VERSION 5.8 ;
BUSBITCHARS "[]" ;
DIVIDERCHAR "/" ;
UNITS
    DATABASE MICRONS 1000 ;
END UNITS

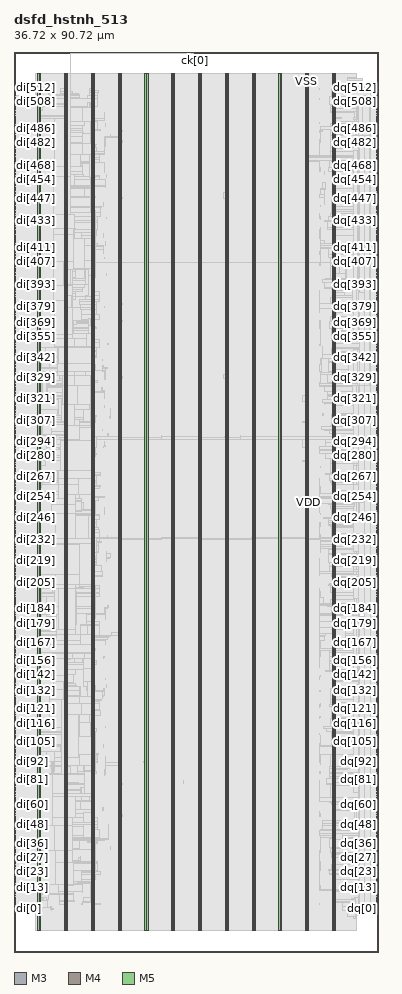
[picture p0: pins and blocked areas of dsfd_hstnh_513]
MACRO dsfd_hstnh_513
  FOREIGN dsfd_hstnh_513 0 0 ;
  CLASS BLOCK ;
  SIZE 36.72 BY 90.72 ;
  PIN ck[0]
    DIRECTION INPUT ;
    USE SIGNAL ;
    PORT
      LAYER M3 ;
        RECT  18.36 90.576 18.378 90.72 ;
    END
    PORT
      LAYER M3 ;
        RECT  18.18 90.553 18.378 90.588 ;
    END
  END ck[0]
  PIN di[0]
    DIRECTION INPUT ;
    USE SIGNAL ;
    PORT
      LAYER M4 ;
        RECT  0 4.416 0.192 4.44 ;
    END
  END di[0]
  PIN di[100]
    DIRECTION INPUT ;
    USE SIGNAL ;
    PORT
      LAYER M4 ;
        RECT  0 20.4 0.192 20.424 ;
    END
  END di[100]
  PIN di[101]
    DIRECTION INPUT ;
    USE SIGNAL ;
    PORT
      LAYER M4 ;
        RECT  0 20.592 0.192 20.616 ;
    END
  END di[101]
  PIN di[102]
    DIRECTION INPUT ;
    USE SIGNAL ;
    PORT
      LAYER M4 ;
        RECT  0 20.736 0.192 20.76 ;
    END
  END di[102]
  PIN di[103]
    DIRECTION INPUT ;
    USE SIGNAL ;
    PORT
      LAYER M4 ;
        RECT  0 20.88 0.192 20.904 ;
    END
  END di[103]
  PIN di[104]
    DIRECTION INPUT ;
    USE SIGNAL ;
    PORT
      LAYER M4 ;
        RECT  0 21.072 0.192 21.096 ;
    END
  END di[104]
  PIN di[105]
    DIRECTION INPUT ;
    USE SIGNAL ;
    PORT
      LAYER M4 ;
        RECT  0 21.216 0.192 21.24 ;
    END
  END di[105]
  PIN di[106]
    DIRECTION INPUT ;
    USE SIGNAL ;
    PORT
      LAYER M4 ;
        RECT  0 21.36 0.192 21.384 ;
    END
  END di[106]
  PIN di[107]
    DIRECTION INPUT ;
    USE SIGNAL ;
    PORT
      LAYER M4 ;
        RECT  0 21.552 0.192 21.576 ;
    END
  END di[107]
  PIN di[108]
    DIRECTION INPUT ;
    USE SIGNAL ;
    PORT
      LAYER M4 ;
        RECT  0 21.696 0.192 21.72 ;
    END
  END di[108]
  PIN di[109]
    DIRECTION INPUT ;
    USE SIGNAL ;
    PORT
      LAYER M4 ;
        RECT  0 21.84 0.192 21.864 ;
    END
  END di[109]
  PIN di[10]
    DIRECTION INPUT ;
    USE SIGNAL ;
    PORT
      LAYER M4 ;
        RECT  0 6 0.192 6.024 ;
    END
  END di[10]
  PIN di[110]
    DIRECTION INPUT ;
    USE SIGNAL ;
    PORT
      LAYER M4 ;
        RECT  0 22.032 0.192 22.056 ;
    END
  END di[110]
  PIN di[111]
    DIRECTION INPUT ;
    USE SIGNAL ;
    PORT
      LAYER M4 ;
        RECT  0 22.176 0.192 22.2 ;
    END
  END di[111]
  PIN di[112]
    DIRECTION INPUT ;
    USE SIGNAL ;
    PORT
      LAYER M4 ;
        RECT  0 22.32 0.192 22.344 ;
    END
  END di[112]
  PIN di[113]
    DIRECTION INPUT ;
    USE SIGNAL ;
    PORT
      LAYER M4 ;
        RECT  0 22.512 0.192 22.536 ;
    END
  END di[113]
  PIN di[114]
    DIRECTION INPUT ;
    USE SIGNAL ;
    PORT
      LAYER M4 ;
        RECT  0 22.656 0.192 22.68 ;
    END
  END di[114]
  PIN di[115]
    DIRECTION INPUT ;
    USE SIGNAL ;
    PORT
      LAYER M4 ;
        RECT  0 22.8 0.192 22.824 ;
    END
  END di[115]
  PIN di[116]
    DIRECTION INPUT ;
    USE SIGNAL ;
    PORT
      LAYER M4 ;
        RECT  0 22.992 0.192 23.016 ;
    END
  END di[116]
  PIN di[117]
    DIRECTION INPUT ;
    USE SIGNAL ;
    PORT
      LAYER M4 ;
        RECT  0 23.136 0.192 23.16 ;
    END
  END di[117]
  PIN di[118]
    DIRECTION INPUT ;
    USE SIGNAL ;
    PORT
      LAYER M4 ;
        RECT  0 23.28 0.192 23.304 ;
    END
  END di[118]
  PIN di[119]
    DIRECTION INPUT ;
    USE SIGNAL ;
    PORT
      LAYER M4 ;
        RECT  0 23.472 0.192 23.496 ;
    END
  END di[119]
  PIN di[11]
    DIRECTION INPUT ;
    USE SIGNAL ;
    PORT
      LAYER M4 ;
        RECT  0 6.192 0.192 6.216 ;
    END
  END di[11]
  PIN di[120]
    DIRECTION INPUT ;
    USE SIGNAL ;
    PORT
      LAYER M4 ;
        RECT  0 23.616 0.192 23.64 ;
    END
  END di[120]
  PIN di[121]
    DIRECTION INPUT ;
    USE SIGNAL ;
    PORT
      LAYER M4 ;
        RECT  0 23.76 0.192 23.784 ;
    END
  END di[121]
  PIN di[122]
    DIRECTION INPUT ;
    USE SIGNAL ;
    PORT
      LAYER M4 ;
        RECT  0 23.952 0.192 23.976 ;
    END
  END di[122]
  PIN di[123]
    DIRECTION INPUT ;
    USE SIGNAL ;
    PORT
      LAYER M4 ;
        RECT  0 24.096 0.192 24.12 ;
    END
  END di[123]
  PIN di[124]
    DIRECTION INPUT ;
    USE SIGNAL ;
    PORT
      LAYER M4 ;
        RECT  0 24.24 0.192 24.264 ;
    END
  END di[124]
  PIN di[125]
    DIRECTION INPUT ;
    USE SIGNAL ;
    PORT
      LAYER M4 ;
        RECT  0 24.432 0.192 24.456 ;
    END
  END di[125]
  PIN di[126]
    DIRECTION INPUT ;
    USE SIGNAL ;
    PORT
      LAYER M4 ;
        RECT  0 24.576 0.192 24.6 ;
    END
  END di[126]
  PIN di[127]
    DIRECTION INPUT ;
    USE SIGNAL ;
    PORT
      LAYER M4 ;
        RECT  0 24.72 0.192 24.744 ;
    END
  END di[127]
  PIN di[128]
    DIRECTION INPUT ;
    USE SIGNAL ;
    PORT
      LAYER M4 ;
        RECT  0 24.912 0.192 24.936 ;
    END
  END di[128]
  PIN di[129]
    DIRECTION INPUT ;
    USE SIGNAL ;
    PORT
      LAYER M4 ;
        RECT  0 25.056 0.192 25.08 ;
    END
  END di[129]
  PIN di[12]
    DIRECTION INPUT ;
    USE SIGNAL ;
    PORT
      LAYER M4 ;
        RECT  0 6.336 0.192 6.36 ;
    END
  END di[12]
  PIN di[130]
    DIRECTION INPUT ;
    USE SIGNAL ;
    PORT
      LAYER M4 ;
        RECT  0 25.2 0.192 25.224 ;
    END
  END di[130]
  PIN di[131]
    DIRECTION INPUT ;
    USE SIGNAL ;
    PORT
      LAYER M4 ;
        RECT  0 25.392 0.192 25.416 ;
    END
  END di[131]
  PIN di[132]
    DIRECTION INPUT ;
    USE SIGNAL ;
    PORT
      LAYER M4 ;
        RECT  0 25.536 0.192 25.56 ;
    END
  END di[132]
  PIN di[133]
    DIRECTION INPUT ;
    USE SIGNAL ;
    PORT
      LAYER M4 ;
        RECT  0 25.68 0.192 25.704 ;
    END
  END di[133]
  PIN di[134]
    DIRECTION INPUT ;
    USE SIGNAL ;
    PORT
      LAYER M4 ;
        RECT  0 25.872 0.192 25.896 ;
    END
  END di[134]
  PIN di[135]
    DIRECTION INPUT ;
    USE SIGNAL ;
    PORT
      LAYER M4 ;
        RECT  0 26.016 0.192 26.04 ;
    END
  END di[135]
  PIN di[136]
    DIRECTION INPUT ;
    USE SIGNAL ;
    PORT
      LAYER M4 ;
        RECT  0 26.16 0.192 26.184 ;
    END
  END di[136]
  PIN di[137]
    DIRECTION INPUT ;
    USE SIGNAL ;
    PORT
      LAYER M4 ;
        RECT  0 26.352 0.192 26.376 ;
    END
  END di[137]
  PIN di[138]
    DIRECTION INPUT ;
    USE SIGNAL ;
    PORT
      LAYER M4 ;
        RECT  0 26.496 0.192 26.52 ;
    END
  END di[138]
  PIN di[139]
    DIRECTION INPUT ;
    USE SIGNAL ;
    PORT
      LAYER M4 ;
        RECT  0 26.64 0.192 26.664 ;
    END
  END di[139]
  PIN di[13]
    DIRECTION INPUT ;
    USE SIGNAL ;
    PORT
      LAYER M4 ;
        RECT  0 6.48 0.192 6.504 ;
    END
  END di[13]
  PIN di[140]
    DIRECTION INPUT ;
    USE SIGNAL ;
    PORT
      LAYER M4 ;
        RECT  0 26.832 0.192 26.856 ;
    END
  END di[140]
  PIN di[141]
    DIRECTION INPUT ;
    USE SIGNAL ;
    PORT
      LAYER M4 ;
        RECT  0 26.976 0.192 27 ;
    END
  END di[141]
  PIN di[142]
    DIRECTION INPUT ;
    USE SIGNAL ;
    PORT
      LAYER M4 ;
        RECT  0 27.12 0.192 27.144 ;
    END
  END di[142]
  PIN di[143]
    DIRECTION INPUT ;
    USE SIGNAL ;
    PORT
      LAYER M4 ;
        RECT  0 27.312 0.192 27.336 ;
    END
  END di[143]
  PIN di[144]
    DIRECTION INPUT ;
    USE SIGNAL ;
    PORT
      LAYER M4 ;
        RECT  0 27.456 0.192 27.48 ;
    END
  END di[144]
  PIN di[145]
    DIRECTION INPUT ;
    USE SIGNAL ;
    PORT
      LAYER M4 ;
        RECT  0 27.6 0.192 27.624 ;
    END
  END di[145]
  PIN di[146]
    DIRECTION INPUT ;
    USE SIGNAL ;
    PORT
      LAYER M4 ;
        RECT  0 27.792 0.192 27.816 ;
    END
  END di[146]
  PIN di[147]
    DIRECTION INPUT ;
    USE SIGNAL ;
    PORT
      LAYER M4 ;
        RECT  0 27.936 0.192 27.96 ;
    END
  END di[147]
  PIN di[148]
    DIRECTION INPUT ;
    USE SIGNAL ;
    PORT
      LAYER M4 ;
        RECT  0 28.08 0.192 28.104 ;
    END
  END di[148]
  PIN di[149]
    DIRECTION INPUT ;
    USE SIGNAL ;
    PORT
      LAYER M4 ;
        RECT  0 28.272 0.192 28.296 ;
    END
  END di[149]
  PIN di[14]
    DIRECTION INPUT ;
    USE SIGNAL ;
    PORT
      LAYER M4 ;
        RECT  0 6.672 0.192 6.696 ;
    END
  END di[14]
  PIN di[150]
    DIRECTION INPUT ;
    USE SIGNAL ;
    PORT
      LAYER M4 ;
        RECT  0 28.416 0.192 28.44 ;
    END
  END di[150]
  PIN di[151]
    DIRECTION INPUT ;
    USE SIGNAL ;
    PORT
      LAYER M4 ;
        RECT  0 28.56 0.192 28.584 ;
    END
  END di[151]
  PIN di[152]
    DIRECTION INPUT ;
    USE SIGNAL ;
    PORT
      LAYER M4 ;
        RECT  0 28.752 0.192 28.776 ;
    END
  END di[152]
  PIN di[153]
    DIRECTION INPUT ;
    USE SIGNAL ;
    PORT
      LAYER M4 ;
        RECT  0 28.896 0.192 28.92 ;
    END
  END di[153]
  PIN di[154]
    DIRECTION INPUT ;
    USE SIGNAL ;
    PORT
      LAYER M4 ;
        RECT  0 29.04 0.192 29.064 ;
    END
  END di[154]
  PIN di[155]
    DIRECTION INPUT ;
    USE SIGNAL ;
    PORT
      LAYER M4 ;
        RECT  0 29.232 0.192 29.256 ;
    END
  END di[155]
  PIN di[156]
    DIRECTION INPUT ;
    USE SIGNAL ;
    PORT
      LAYER M4 ;
        RECT  0 29.376 0.192 29.4 ;
    END
  END di[156]
  PIN di[157]
    DIRECTION INPUT ;
    USE SIGNAL ;
    PORT
      LAYER M4 ;
        RECT  0 29.52 0.192 29.544 ;
    END
  END di[157]
  PIN di[158]
    DIRECTION INPUT ;
    USE SIGNAL ;
    PORT
      LAYER M4 ;
        RECT  0 29.712 0.192 29.736 ;
    END
  END di[158]
  PIN di[159]
    DIRECTION INPUT ;
    USE SIGNAL ;
    PORT
      LAYER M4 ;
        RECT  0 29.856 0.192 29.88 ;
    END
  END di[159]
  PIN di[15]
    DIRECTION INPUT ;
    USE SIGNAL ;
    PORT
      LAYER M4 ;
        RECT  0 6.816 0.192 6.84 ;
    END
  END di[15]
  PIN di[160]
    DIRECTION INPUT ;
    USE SIGNAL ;
    PORT
      LAYER M4 ;
        RECT  0 30 0.192 30.024 ;
    END
  END di[160]
  PIN di[161]
    DIRECTION INPUT ;
    USE SIGNAL ;
    PORT
      LAYER M4 ;
        RECT  0 30.192 0.192 30.216 ;
    END
  END di[161]
  PIN di[162]
    DIRECTION INPUT ;
    USE SIGNAL ;
    PORT
      LAYER M4 ;
        RECT  0 30.336 0.192 30.36 ;
    END
  END di[162]
  PIN di[163]
    DIRECTION INPUT ;
    USE SIGNAL ;
    PORT
      LAYER M4 ;
        RECT  0 30.48 0.192 30.504 ;
    END
  END di[163]
  PIN di[164]
    DIRECTION INPUT ;
    USE SIGNAL ;
    PORT
      LAYER M4 ;
        RECT  0 30.672 0.192 30.696 ;
    END
  END di[164]
  PIN di[165]
    DIRECTION INPUT ;
    USE SIGNAL ;
    PORT
      LAYER M4 ;
        RECT  0 30.816 0.192 30.84 ;
    END
  END di[165]
  PIN di[166]
    DIRECTION INPUT ;
    USE SIGNAL ;
    PORT
      LAYER M4 ;
        RECT  0 30.96 0.192 30.984 ;
    END
  END di[166]
  PIN di[167]
    DIRECTION INPUT ;
    USE SIGNAL ;
    PORT
      LAYER M4 ;
        RECT  0 31.152 0.192 31.176 ;
    END
  END di[167]
  PIN di[168]
    DIRECTION INPUT ;
    USE SIGNAL ;
    PORT
      LAYER M4 ;
        RECT  0 31.296 0.192 31.32 ;
    END
  END di[168]
  PIN di[169]
    DIRECTION INPUT ;
    USE SIGNAL ;
    PORT
      LAYER M4 ;
        RECT  0 31.44 0.192 31.464 ;
    END
  END di[169]
  PIN di[16]
    DIRECTION INPUT ;
    USE SIGNAL ;
    PORT
      LAYER M4 ;
        RECT  0 6.96 0.192 6.984 ;
    END
  END di[16]
  PIN di[170]
    DIRECTION INPUT ;
    USE SIGNAL ;
    PORT
      LAYER M4 ;
        RECT  0 31.632 0.192 31.656 ;
    END
  END di[170]
  PIN di[171]
    DIRECTION INPUT ;
    USE SIGNAL ;
    PORT
      LAYER M4 ;
        RECT  0 31.776 0.192 31.8 ;
    END
  END di[171]
  PIN di[172]
    DIRECTION INPUT ;
    USE SIGNAL ;
    PORT
      LAYER M4 ;
        RECT  0 31.92 0.192 31.944 ;
    END
  END di[172]
  PIN di[173]
    DIRECTION INPUT ;
    USE SIGNAL ;
    PORT
      LAYER M4 ;
        RECT  0 32.112 0.192 32.136 ;
    END
  END di[173]
  PIN di[174]
    DIRECTION INPUT ;
    USE SIGNAL ;
    PORT
      LAYER M4 ;
        RECT  0 32.256 0.192 32.28 ;
    END
  END di[174]
  PIN di[175]
    DIRECTION INPUT ;
    USE SIGNAL ;
    PORT
      LAYER M4 ;
        RECT  0 32.4 0.192 32.424 ;
    END
  END di[175]
  PIN di[176]
    DIRECTION INPUT ;
    USE SIGNAL ;
    PORT
      LAYER M4 ;
        RECT  0 32.592 0.192 32.616 ;
    END
  END di[176]
  PIN di[177]
    DIRECTION INPUT ;
    USE SIGNAL ;
    PORT
      LAYER M4 ;
        RECT  0 32.736 0.192 32.76 ;
    END
  END di[177]
  PIN di[178]
    DIRECTION INPUT ;
    USE SIGNAL ;
    PORT
      LAYER M4 ;
        RECT  0 32.88 0.192 32.904 ;
    END
  END di[178]
  PIN di[179]
    DIRECTION INPUT ;
    USE SIGNAL ;
    PORT
      LAYER M4 ;
        RECT  0 33.072 0.192 33.096 ;
    END
  END di[179]
  PIN di[17]
    DIRECTION INPUT ;
    USE SIGNAL ;
    PORT
      LAYER M4 ;
        RECT  0 7.152 0.192 7.176 ;
    END
  END di[17]
  PIN di[180]
    DIRECTION INPUT ;
    USE SIGNAL ;
    PORT
      LAYER M4 ;
        RECT  0 33.216 0.192 33.24 ;
    END
  END di[180]
  PIN di[181]
    DIRECTION INPUT ;
    USE SIGNAL ;
    PORT
      LAYER M4 ;
        RECT  0 33.36 0.192 33.384 ;
    END
  END di[181]
  PIN di[182]
    DIRECTION INPUT ;
    USE SIGNAL ;
    PORT
      LAYER M4 ;
        RECT  0 33.552 0.192 33.576 ;
    END
  END di[182]
  PIN di[183]
    DIRECTION INPUT ;
    USE SIGNAL ;
    PORT
      LAYER M4 ;
        RECT  0 33.696 0.192 33.72 ;
    END
  END di[183]
  PIN di[184]
    DIRECTION INPUT ;
    USE SIGNAL ;
    PORT
      LAYER M4 ;
        RECT  0 33.84 0.192 33.864 ;
    END
  END di[184]
  PIN di[185]
    DIRECTION INPUT ;
    USE SIGNAL ;
    PORT
      LAYER M4 ;
        RECT  0 34.032 0.192 34.056 ;
    END
  END di[185]
  PIN di[186]
    DIRECTION INPUT ;
    USE SIGNAL ;
    PORT
      LAYER M4 ;
        RECT  0 34.176 0.192 34.2 ;
    END
  END di[186]
  PIN di[187]
    DIRECTION INPUT ;
    USE SIGNAL ;
    PORT
      LAYER M4 ;
        RECT  0 34.32 0.192 34.344 ;
    END
  END di[187]
  PIN di[188]
    DIRECTION INPUT ;
    USE SIGNAL ;
    PORT
      LAYER M4 ;
        RECT  0 34.512 0.192 34.536 ;
    END
  END di[188]
  PIN di[189]
    DIRECTION INPUT ;
    USE SIGNAL ;
    PORT
      LAYER M4 ;
        RECT  0 34.656 0.192 34.68 ;
    END
  END di[189]
  PIN di[18]
    DIRECTION INPUT ;
    USE SIGNAL ;
    PORT
      LAYER M4 ;
        RECT  0 7.296 0.192 7.32 ;
    END
  END di[18]
  PIN di[190]
    DIRECTION INPUT ;
    USE SIGNAL ;
    PORT
      LAYER M4 ;
        RECT  0 34.8 0.192 34.824 ;
    END
  END di[190]
  PIN di[191]
    DIRECTION INPUT ;
    USE SIGNAL ;
    PORT
      LAYER M4 ;
        RECT  0 34.992 0.192 35.016 ;
    END
  END di[191]
  PIN di[192]
    DIRECTION INPUT ;
    USE SIGNAL ;
    PORT
      LAYER M4 ;
        RECT  0 35.136 0.192 35.16 ;
    END
  END di[192]
  PIN di[193]
    DIRECTION INPUT ;
    USE SIGNAL ;
    PORT
      LAYER M4 ;
        RECT  0 35.28 0.192 35.304 ;
    END
  END di[193]
  PIN di[194]
    DIRECTION INPUT ;
    USE SIGNAL ;
    PORT
      LAYER M4 ;
        RECT  0 35.472 0.192 35.496 ;
    END
  END di[194]
  PIN di[195]
    DIRECTION INPUT ;
    USE SIGNAL ;
    PORT
      LAYER M4 ;
        RECT  0 35.616 0.192 35.64 ;
    END
  END di[195]
  PIN di[196]
    DIRECTION INPUT ;
    USE SIGNAL ;
    PORT
      LAYER M4 ;
        RECT  0 35.76 0.192 35.784 ;
    END
  END di[196]
  PIN di[197]
    DIRECTION INPUT ;
    USE SIGNAL ;
    PORT
      LAYER M4 ;
        RECT  0 35.952 0.192 35.976 ;
    END
  END di[197]
  PIN di[198]
    DIRECTION INPUT ;
    USE SIGNAL ;
    PORT
      LAYER M4 ;
        RECT  0 36.096 0.192 36.12 ;
    END
  END di[198]
  PIN di[199]
    DIRECTION INPUT ;
    USE SIGNAL ;
    PORT
      LAYER M4 ;
        RECT  0 36.24 0.192 36.264 ;
    END
  END di[199]
  PIN di[19]
    DIRECTION INPUT ;
    USE SIGNAL ;
    PORT
      LAYER M4 ;
        RECT  0 7.44 0.192 7.464 ;
    END
  END di[19]
  PIN di[1]
    DIRECTION INPUT ;
    USE SIGNAL ;
    PORT
      LAYER M4 ;
        RECT  0 4.56 0.192 4.584 ;
    END
  END di[1]
  PIN di[200]
    DIRECTION INPUT ;
    USE SIGNAL ;
    PORT
      LAYER M4 ;
        RECT  0 36.432 0.192 36.456 ;
    END
  END di[200]
  PIN di[201]
    DIRECTION INPUT ;
    USE SIGNAL ;
    PORT
      LAYER M4 ;
        RECT  0 36.576 0.192 36.6 ;
    END
  END di[201]
  PIN di[202]
    DIRECTION INPUT ;
    USE SIGNAL ;
    PORT
      LAYER M4 ;
        RECT  0 36.72 0.192 36.744 ;
    END
  END di[202]
  PIN di[203]
    DIRECTION INPUT ;
    USE SIGNAL ;
    PORT
      LAYER M4 ;
        RECT  0 36.912 0.192 36.936 ;
    END
  END di[203]
  PIN di[204]
    DIRECTION INPUT ;
    USE SIGNAL ;
    PORT
      LAYER M4 ;
        RECT  0 37.056 0.192 37.08 ;
    END
  END di[204]
  PIN di[205]
    DIRECTION INPUT ;
    USE SIGNAL ;
    PORT
      LAYER M4 ;
        RECT  0 37.2 0.192 37.224 ;
    END
  END di[205]
  PIN di[206]
    DIRECTION INPUT ;
    USE SIGNAL ;
    PORT
      LAYER M4 ;
        RECT  0 37.392 0.192 37.416 ;
    END
  END di[206]
  PIN di[207]
    DIRECTION INPUT ;
    USE SIGNAL ;
    PORT
      LAYER M4 ;
        RECT  0 37.536 0.192 37.56 ;
    END
  END di[207]
  PIN di[208]
    DIRECTION INPUT ;
    USE SIGNAL ;
    PORT
      LAYER M4 ;
        RECT  0 37.68 0.192 37.704 ;
    END
  END di[208]
  PIN di[209]
    DIRECTION INPUT ;
    USE SIGNAL ;
    PORT
      LAYER M4 ;
        RECT  0 37.872 0.192 37.896 ;
    END
  END di[209]
  PIN di[20]
    DIRECTION INPUT ;
    USE SIGNAL ;
    PORT
      LAYER M4 ;
        RECT  0 7.632 0.192 7.656 ;
    END
  END di[20]
  PIN di[210]
    DIRECTION INPUT ;
    USE SIGNAL ;
    PORT
      LAYER M4 ;
        RECT  0 38.016 0.192 38.04 ;
    END
  END di[210]
  PIN di[211]
    DIRECTION INPUT ;
    USE SIGNAL ;
    PORT
      LAYER M4 ;
        RECT  0 38.16 0.192 38.184 ;
    END
  END di[211]
  PIN di[212]
    DIRECTION INPUT ;
    USE SIGNAL ;
    PORT
      LAYER M4 ;
        RECT  0 38.352 0.192 38.376 ;
    END
  END di[212]
  PIN di[213]
    DIRECTION INPUT ;
    USE SIGNAL ;
    PORT
      LAYER M4 ;
        RECT  0 38.496 0.192 38.52 ;
    END
  END di[213]
  PIN di[214]
    DIRECTION INPUT ;
    USE SIGNAL ;
    PORT
      LAYER M4 ;
        RECT  0 38.64 0.192 38.664 ;
    END
  END di[214]
  PIN di[215]
    DIRECTION INPUT ;
    USE SIGNAL ;
    PORT
      LAYER M4 ;
        RECT  0 38.832 0.192 38.856 ;
    END
  END di[215]
  PIN di[216]
    DIRECTION INPUT ;
    USE SIGNAL ;
    PORT
      LAYER M4 ;
        RECT  0 38.976 0.192 39 ;
    END
  END di[216]
  PIN di[217]
    DIRECTION INPUT ;
    USE SIGNAL ;
    PORT
      LAYER M4 ;
        RECT  0 39.12 0.192 39.144 ;
    END
  END di[217]
  PIN di[218]
    DIRECTION INPUT ;
    USE SIGNAL ;
    PORT
      LAYER M4 ;
        RECT  0 39.312 0.192 39.336 ;
    END
  END di[218]
  PIN di[219]
    DIRECTION INPUT ;
    USE SIGNAL ;
    PORT
      LAYER M4 ;
        RECT  0 39.456 0.192 39.48 ;
    END
  END di[219]
  PIN di[21]
    DIRECTION INPUT ;
    USE SIGNAL ;
    PORT
      LAYER M4 ;
        RECT  0 7.776 0.192 7.8 ;
    END
  END di[21]
  PIN di[220]
    DIRECTION INPUT ;
    USE SIGNAL ;
    PORT
      LAYER M4 ;
        RECT  0 39.6 0.192 39.624 ;
    END
  END di[220]
  PIN di[221]
    DIRECTION INPUT ;
    USE SIGNAL ;
    PORT
      LAYER M4 ;
        RECT  0 39.792 0.192 39.816 ;
    END
  END di[221]
  PIN di[222]
    DIRECTION INPUT ;
    USE SIGNAL ;
    PORT
      LAYER M4 ;
        RECT  0 39.936 0.192 39.96 ;
    END
  END di[222]
  PIN di[223]
    DIRECTION INPUT ;
    USE SIGNAL ;
    PORT
      LAYER M4 ;
        RECT  0 40.08 0.192 40.104 ;
    END
  END di[223]
  PIN di[224]
    DIRECTION INPUT ;
    USE SIGNAL ;
    PORT
      LAYER M4 ;
        RECT  0 40.272 0.192 40.296 ;
    END
  END di[224]
  PIN di[225]
    DIRECTION INPUT ;
    USE SIGNAL ;
    PORT
      LAYER M4 ;
        RECT  0 40.416 0.192 40.44 ;
    END
  END di[225]
  PIN di[226]
    DIRECTION INPUT ;
    USE SIGNAL ;
    PORT
      LAYER M4 ;
        RECT  0 40.56 0.192 40.584 ;
    END
  END di[226]
  PIN di[227]
    DIRECTION INPUT ;
    USE SIGNAL ;
    PORT
      LAYER M4 ;
        RECT  0 40.752 0.192 40.776 ;
    END
  END di[227]
  PIN di[228]
    DIRECTION INPUT ;
    USE SIGNAL ;
    PORT
      LAYER M4 ;
        RECT  0 40.896 0.192 40.92 ;
    END
  END di[228]
  PIN di[229]
    DIRECTION INPUT ;
    USE SIGNAL ;
    PORT
      LAYER M4 ;
        RECT  0 41.04 0.192 41.064 ;
    END
  END di[229]
  PIN di[22]
    DIRECTION INPUT ;
    USE SIGNAL ;
    PORT
      LAYER M4 ;
        RECT  0 7.92 0.192 7.944 ;
    END
  END di[22]
  PIN di[230]
    DIRECTION INPUT ;
    USE SIGNAL ;
    PORT
      LAYER M4 ;
        RECT  0 41.232 0.192 41.256 ;
    END
  END di[230]
  PIN di[231]
    DIRECTION INPUT ;
    USE SIGNAL ;
    PORT
      LAYER M4 ;
        RECT  0 41.376 0.192 41.4 ;
    END
  END di[231]
  PIN di[232]
    DIRECTION INPUT ;
    USE SIGNAL ;
    PORT
      LAYER M4 ;
        RECT  0 41.52 0.192 41.544 ;
    END
  END di[232]
  PIN di[233]
    DIRECTION INPUT ;
    USE SIGNAL ;
    PORT
      LAYER M4 ;
        RECT  0 41.712 0.192 41.736 ;
    END
  END di[233]
  PIN di[234]
    DIRECTION INPUT ;
    USE SIGNAL ;
    PORT
      LAYER M4 ;
        RECT  0 41.856 0.192 41.88 ;
    END
  END di[234]
  PIN di[235]
    DIRECTION INPUT ;
    USE SIGNAL ;
    PORT
      LAYER M4 ;
        RECT  0 42 0.192 42.024 ;
    END
  END di[235]
  PIN di[236]
    DIRECTION INPUT ;
    USE SIGNAL ;
    PORT
      LAYER M4 ;
        RECT  0 42.192 0.192 42.216 ;
    END
  END di[236]
  PIN di[237]
    DIRECTION INPUT ;
    USE SIGNAL ;
    PORT
      LAYER M4 ;
        RECT  0 42.336 0.192 42.36 ;
    END
  END di[237]
  PIN di[238]
    DIRECTION INPUT ;
    USE SIGNAL ;
    PORT
      LAYER M4 ;
        RECT  0 42.48 0.192 42.504 ;
    END
  END di[238]
  PIN di[239]
    DIRECTION INPUT ;
    USE SIGNAL ;
    PORT
      LAYER M4 ;
        RECT  0 42.672 0.192 42.696 ;
    END
  END di[239]
  PIN di[23]
    DIRECTION INPUT ;
    USE SIGNAL ;
    PORT
      LAYER M4 ;
        RECT  0 8.112 0.192 8.136 ;
    END
  END di[23]
  PIN di[240]
    DIRECTION INPUT ;
    USE SIGNAL ;
    PORT
      LAYER M4 ;
        RECT  0 42.816 0.192 42.84 ;
    END
  END di[240]
  PIN di[241]
    DIRECTION INPUT ;
    USE SIGNAL ;
    PORT
      LAYER M4 ;
        RECT  0 42.96 0.192 42.984 ;
    END
  END di[241]
  PIN di[242]
    DIRECTION INPUT ;
    USE SIGNAL ;
    PORT
      LAYER M4 ;
        RECT  0 43.152 0.192 43.176 ;
    END
  END di[242]
  PIN di[243]
    DIRECTION INPUT ;
    USE SIGNAL ;
    PORT
      LAYER M4 ;
        RECT  0 43.296 0.192 43.32 ;
    END
  END di[243]
  PIN di[244]
    DIRECTION INPUT ;
    USE SIGNAL ;
    PORT
      LAYER M4 ;
        RECT  0 43.44 0.192 43.464 ;
    END
  END di[244]
  PIN di[245]
    DIRECTION INPUT ;
    USE SIGNAL ;
    PORT
      LAYER M4 ;
        RECT  0 43.632 0.192 43.656 ;
    END
  END di[245]
  PIN di[246]
    DIRECTION INPUT ;
    USE SIGNAL ;
    PORT
      LAYER M4 ;
        RECT  0 43.776 0.192 43.8 ;
    END
  END di[246]
  PIN di[247]
    DIRECTION INPUT ;
    USE SIGNAL ;
    PORT
      LAYER M4 ;
        RECT  0 43.92 0.192 43.944 ;
    END
  END di[247]
  PIN di[248]
    DIRECTION INPUT ;
    USE SIGNAL ;
    PORT
      LAYER M4 ;
        RECT  0 44.112 0.192 44.136 ;
    END
  END di[248]
  PIN di[249]
    DIRECTION INPUT ;
    USE SIGNAL ;
    PORT
      LAYER M4 ;
        RECT  0 44.256 0.192 44.28 ;
    END
  END di[249]
  PIN di[24]
    DIRECTION INPUT ;
    USE SIGNAL ;
    PORT
      LAYER M4 ;
        RECT  0 8.256 0.192 8.28 ;
    END
  END di[24]
  PIN di[250]
    DIRECTION INPUT ;
    USE SIGNAL ;
    PORT
      LAYER M4 ;
        RECT  0 44.4 0.192 44.424 ;
    END
  END di[250]
  PIN di[251]
    DIRECTION INPUT ;
    USE SIGNAL ;
    PORT
      LAYER M4 ;
        RECT  0 44.592 0.192 44.616 ;
    END
  END di[251]
  PIN di[252]
    DIRECTION INPUT ;
    USE SIGNAL ;
    PORT
      LAYER M4 ;
        RECT  0 44.736 0.192 44.76 ;
    END
  END di[252]
  PIN di[253]
    DIRECTION INPUT ;
    USE SIGNAL ;
    PORT
      LAYER M4 ;
        RECT  0 44.88 0.192 44.904 ;
    END
  END di[253]
  PIN di[254]
    DIRECTION INPUT ;
    USE SIGNAL ;
    PORT
      LAYER M4 ;
        RECT  0 45.072 0.192 45.096 ;
    END
  END di[254]
  PIN di[255]
    DIRECTION INPUT ;
    USE SIGNAL ;
    PORT
      LAYER M4 ;
        RECT  0 45.216 0.192 45.24 ;
    END
  END di[255]
  PIN di[256]
    DIRECTION INPUT ;
    USE SIGNAL ;
    PORT
      LAYER M4 ;
        RECT  0 45.36 0.192 45.384 ;
    END
  END di[256]
  PIN di[257]
    DIRECTION INPUT ;
    USE SIGNAL ;
    PORT
      LAYER M4 ;
        RECT  0 45.552 0.192 45.576 ;
    END
  END di[257]
  PIN di[258]
    DIRECTION INPUT ;
    USE SIGNAL ;
    PORT
      LAYER M4 ;
        RECT  0 45.696 0.192 45.72 ;
    END
  END di[258]
  PIN di[259]
    DIRECTION INPUT ;
    USE SIGNAL ;
    PORT
      LAYER M4 ;
        RECT  0 45.84 0.192 45.864 ;
    END
  END di[259]
  PIN di[25]
    DIRECTION INPUT ;
    USE SIGNAL ;
    PORT
      LAYER M4 ;
        RECT  0 8.4 0.192 8.424 ;
    END
  END di[25]
  PIN di[260]
    DIRECTION INPUT ;
    USE SIGNAL ;
    PORT
      LAYER M4 ;
        RECT  0 46.032 0.192 46.056 ;
    END
  END di[260]
  PIN di[261]
    DIRECTION INPUT ;
    USE SIGNAL ;
    PORT
      LAYER M4 ;
        RECT  0 46.176 0.192 46.2 ;
    END
  END di[261]
  PIN di[262]
    DIRECTION INPUT ;
    USE SIGNAL ;
    PORT
      LAYER M4 ;
        RECT  0 46.32 0.192 46.344 ;
    END
  END di[262]
  PIN di[263]
    DIRECTION INPUT ;
    USE SIGNAL ;
    PORT
      LAYER M4 ;
        RECT  0 46.512 0.192 46.536 ;
    END
  END di[263]
  PIN di[264]
    DIRECTION INPUT ;
    USE SIGNAL ;
    PORT
      LAYER M4 ;
        RECT  0 46.656 0.192 46.68 ;
    END
  END di[264]
  PIN di[265]
    DIRECTION INPUT ;
    USE SIGNAL ;
    PORT
      LAYER M4 ;
        RECT  0 46.8 0.192 46.824 ;
    END
  END di[265]
  PIN di[266]
    DIRECTION INPUT ;
    USE SIGNAL ;
    PORT
      LAYER M4 ;
        RECT  0 46.992 0.192 47.016 ;
    END
  END di[266]
  PIN di[267]
    DIRECTION INPUT ;
    USE SIGNAL ;
    PORT
      LAYER M4 ;
        RECT  0 47.136 0.192 47.16 ;
    END
  END di[267]
  PIN di[268]
    DIRECTION INPUT ;
    USE SIGNAL ;
    PORT
      LAYER M4 ;
        RECT  0 47.28 0.192 47.304 ;
    END
  END di[268]
  PIN di[269]
    DIRECTION INPUT ;
    USE SIGNAL ;
    PORT
      LAYER M4 ;
        RECT  0 47.472 0.192 47.496 ;
    END
  END di[269]
  PIN di[26]
    DIRECTION INPUT ;
    USE SIGNAL ;
    PORT
      LAYER M4 ;
        RECT  0 8.592 0.192 8.616 ;
    END
  END di[26]
  PIN di[270]
    DIRECTION INPUT ;
    USE SIGNAL ;
    PORT
      LAYER M4 ;
        RECT  0 47.616 0.192 47.64 ;
    END
  END di[270]
  PIN di[271]
    DIRECTION INPUT ;
    USE SIGNAL ;
    PORT
      LAYER M4 ;
        RECT  0 47.76 0.192 47.784 ;
    END
  END di[271]
  PIN di[272]
    DIRECTION INPUT ;
    USE SIGNAL ;
    PORT
      LAYER M4 ;
        RECT  0 47.952 0.192 47.976 ;
    END
  END di[272]
  PIN di[273]
    DIRECTION INPUT ;
    USE SIGNAL ;
    PORT
      LAYER M4 ;
        RECT  0 48.096 0.192 48.12 ;
    END
  END di[273]
  PIN di[274]
    DIRECTION INPUT ;
    USE SIGNAL ;
    PORT
      LAYER M4 ;
        RECT  0 48.24 0.192 48.264 ;
    END
  END di[274]
  PIN di[275]
    DIRECTION INPUT ;
    USE SIGNAL ;
    PORT
      LAYER M4 ;
        RECT  0 48.432 0.192 48.456 ;
    END
  END di[275]
  PIN di[276]
    DIRECTION INPUT ;
    USE SIGNAL ;
    PORT
      LAYER M4 ;
        RECT  0 48.576 0.192 48.6 ;
    END
  END di[276]
  PIN di[277]
    DIRECTION INPUT ;
    USE SIGNAL ;
    PORT
      LAYER M4 ;
        RECT  0 48.72 0.192 48.744 ;
    END
  END di[277]
  PIN di[278]
    DIRECTION INPUT ;
    USE SIGNAL ;
    PORT
      LAYER M4 ;
        RECT  0 48.912 0.192 48.936 ;
    END
  END di[278]
  PIN di[279]
    DIRECTION INPUT ;
    USE SIGNAL ;
    PORT
      LAYER M4 ;
        RECT  0 49.056 0.192 49.08 ;
    END
  END di[279]
  PIN di[27]
    DIRECTION INPUT ;
    USE SIGNAL ;
    PORT
      LAYER M4 ;
        RECT  0 8.736 0.192 8.76 ;
    END
  END di[27]
  PIN di[280]
    DIRECTION INPUT ;
    USE SIGNAL ;
    PORT
      LAYER M4 ;
        RECT  0 49.2 0.192 49.224 ;
    END
  END di[280]
  PIN di[281]
    DIRECTION INPUT ;
    USE SIGNAL ;
    PORT
      LAYER M4 ;
        RECT  0 49.392 0.192 49.416 ;
    END
  END di[281]
  PIN di[282]
    DIRECTION INPUT ;
    USE SIGNAL ;
    PORT
      LAYER M4 ;
        RECT  0 49.536 0.192 49.56 ;
    END
  END di[282]
  PIN di[283]
    DIRECTION INPUT ;
    USE SIGNAL ;
    PORT
      LAYER M4 ;
        RECT  0 49.68 0.192 49.704 ;
    END
  END di[283]
  PIN di[284]
    DIRECTION INPUT ;
    USE SIGNAL ;
    PORT
      LAYER M4 ;
        RECT  0 49.872 0.192 49.896 ;
    END
  END di[284]
  PIN di[285]
    DIRECTION INPUT ;
    USE SIGNAL ;
    PORT
      LAYER M4 ;
        RECT  0 50.016 0.192 50.04 ;
    END
  END di[285]
  PIN di[286]
    DIRECTION INPUT ;
    USE SIGNAL ;
    PORT
      LAYER M4 ;
        RECT  0 50.16 0.192 50.184 ;
    END
  END di[286]
  PIN di[287]
    DIRECTION INPUT ;
    USE SIGNAL ;
    PORT
      LAYER M4 ;
        RECT  0 50.352 0.192 50.376 ;
    END
  END di[287]
  PIN di[288]
    DIRECTION INPUT ;
    USE SIGNAL ;
    PORT
      LAYER M4 ;
        RECT  0 50.496 0.192 50.52 ;
    END
  END di[288]
  PIN di[289]
    DIRECTION INPUT ;
    USE SIGNAL ;
    PORT
      LAYER M4 ;
        RECT  0 50.64 0.192 50.664 ;
    END
  END di[289]
  PIN di[28]
    DIRECTION INPUT ;
    USE SIGNAL ;
    PORT
      LAYER M4 ;
        RECT  0 8.88 0.192 8.904 ;
    END
  END di[28]
  PIN di[290]
    DIRECTION INPUT ;
    USE SIGNAL ;
    PORT
      LAYER M4 ;
        RECT  0 50.832 0.192 50.856 ;
    END
  END di[290]
  PIN di[291]
    DIRECTION INPUT ;
    USE SIGNAL ;
    PORT
      LAYER M4 ;
        RECT  0 50.976 0.192 51 ;
    END
  END di[291]
  PIN di[292]
    DIRECTION INPUT ;
    USE SIGNAL ;
    PORT
      LAYER M4 ;
        RECT  0 51.12 0.192 51.144 ;
    END
  END di[292]
  PIN di[293]
    DIRECTION INPUT ;
    USE SIGNAL ;
    PORT
      LAYER M4 ;
        RECT  0 51.312 0.192 51.336 ;
    END
  END di[293]
  PIN di[294]
    DIRECTION INPUT ;
    USE SIGNAL ;
    PORT
      LAYER M4 ;
        RECT  0 51.456 0.192 51.48 ;
    END
  END di[294]
  PIN di[295]
    DIRECTION INPUT ;
    USE SIGNAL ;
    PORT
      LAYER M4 ;
        RECT  0 51.6 0.192 51.624 ;
    END
  END di[295]
  PIN di[296]
    DIRECTION INPUT ;
    USE SIGNAL ;
    PORT
      LAYER M4 ;
        RECT  0 51.792 0.192 51.816 ;
    END
  END di[296]
  PIN di[297]
    DIRECTION INPUT ;
    USE SIGNAL ;
    PORT
      LAYER M4 ;
        RECT  0 51.936 0.192 51.96 ;
    END
  END di[297]
  PIN di[298]
    DIRECTION INPUT ;
    USE SIGNAL ;
    PORT
      LAYER M4 ;
        RECT  0 52.08 0.192 52.104 ;
    END
  END di[298]
  PIN di[299]
    DIRECTION INPUT ;
    USE SIGNAL ;
    PORT
      LAYER M4 ;
        RECT  0 52.272 0.192 52.296 ;
    END
  END di[299]
  PIN di[29]
    DIRECTION INPUT ;
    USE SIGNAL ;
    PORT
      LAYER M4 ;
        RECT  0 9.072 0.192 9.096 ;
    END
  END di[29]
  PIN di[2]
    DIRECTION INPUT ;
    USE SIGNAL ;
    PORT
      LAYER M4 ;
        RECT  0 4.752 0.192 4.776 ;
    END
  END di[2]
  PIN di[300]
    DIRECTION INPUT ;
    USE SIGNAL ;
    PORT
      LAYER M4 ;
        RECT  0 52.416 0.192 52.44 ;
    END
  END di[300]
  PIN di[301]
    DIRECTION INPUT ;
    USE SIGNAL ;
    PORT
      LAYER M4 ;
        RECT  0 52.56 0.192 52.584 ;
    END
  END di[301]
  PIN di[302]
    DIRECTION INPUT ;
    USE SIGNAL ;
    PORT
      LAYER M4 ;
        RECT  0 52.752 0.192 52.776 ;
    END
  END di[302]
  PIN di[303]
    DIRECTION INPUT ;
    USE SIGNAL ;
    PORT
      LAYER M4 ;
        RECT  0 52.896 0.192 52.92 ;
    END
  END di[303]
  PIN di[304]
    DIRECTION INPUT ;
    USE SIGNAL ;
    PORT
      LAYER M4 ;
        RECT  0 53.04 0.192 53.064 ;
    END
  END di[304]
  PIN di[305]
    DIRECTION INPUT ;
    USE SIGNAL ;
    PORT
      LAYER M4 ;
        RECT  0 53.232 0.192 53.256 ;
    END
  END di[305]
  PIN di[306]
    DIRECTION INPUT ;
    USE SIGNAL ;
    PORT
      LAYER M4 ;
        RECT  0 53.376 0.192 53.4 ;
    END
  END di[306]
  PIN di[307]
    DIRECTION INPUT ;
    USE SIGNAL ;
    PORT
      LAYER M4 ;
        RECT  0 53.52 0.192 53.544 ;
    END
  END di[307]
  PIN di[308]
    DIRECTION INPUT ;
    USE SIGNAL ;
    PORT
      LAYER M4 ;
        RECT  0 53.712 0.192 53.736 ;
    END
  END di[308]
  PIN di[309]
    DIRECTION INPUT ;
    USE SIGNAL ;
    PORT
      LAYER M4 ;
        RECT  0 53.856 0.192 53.88 ;
    END
  END di[309]
  PIN di[30]
    DIRECTION INPUT ;
    USE SIGNAL ;
    PORT
      LAYER M4 ;
        RECT  0 9.216 0.192 9.24 ;
    END
  END di[30]
  PIN di[310]
    DIRECTION INPUT ;
    USE SIGNAL ;
    PORT
      LAYER M4 ;
        RECT  0 54 0.192 54.024 ;
    END
  END di[310]
  PIN di[311]
    DIRECTION INPUT ;
    USE SIGNAL ;
    PORT
      LAYER M4 ;
        RECT  0 54.192 0.192 54.216 ;
    END
  END di[311]
  PIN di[312]
    DIRECTION INPUT ;
    USE SIGNAL ;
    PORT
      LAYER M4 ;
        RECT  0 54.336 0.192 54.36 ;
    END
  END di[312]
  PIN di[313]
    DIRECTION INPUT ;
    USE SIGNAL ;
    PORT
      LAYER M4 ;
        RECT  0 54.48 0.192 54.504 ;
    END
  END di[313]
  PIN di[314]
    DIRECTION INPUT ;
    USE SIGNAL ;
    PORT
      LAYER M4 ;
        RECT  0 54.672 0.192 54.696 ;
    END
  END di[314]
  PIN di[315]
    DIRECTION INPUT ;
    USE SIGNAL ;
    PORT
      LAYER M4 ;
        RECT  0 54.816 0.192 54.84 ;
    END
  END di[315]
  PIN di[316]
    DIRECTION INPUT ;
    USE SIGNAL ;
    PORT
      LAYER M4 ;
        RECT  0 54.96 0.192 54.984 ;
    END
  END di[316]
  PIN di[317]
    DIRECTION INPUT ;
    USE SIGNAL ;
    PORT
      LAYER M4 ;
        RECT  0 55.152 0.192 55.176 ;
    END
  END di[317]
  PIN di[318]
    DIRECTION INPUT ;
    USE SIGNAL ;
    PORT
      LAYER M4 ;
        RECT  0 55.296 0.192 55.32 ;
    END
  END di[318]
  PIN di[319]
    DIRECTION INPUT ;
    USE SIGNAL ;
    PORT
      LAYER M4 ;
        RECT  0 55.44 0.192 55.464 ;
    END
  END di[319]
  PIN di[31]
    DIRECTION INPUT ;
    USE SIGNAL ;
    PORT
      LAYER M4 ;
        RECT  0 9.36 0.192 9.384 ;
    END
  END di[31]
  PIN di[320]
    DIRECTION INPUT ;
    USE SIGNAL ;
    PORT
      LAYER M4 ;
        RECT  0 55.632 0.192 55.656 ;
    END
  END di[320]
  PIN di[321]
    DIRECTION INPUT ;
    USE SIGNAL ;
    PORT
      LAYER M4 ;
        RECT  0 55.776 0.192 55.8 ;
    END
  END di[321]
  PIN di[322]
    DIRECTION INPUT ;
    USE SIGNAL ;
    PORT
      LAYER M4 ;
        RECT  0 55.92 0.192 55.944 ;
    END
  END di[322]
  PIN di[323]
    DIRECTION INPUT ;
    USE SIGNAL ;
    PORT
      LAYER M4 ;
        RECT  0 56.112 0.192 56.136 ;
    END
  END di[323]
  PIN di[324]
    DIRECTION INPUT ;
    USE SIGNAL ;
    PORT
      LAYER M4 ;
        RECT  0 56.256 0.192 56.28 ;
    END
  END di[324]
  PIN di[325]
    DIRECTION INPUT ;
    USE SIGNAL ;
    PORT
      LAYER M4 ;
        RECT  0 56.4 0.192 56.424 ;
    END
  END di[325]
  PIN di[326]
    DIRECTION INPUT ;
    USE SIGNAL ;
    PORT
      LAYER M4 ;
        RECT  0 56.592 0.192 56.616 ;
    END
  END di[326]
  PIN di[327]
    DIRECTION INPUT ;
    USE SIGNAL ;
    PORT
      LAYER M4 ;
        RECT  0 56.736 0.192 56.76 ;
    END
  END di[327]
  PIN di[328]
    DIRECTION INPUT ;
    USE SIGNAL ;
    PORT
      LAYER M4 ;
        RECT  0 56.88 0.192 56.904 ;
    END
  END di[328]
  PIN di[329]
    DIRECTION INPUT ;
    USE SIGNAL ;
    PORT
      LAYER M4 ;
        RECT  0 57.072 0.192 57.096 ;
    END
  END di[329]
  PIN di[32]
    DIRECTION INPUT ;
    USE SIGNAL ;
    PORT
      LAYER M4 ;
        RECT  0 9.552 0.192 9.576 ;
    END
  END di[32]
  PIN di[330]
    DIRECTION INPUT ;
    USE SIGNAL ;
    PORT
      LAYER M4 ;
        RECT  0 57.216 0.192 57.24 ;
    END
  END di[330]
  PIN di[331]
    DIRECTION INPUT ;
    USE SIGNAL ;
    PORT
      LAYER M4 ;
        RECT  0 57.36 0.192 57.384 ;
    END
  END di[331]
  PIN di[332]
    DIRECTION INPUT ;
    USE SIGNAL ;
    PORT
      LAYER M4 ;
        RECT  0 57.552 0.192 57.576 ;
    END
  END di[332]
  PIN di[333]
    DIRECTION INPUT ;
    USE SIGNAL ;
    PORT
      LAYER M4 ;
        RECT  0 57.696 0.192 57.72 ;
    END
  END di[333]
  PIN di[334]
    DIRECTION INPUT ;
    USE SIGNAL ;
    PORT
      LAYER M4 ;
        RECT  0 57.84 0.192 57.864 ;
    END
  END di[334]
  PIN di[335]
    DIRECTION INPUT ;
    USE SIGNAL ;
    PORT
      LAYER M4 ;
        RECT  0 58.032 0.192 58.056 ;
    END
  END di[335]
  PIN di[336]
    DIRECTION INPUT ;
    USE SIGNAL ;
    PORT
      LAYER M4 ;
        RECT  0 58.176 0.192 58.2 ;
    END
  END di[336]
  PIN di[337]
    DIRECTION INPUT ;
    USE SIGNAL ;
    PORT
      LAYER M4 ;
        RECT  0 58.32 0.192 58.344 ;
    END
  END di[337]
  PIN di[338]
    DIRECTION INPUT ;
    USE SIGNAL ;
    PORT
      LAYER M4 ;
        RECT  0 58.512 0.192 58.536 ;
    END
  END di[338]
  PIN di[339]
    DIRECTION INPUT ;
    USE SIGNAL ;
    PORT
      LAYER M4 ;
        RECT  0 58.656 0.192 58.68 ;
    END
  END di[339]
  PIN di[33]
    DIRECTION INPUT ;
    USE SIGNAL ;
    PORT
      LAYER M4 ;
        RECT  0 9.696 0.192 9.72 ;
    END
  END di[33]
  PIN di[340]
    DIRECTION INPUT ;
    USE SIGNAL ;
    PORT
      LAYER M4 ;
        RECT  0 58.8 0.192 58.824 ;
    END
  END di[340]
  PIN di[341]
    DIRECTION INPUT ;
    USE SIGNAL ;
    PORT
      LAYER M4 ;
        RECT  0 58.992 0.192 59.016 ;
    END
  END di[341]
  PIN di[342]
    DIRECTION INPUT ;
    USE SIGNAL ;
    PORT
      LAYER M4 ;
        RECT  0 59.136 0.192 59.16 ;
    END
  END di[342]
  PIN di[343]
    DIRECTION INPUT ;
    USE SIGNAL ;
    PORT
      LAYER M4 ;
        RECT  0 59.28 0.192 59.304 ;
    END
  END di[343]
  PIN di[344]
    DIRECTION INPUT ;
    USE SIGNAL ;
    PORT
      LAYER M4 ;
        RECT  0 59.472 0.192 59.496 ;
    END
  END di[344]
  PIN di[345]
    DIRECTION INPUT ;
    USE SIGNAL ;
    PORT
      LAYER M4 ;
        RECT  0 59.616 0.192 59.64 ;
    END
  END di[345]
  PIN di[346]
    DIRECTION INPUT ;
    USE SIGNAL ;
    PORT
      LAYER M4 ;
        RECT  0 59.76 0.192 59.784 ;
    END
  END di[346]
  PIN di[347]
    DIRECTION INPUT ;
    USE SIGNAL ;
    PORT
      LAYER M4 ;
        RECT  0 59.952 0.192 59.976 ;
    END
  END di[347]
  PIN di[348]
    DIRECTION INPUT ;
    USE SIGNAL ;
    PORT
      LAYER M4 ;
        RECT  0 60.096 0.192 60.12 ;
    END
  END di[348]
  PIN di[349]
    DIRECTION INPUT ;
    USE SIGNAL ;
    PORT
      LAYER M4 ;
        RECT  0 60.24 0.192 60.264 ;
    END
  END di[349]
  PIN di[34]
    DIRECTION INPUT ;
    USE SIGNAL ;
    PORT
      LAYER M4 ;
        RECT  0 9.84 0.192 9.864 ;
    END
  END di[34]
  PIN di[350]
    DIRECTION INPUT ;
    USE SIGNAL ;
    PORT
      LAYER M4 ;
        RECT  0 60.432 0.192 60.456 ;
    END
  END di[350]
  PIN di[351]
    DIRECTION INPUT ;
    USE SIGNAL ;
    PORT
      LAYER M4 ;
        RECT  0 60.576 0.192 60.6 ;
    END
  END di[351]
  PIN di[352]
    DIRECTION INPUT ;
    USE SIGNAL ;
    PORT
      LAYER M4 ;
        RECT  0 60.72 0.192 60.744 ;
    END
  END di[352]
  PIN di[353]
    DIRECTION INPUT ;
    USE SIGNAL ;
    PORT
      LAYER M4 ;
        RECT  0 60.912 0.192 60.936 ;
    END
  END di[353]
  PIN di[354]
    DIRECTION INPUT ;
    USE SIGNAL ;
    PORT
      LAYER M4 ;
        RECT  0 61.056 0.192 61.08 ;
    END
  END di[354]
  PIN di[355]
    DIRECTION INPUT ;
    USE SIGNAL ;
    PORT
      LAYER M4 ;
        RECT  0 61.2 0.192 61.224 ;
    END
  END di[355]
  PIN di[356]
    DIRECTION INPUT ;
    USE SIGNAL ;
    PORT
      LAYER M4 ;
        RECT  0 61.392 0.192 61.416 ;
    END
  END di[356]
  PIN di[357]
    DIRECTION INPUT ;
    USE SIGNAL ;
    PORT
      LAYER M4 ;
        RECT  0 61.536 0.192 61.56 ;
    END
  END di[357]
  PIN di[358]
    DIRECTION INPUT ;
    USE SIGNAL ;
    PORT
      LAYER M4 ;
        RECT  0 61.68 0.192 61.704 ;
    END
  END di[358]
  PIN di[359]
    DIRECTION INPUT ;
    USE SIGNAL ;
    PORT
      LAYER M4 ;
        RECT  0 61.872 0.192 61.896 ;
    END
  END di[359]
  PIN di[35]
    DIRECTION INPUT ;
    USE SIGNAL ;
    PORT
      LAYER M4 ;
        RECT  0 10.032 0.192 10.056 ;
    END
  END di[35]
  PIN di[360]
    DIRECTION INPUT ;
    USE SIGNAL ;
    PORT
      LAYER M4 ;
        RECT  0 62.016 0.192 62.04 ;
    END
  END di[360]
  PIN di[361]
    DIRECTION INPUT ;
    USE SIGNAL ;
    PORT
      LAYER M4 ;
        RECT  0 62.16 0.192 62.184 ;
    END
  END di[361]
  PIN di[362]
    DIRECTION INPUT ;
    USE SIGNAL ;
    PORT
      LAYER M4 ;
        RECT  0 62.352 0.192 62.376 ;
    END
  END di[362]
  PIN di[363]
    DIRECTION INPUT ;
    USE SIGNAL ;
    PORT
      LAYER M4 ;
        RECT  0 62.496 0.192 62.52 ;
    END
  END di[363]
  PIN di[364]
    DIRECTION INPUT ;
    USE SIGNAL ;
    PORT
      LAYER M4 ;
        RECT  0 62.64 0.192 62.664 ;
    END
  END di[364]
  PIN di[365]
    DIRECTION INPUT ;
    USE SIGNAL ;
    PORT
      LAYER M4 ;
        RECT  0 62.832 0.192 62.856 ;
    END
  END di[365]
  PIN di[366]
    DIRECTION INPUT ;
    USE SIGNAL ;
    PORT
      LAYER M4 ;
        RECT  0 62.976 0.192 63 ;
    END
  END di[366]
  PIN di[367]
    DIRECTION INPUT ;
    USE SIGNAL ;
    PORT
      LAYER M4 ;
        RECT  0 63.12 0.192 63.144 ;
    END
  END di[367]
  PIN di[368]
    DIRECTION INPUT ;
    USE SIGNAL ;
    PORT
      LAYER M4 ;
        RECT  0 63.312 0.192 63.336 ;
    END
  END di[368]
  PIN di[369]
    DIRECTION INPUT ;
    USE SIGNAL ;
    PORT
      LAYER M4 ;
        RECT  0 63.456 0.192 63.48 ;
    END
  END di[369]
  PIN di[36]
    DIRECTION INPUT ;
    USE SIGNAL ;
    PORT
      LAYER M4 ;
        RECT  0 10.176 0.192 10.2 ;
    END
  END di[36]
  PIN di[370]
    DIRECTION INPUT ;
    USE SIGNAL ;
    PORT
      LAYER M4 ;
        RECT  0 63.6 0.192 63.624 ;
    END
  END di[370]
  PIN di[371]
    DIRECTION INPUT ;
    USE SIGNAL ;
    PORT
      LAYER M4 ;
        RECT  0 63.792 0.192 63.816 ;
    END
  END di[371]
  PIN di[372]
    DIRECTION INPUT ;
    USE SIGNAL ;
    PORT
      LAYER M4 ;
        RECT  0 63.936 0.192 63.96 ;
    END
  END di[372]
  PIN di[373]
    DIRECTION INPUT ;
    USE SIGNAL ;
    PORT
      LAYER M4 ;
        RECT  0 64.08 0.192 64.104 ;
    END
  END di[373]
  PIN di[374]
    DIRECTION INPUT ;
    USE SIGNAL ;
    PORT
      LAYER M4 ;
        RECT  0 64.272 0.192 64.296 ;
    END
  END di[374]
  PIN di[375]
    DIRECTION INPUT ;
    USE SIGNAL ;
    PORT
      LAYER M4 ;
        RECT  0 64.416 0.192 64.44 ;
    END
  END di[375]
  PIN di[376]
    DIRECTION INPUT ;
    USE SIGNAL ;
    PORT
      LAYER M4 ;
        RECT  0 64.56 0.192 64.584 ;
    END
  END di[376]
  PIN di[377]
    DIRECTION INPUT ;
    USE SIGNAL ;
    PORT
      LAYER M4 ;
        RECT  0 64.752 0.192 64.776 ;
    END
  END di[377]
  PIN di[378]
    DIRECTION INPUT ;
    USE SIGNAL ;
    PORT
      LAYER M4 ;
        RECT  0 64.896 0.192 64.92 ;
    END
  END di[378]
  PIN di[379]
    DIRECTION INPUT ;
    USE SIGNAL ;
    PORT
      LAYER M4 ;
        RECT  0 65.04 0.192 65.064 ;
    END
  END di[379]
  PIN di[37]
    DIRECTION INPUT ;
    USE SIGNAL ;
    PORT
      LAYER M4 ;
        RECT  0 10.32 0.192 10.344 ;
    END
  END di[37]
  PIN di[380]
    DIRECTION INPUT ;
    USE SIGNAL ;
    PORT
      LAYER M4 ;
        RECT  0 65.232 0.192 65.256 ;
    END
  END di[380]
  PIN di[381]
    DIRECTION INPUT ;
    USE SIGNAL ;
    PORT
      LAYER M4 ;
        RECT  0 65.376 0.192 65.4 ;
    END
  END di[381]
  PIN di[382]
    DIRECTION INPUT ;
    USE SIGNAL ;
    PORT
      LAYER M4 ;
        RECT  0 65.52 0.192 65.544 ;
    END
  END di[382]
  PIN di[383]
    DIRECTION INPUT ;
    USE SIGNAL ;
    PORT
      LAYER M4 ;
        RECT  0 65.712 0.192 65.736 ;
    END
  END di[383]
  PIN di[384]
    DIRECTION INPUT ;
    USE SIGNAL ;
    PORT
      LAYER M4 ;
        RECT  0 65.856 0.192 65.88 ;
    END
  END di[384]
  PIN di[385]
    DIRECTION INPUT ;
    USE SIGNAL ;
    PORT
      LAYER M4 ;
        RECT  0 66 0.192 66.024 ;
    END
  END di[385]
  PIN di[386]
    DIRECTION INPUT ;
    USE SIGNAL ;
    PORT
      LAYER M4 ;
        RECT  0 66.192 0.192 66.216 ;
    END
  END di[386]
  PIN di[387]
    DIRECTION INPUT ;
    USE SIGNAL ;
    PORT
      LAYER M4 ;
        RECT  0 66.336 0.192 66.36 ;
    END
  END di[387]
  PIN di[388]
    DIRECTION INPUT ;
    USE SIGNAL ;
    PORT
      LAYER M4 ;
        RECT  0 66.48 0.192 66.504 ;
    END
  END di[388]
  PIN di[389]
    DIRECTION INPUT ;
    USE SIGNAL ;
    PORT
      LAYER M4 ;
        RECT  0 66.672 0.192 66.696 ;
    END
  END di[389]
  PIN di[38]
    DIRECTION INPUT ;
    USE SIGNAL ;
    PORT
      LAYER M4 ;
        RECT  0 10.512 0.192 10.536 ;
    END
  END di[38]
  PIN di[390]
    DIRECTION INPUT ;
    USE SIGNAL ;
    PORT
      LAYER M4 ;
        RECT  0 66.816 0.192 66.84 ;
    END
  END di[390]
  PIN di[391]
    DIRECTION INPUT ;
    USE SIGNAL ;
    PORT
      LAYER M4 ;
        RECT  0 66.96 0.192 66.984 ;
    END
  END di[391]
  PIN di[392]
    DIRECTION INPUT ;
    USE SIGNAL ;
    PORT
      LAYER M4 ;
        RECT  0 67.152 0.192 67.176 ;
    END
  END di[392]
  PIN di[393]
    DIRECTION INPUT ;
    USE SIGNAL ;
    PORT
      LAYER M4 ;
        RECT  0 67.296 0.192 67.32 ;
    END
  END di[393]
  PIN di[394]
    DIRECTION INPUT ;
    USE SIGNAL ;
    PORT
      LAYER M4 ;
        RECT  0 67.44 0.192 67.464 ;
    END
  END di[394]
  PIN di[395]
    DIRECTION INPUT ;
    USE SIGNAL ;
    PORT
      LAYER M4 ;
        RECT  0 67.632 0.192 67.656 ;
    END
  END di[395]
  PIN di[396]
    DIRECTION INPUT ;
    USE SIGNAL ;
    PORT
      LAYER M4 ;
        RECT  0 67.776 0.192 67.8 ;
    END
  END di[396]
  PIN di[397]
    DIRECTION INPUT ;
    USE SIGNAL ;
    PORT
      LAYER M4 ;
        RECT  0 67.92 0.192 67.944 ;
    END
  END di[397]
  PIN di[398]
    DIRECTION INPUT ;
    USE SIGNAL ;
    PORT
      LAYER M4 ;
        RECT  0 68.112 0.192 68.136 ;
    END
  END di[398]
  PIN di[399]
    DIRECTION INPUT ;
    USE SIGNAL ;
    PORT
      LAYER M4 ;
        RECT  0 68.256 0.192 68.28 ;
    END
  END di[399]
  PIN di[39]
    DIRECTION INPUT ;
    USE SIGNAL ;
    PORT
      LAYER M4 ;
        RECT  0 10.656 0.192 10.68 ;
    END
  END di[39]
  PIN di[3]
    DIRECTION INPUT ;
    USE SIGNAL ;
    PORT
      LAYER M4 ;
        RECT  0 4.896 0.192 4.92 ;
    END
  END di[3]
  PIN di[400]
    DIRECTION INPUT ;
    USE SIGNAL ;
    PORT
      LAYER M4 ;
        RECT  0 68.4 0.192 68.424 ;
    END
  END di[400]
  PIN di[401]
    DIRECTION INPUT ;
    USE SIGNAL ;
    PORT
      LAYER M4 ;
        RECT  0 68.592 0.192 68.616 ;
    END
  END di[401]
  PIN di[402]
    DIRECTION INPUT ;
    USE SIGNAL ;
    PORT
      LAYER M4 ;
        RECT  0 68.736 0.192 68.76 ;
    END
  END di[402]
  PIN di[403]
    DIRECTION INPUT ;
    USE SIGNAL ;
    PORT
      LAYER M4 ;
        RECT  0 68.88 0.192 68.904 ;
    END
  END di[403]
  PIN di[404]
    DIRECTION INPUT ;
    USE SIGNAL ;
    PORT
      LAYER M4 ;
        RECT  0 69.072 0.192 69.096 ;
    END
  END di[404]
  PIN di[405]
    DIRECTION INPUT ;
    USE SIGNAL ;
    PORT
      LAYER M4 ;
        RECT  0 69.216 0.192 69.24 ;
    END
  END di[405]
  PIN di[406]
    DIRECTION INPUT ;
    USE SIGNAL ;
    PORT
      LAYER M4 ;
        RECT  0 69.36 0.192 69.384 ;
    END
  END di[406]
  PIN di[407]
    DIRECTION INPUT ;
    USE SIGNAL ;
    PORT
      LAYER M4 ;
        RECT  0 69.552 0.192 69.576 ;
    END
  END di[407]
  PIN di[408]
    DIRECTION INPUT ;
    USE SIGNAL ;
    PORT
      LAYER M4 ;
        RECT  0 69.696 0.192 69.72 ;
    END
  END di[408]
  PIN di[409]
    DIRECTION INPUT ;
    USE SIGNAL ;
    PORT
      LAYER M4 ;
        RECT  0 69.84 0.192 69.864 ;
    END
  END di[409]
  PIN di[40]
    DIRECTION INPUT ;
    USE SIGNAL ;
    PORT
      LAYER M4 ;
        RECT  0 10.8 0.192 10.824 ;
    END
  END di[40]
  PIN di[410]
    DIRECTION INPUT ;
    USE SIGNAL ;
    PORT
      LAYER M4 ;
        RECT  0 70.032 0.192 70.056 ;
    END
  END di[410]
  PIN di[411]
    DIRECTION INPUT ;
    USE SIGNAL ;
    PORT
      LAYER M4 ;
        RECT  0 70.176 0.192 70.2 ;
    END
  END di[411]
  PIN di[412]
    DIRECTION INPUT ;
    USE SIGNAL ;
    PORT
      LAYER M4 ;
        RECT  0 70.32 0.192 70.344 ;
    END
  END di[412]
  PIN di[413]
    DIRECTION INPUT ;
    USE SIGNAL ;
    PORT
      LAYER M4 ;
        RECT  0 70.512 0.192 70.536 ;
    END
  END di[413]
  PIN di[414]
    DIRECTION INPUT ;
    USE SIGNAL ;
    PORT
      LAYER M4 ;
        RECT  0 70.656 0.192 70.68 ;
    END
  END di[414]
  PIN di[415]
    DIRECTION INPUT ;
    USE SIGNAL ;
    PORT
      LAYER M4 ;
        RECT  0 70.8 0.192 70.824 ;
    END
  END di[415]
  PIN di[416]
    DIRECTION INPUT ;
    USE SIGNAL ;
    PORT
      LAYER M4 ;
        RECT  0 70.992 0.192 71.016 ;
    END
  END di[416]
  PIN di[417]
    DIRECTION INPUT ;
    USE SIGNAL ;
    PORT
      LAYER M4 ;
        RECT  0 71.136 0.192 71.16 ;
    END
  END di[417]
  PIN di[418]
    DIRECTION INPUT ;
    USE SIGNAL ;
    PORT
      LAYER M4 ;
        RECT  0 71.28 0.192 71.304 ;
    END
  END di[418]
  PIN di[419]
    DIRECTION INPUT ;
    USE SIGNAL ;
    PORT
      LAYER M4 ;
        RECT  0 71.472 0.192 71.496 ;
    END
  END di[419]
  PIN di[41]
    DIRECTION INPUT ;
    USE SIGNAL ;
    PORT
      LAYER M4 ;
        RECT  0 10.992 0.192 11.016 ;
    END
  END di[41]
  PIN di[420]
    DIRECTION INPUT ;
    USE SIGNAL ;
    PORT
      LAYER M4 ;
        RECT  0 71.616 0.192 71.64 ;
    END
  END di[420]
  PIN di[421]
    DIRECTION INPUT ;
    USE SIGNAL ;
    PORT
      LAYER M4 ;
        RECT  0 71.76 0.192 71.784 ;
    END
  END di[421]
  PIN di[422]
    DIRECTION INPUT ;
    USE SIGNAL ;
    PORT
      LAYER M4 ;
        RECT  0 71.952 0.192 71.976 ;
    END
  END di[422]
  PIN di[423]
    DIRECTION INPUT ;
    USE SIGNAL ;
    PORT
      LAYER M4 ;
        RECT  0 72.096 0.192 72.12 ;
    END
  END di[423]
  PIN di[424]
    DIRECTION INPUT ;
    USE SIGNAL ;
    PORT
      LAYER M4 ;
        RECT  0 72.24 0.192 72.264 ;
    END
  END di[424]
  PIN di[425]
    DIRECTION INPUT ;
    USE SIGNAL ;
    PORT
      LAYER M4 ;
        RECT  0 72.432 0.192 72.456 ;
    END
  END di[425]
  PIN di[426]
    DIRECTION INPUT ;
    USE SIGNAL ;
    PORT
      LAYER M4 ;
        RECT  0 72.576 0.192 72.6 ;
    END
  END di[426]
  PIN di[427]
    DIRECTION INPUT ;
    USE SIGNAL ;
    PORT
      LAYER M4 ;
        RECT  0 72.72 0.192 72.744 ;
    END
  END di[427]
  PIN di[428]
    DIRECTION INPUT ;
    USE SIGNAL ;
    PORT
      LAYER M4 ;
        RECT  0 72.912 0.192 72.936 ;
    END
  END di[428]
  PIN di[429]
    DIRECTION INPUT ;
    USE SIGNAL ;
    PORT
      LAYER M4 ;
        RECT  0 73.056 0.192 73.08 ;
    END
  END di[429]
  PIN di[42]
    DIRECTION INPUT ;
    USE SIGNAL ;
    PORT
      LAYER M4 ;
        RECT  0 11.136 0.192 11.16 ;
    END
  END di[42]
  PIN di[430]
    DIRECTION INPUT ;
    USE SIGNAL ;
    PORT
      LAYER M4 ;
        RECT  0 73.2 0.192 73.224 ;
    END
  END di[430]
  PIN di[431]
    DIRECTION INPUT ;
    USE SIGNAL ;
    PORT
      LAYER M4 ;
        RECT  0 73.392 0.192 73.416 ;
    END
  END di[431]
  PIN di[432]
    DIRECTION INPUT ;
    USE SIGNAL ;
    PORT
      LAYER M4 ;
        RECT  0 73.536 0.192 73.56 ;
    END
  END di[432]
  PIN di[433]
    DIRECTION INPUT ;
    USE SIGNAL ;
    PORT
      LAYER M4 ;
        RECT  0 73.68 0.192 73.704 ;
    END
  END di[433]
  PIN di[434]
    DIRECTION INPUT ;
    USE SIGNAL ;
    PORT
      LAYER M4 ;
        RECT  0 73.872 0.192 73.896 ;
    END
  END di[434]
  PIN di[435]
    DIRECTION INPUT ;
    USE SIGNAL ;
    PORT
      LAYER M4 ;
        RECT  0 74.016 0.192 74.04 ;
    END
  END di[435]
  PIN di[436]
    DIRECTION INPUT ;
    USE SIGNAL ;
    PORT
      LAYER M4 ;
        RECT  0 74.16 0.192 74.184 ;
    END
  END di[436]
  PIN di[437]
    DIRECTION INPUT ;
    USE SIGNAL ;
    PORT
      LAYER M4 ;
        RECT  0 74.352 0.192 74.376 ;
    END
  END di[437]
  PIN di[438]
    DIRECTION INPUT ;
    USE SIGNAL ;
    PORT
      LAYER M4 ;
        RECT  0 74.496 0.192 74.52 ;
    END
  END di[438]
  PIN di[439]
    DIRECTION INPUT ;
    USE SIGNAL ;
    PORT
      LAYER M4 ;
        RECT  0 74.64 0.192 74.664 ;
    END
  END di[439]
  PIN di[43]
    DIRECTION INPUT ;
    USE SIGNAL ;
    PORT
      LAYER M4 ;
        RECT  0 11.28 0.192 11.304 ;
    END
  END di[43]
  PIN di[440]
    DIRECTION INPUT ;
    USE SIGNAL ;
    PORT
      LAYER M4 ;
        RECT  0 74.832 0.192 74.856 ;
    END
  END di[440]
  PIN di[441]
    DIRECTION INPUT ;
    USE SIGNAL ;
    PORT
      LAYER M4 ;
        RECT  0 74.976 0.192 75 ;
    END
  END di[441]
  PIN di[442]
    DIRECTION INPUT ;
    USE SIGNAL ;
    PORT
      LAYER M4 ;
        RECT  0 75.12 0.192 75.144 ;
    END
  END di[442]
  PIN di[443]
    DIRECTION INPUT ;
    USE SIGNAL ;
    PORT
      LAYER M4 ;
        RECT  0 75.312 0.192 75.336 ;
    END
  END di[443]
  PIN di[444]
    DIRECTION INPUT ;
    USE SIGNAL ;
    PORT
      LAYER M4 ;
        RECT  0 75.456 0.192 75.48 ;
    END
  END di[444]
  PIN di[445]
    DIRECTION INPUT ;
    USE SIGNAL ;
    PORT
      LAYER M4 ;
        RECT  0 75.6 0.192 75.624 ;
    END
  END di[445]
  PIN di[446]
    DIRECTION INPUT ;
    USE SIGNAL ;
    PORT
      LAYER M4 ;
        RECT  0 75.792 0.192 75.816 ;
    END
  END di[446]
  PIN di[447]
    DIRECTION INPUT ;
    USE SIGNAL ;
    PORT
      LAYER M4 ;
        RECT  0 75.936 0.192 75.96 ;
    END
  END di[447]
  PIN di[448]
    DIRECTION INPUT ;
    USE SIGNAL ;
    PORT
      LAYER M4 ;
        RECT  0 76.08 0.192 76.104 ;
    END
  END di[448]
  PIN di[449]
    DIRECTION INPUT ;
    USE SIGNAL ;
    PORT
      LAYER M4 ;
        RECT  0 76.272 0.192 76.296 ;
    END
  END di[449]
  PIN di[44]
    DIRECTION INPUT ;
    USE SIGNAL ;
    PORT
      LAYER M4 ;
        RECT  0 11.472 0.192 11.496 ;
    END
  END di[44]
  PIN di[450]
    DIRECTION INPUT ;
    USE SIGNAL ;
    PORT
      LAYER M4 ;
        RECT  0 76.416 0.192 76.44 ;
    END
  END di[450]
  PIN di[451]
    DIRECTION INPUT ;
    USE SIGNAL ;
    PORT
      LAYER M4 ;
        RECT  0 76.56 0.192 76.584 ;
    END
  END di[451]
  PIN di[452]
    DIRECTION INPUT ;
    USE SIGNAL ;
    PORT
      LAYER M4 ;
        RECT  0 76.752 0.192 76.776 ;
    END
  END di[452]
  PIN di[453]
    DIRECTION INPUT ;
    USE SIGNAL ;
    PORT
      LAYER M4 ;
        RECT  0 76.896 0.192 76.92 ;
    END
  END di[453]
  PIN di[454]
    DIRECTION INPUT ;
    USE SIGNAL ;
    PORT
      LAYER M4 ;
        RECT  0 77.04 0.192 77.064 ;
    END
  END di[454]
  PIN di[455]
    DIRECTION INPUT ;
    USE SIGNAL ;
    PORT
      LAYER M4 ;
        RECT  0 77.232 0.192 77.256 ;
    END
  END di[455]
  PIN di[456]
    DIRECTION INPUT ;
    USE SIGNAL ;
    PORT
      LAYER M4 ;
        RECT  0 77.376 0.192 77.4 ;
    END
  END di[456]
  PIN di[457]
    DIRECTION INPUT ;
    USE SIGNAL ;
    PORT
      LAYER M4 ;
        RECT  0 77.52 0.192 77.544 ;
    END
  END di[457]
  PIN di[458]
    DIRECTION INPUT ;
    USE SIGNAL ;
    PORT
      LAYER M4 ;
        RECT  0 77.712 0.192 77.736 ;
    END
  END di[458]
  PIN di[459]
    DIRECTION INPUT ;
    USE SIGNAL ;
    PORT
      LAYER M4 ;
        RECT  0 77.856 0.192 77.88 ;
    END
  END di[459]
  PIN di[45]
    DIRECTION INPUT ;
    USE SIGNAL ;
    PORT
      LAYER M4 ;
        RECT  0 11.616 0.192 11.64 ;
    END
  END di[45]
  PIN di[460]
    DIRECTION INPUT ;
    USE SIGNAL ;
    PORT
      LAYER M4 ;
        RECT  0 78 0.192 78.024 ;
    END
  END di[460]
  PIN di[461]
    DIRECTION INPUT ;
    USE SIGNAL ;
    PORT
      LAYER M4 ;
        RECT  0 78.192 0.192 78.216 ;
    END
  END di[461]
  PIN di[462]
    DIRECTION INPUT ;
    USE SIGNAL ;
    PORT
      LAYER M4 ;
        RECT  0 78.336 0.192 78.36 ;
    END
  END di[462]
  PIN di[463]
    DIRECTION INPUT ;
    USE SIGNAL ;
    PORT
      LAYER M4 ;
        RECT  0 78.48 0.192 78.504 ;
    END
  END di[463]
  PIN di[464]
    DIRECTION INPUT ;
    USE SIGNAL ;
    PORT
      LAYER M4 ;
        RECT  0 78.672 0.192 78.696 ;
    END
  END di[464]
  PIN di[465]
    DIRECTION INPUT ;
    USE SIGNAL ;
    PORT
      LAYER M4 ;
        RECT  0 78.816 0.192 78.84 ;
    END
  END di[465]
  PIN di[466]
    DIRECTION INPUT ;
    USE SIGNAL ;
    PORT
      LAYER M4 ;
        RECT  0 78.96 0.192 78.984 ;
    END
  END di[466]
  PIN di[467]
    DIRECTION INPUT ;
    USE SIGNAL ;
    PORT
      LAYER M4 ;
        RECT  0 79.152 0.192 79.176 ;
    END
  END di[467]
  PIN di[468]
    DIRECTION INPUT ;
    USE SIGNAL ;
    PORT
      LAYER M4 ;
        RECT  0 79.296 0.192 79.32 ;
    END
  END di[468]
  PIN di[469]
    DIRECTION INPUT ;
    USE SIGNAL ;
    PORT
      LAYER M4 ;
        RECT  0 79.44 0.192 79.464 ;
    END
  END di[469]
  PIN di[46]
    DIRECTION INPUT ;
    USE SIGNAL ;
    PORT
      LAYER M4 ;
        RECT  0 11.76 0.192 11.784 ;
    END
  END di[46]
  PIN di[470]
    DIRECTION INPUT ;
    USE SIGNAL ;
    PORT
      LAYER M4 ;
        RECT  0 79.632 0.192 79.656 ;
    END
  END di[470]
  PIN di[471]
    DIRECTION INPUT ;
    USE SIGNAL ;
    PORT
      LAYER M4 ;
        RECT  0 79.776 0.192 79.8 ;
    END
  END di[471]
  PIN di[472]
    DIRECTION INPUT ;
    USE SIGNAL ;
    PORT
      LAYER M4 ;
        RECT  0 79.92 0.192 79.944 ;
    END
  END di[472]
  PIN di[473]
    DIRECTION INPUT ;
    USE SIGNAL ;
    PORT
      LAYER M4 ;
        RECT  0 80.112 0.192 80.136 ;
    END
  END di[473]
  PIN di[474]
    DIRECTION INPUT ;
    USE SIGNAL ;
    PORT
      LAYER M4 ;
        RECT  0 80.256 0.192 80.28 ;
    END
  END di[474]
  PIN di[475]
    DIRECTION INPUT ;
    USE SIGNAL ;
    PORT
      LAYER M4 ;
        RECT  0 80.4 0.192 80.424 ;
    END
  END di[475]
  PIN di[476]
    DIRECTION INPUT ;
    USE SIGNAL ;
    PORT
      LAYER M4 ;
        RECT  0 80.592 0.192 80.616 ;
    END
  END di[476]
  PIN di[477]
    DIRECTION INPUT ;
    USE SIGNAL ;
    PORT
      LAYER M4 ;
        RECT  0 80.736 0.192 80.76 ;
    END
  END di[477]
  PIN di[478]
    DIRECTION INPUT ;
    USE SIGNAL ;
    PORT
      LAYER M4 ;
        RECT  0 80.88 0.192 80.904 ;
    END
  END di[478]
  PIN di[479]
    DIRECTION INPUT ;
    USE SIGNAL ;
    PORT
      LAYER M4 ;
        RECT  0 81.072 0.192 81.096 ;
    END
  END di[479]
  PIN di[47]
    DIRECTION INPUT ;
    USE SIGNAL ;
    PORT
      LAYER M4 ;
        RECT  0 11.952 0.192 11.976 ;
    END
  END di[47]
  PIN di[480]
    DIRECTION INPUT ;
    USE SIGNAL ;
    PORT
      LAYER M4 ;
        RECT  0 81.216 0.192 81.24 ;
    END
  END di[480]
  PIN di[481]
    DIRECTION INPUT ;
    USE SIGNAL ;
    PORT
      LAYER M4 ;
        RECT  0 81.36 0.192 81.384 ;
    END
  END di[481]
  PIN di[482]
    DIRECTION INPUT ;
    USE SIGNAL ;
    PORT
      LAYER M4 ;
        RECT  0 81.552 0.192 81.576 ;
    END
  END di[482]
  PIN di[483]
    DIRECTION INPUT ;
    USE SIGNAL ;
    PORT
      LAYER M4 ;
        RECT  0 81.696 0.192 81.72 ;
    END
  END di[483]
  PIN di[484]
    DIRECTION INPUT ;
    USE SIGNAL ;
    PORT
      LAYER M4 ;
        RECT  0 81.84 0.192 81.864 ;
    END
  END di[484]
  PIN di[485]
    DIRECTION INPUT ;
    USE SIGNAL ;
    PORT
      LAYER M4 ;
        RECT  0 82.032 0.192 82.056 ;
    END
  END di[485]
  PIN di[486]
    DIRECTION INPUT ;
    USE SIGNAL ;
    PORT
      LAYER M4 ;
        RECT  0 82.176 0.192 82.2 ;
    END
  END di[486]
  PIN di[487]
    DIRECTION INPUT ;
    USE SIGNAL ;
    PORT
      LAYER M4 ;
        RECT  0 82.32 0.192 82.344 ;
    END
  END di[487]
  PIN di[488]
    DIRECTION INPUT ;
    USE SIGNAL ;
    PORT
      LAYER M4 ;
        RECT  0 82.512 0.192 82.536 ;
    END
  END di[488]
  PIN di[489]
    DIRECTION INPUT ;
    USE SIGNAL ;
    PORT
      LAYER M4 ;
        RECT  0 82.656 0.192 82.68 ;
    END
  END di[489]
  PIN di[48]
    DIRECTION INPUT ;
    USE SIGNAL ;
    PORT
      LAYER M4 ;
        RECT  0 12.096 0.192 12.12 ;
    END
  END di[48]
  PIN di[490]
    DIRECTION INPUT ;
    USE SIGNAL ;
    PORT
      LAYER M4 ;
        RECT  0 82.8 0.192 82.824 ;
    END
  END di[490]
  PIN di[491]
    DIRECTION INPUT ;
    USE SIGNAL ;
    PORT
      LAYER M4 ;
        RECT  0 82.992 0.192 83.016 ;
    END
  END di[491]
  PIN di[492]
    DIRECTION INPUT ;
    USE SIGNAL ;
    PORT
      LAYER M4 ;
        RECT  0 83.136 0.192 83.16 ;
    END
  END di[492]
  PIN di[493]
    DIRECTION INPUT ;
    USE SIGNAL ;
    PORT
      LAYER M4 ;
        RECT  0 83.28 0.192 83.304 ;
    END
  END di[493]
  PIN di[494]
    DIRECTION INPUT ;
    USE SIGNAL ;
    PORT
      LAYER M4 ;
        RECT  0 83.472 0.192 83.496 ;
    END
  END di[494]
  PIN di[495]
    DIRECTION INPUT ;
    USE SIGNAL ;
    PORT
      LAYER M4 ;
        RECT  0 83.616 0.192 83.64 ;
    END
  END di[495]
  PIN di[496]
    DIRECTION INPUT ;
    USE SIGNAL ;
    PORT
      LAYER M4 ;
        RECT  0 83.76 0.192 83.784 ;
    END
  END di[496]
  PIN di[497]
    DIRECTION INPUT ;
    USE SIGNAL ;
    PORT
      LAYER M4 ;
        RECT  0 83.952 0.192 83.976 ;
    END
  END di[497]
  PIN di[498]
    DIRECTION INPUT ;
    USE SIGNAL ;
    PORT
      LAYER M4 ;
        RECT  0 84.096 0.192 84.12 ;
    END
  END di[498]
  PIN di[499]
    DIRECTION INPUT ;
    USE SIGNAL ;
    PORT
      LAYER M4 ;
        RECT  0 84.24 0.192 84.264 ;
    END
  END di[499]
  PIN di[49]
    DIRECTION INPUT ;
    USE SIGNAL ;
    PORT
      LAYER M4 ;
        RECT  0 12.24 0.192 12.264 ;
    END
  END di[49]
  PIN di[4]
    DIRECTION INPUT ;
    USE SIGNAL ;
    PORT
      LAYER M4 ;
        RECT  0 5.04 0.192 5.064 ;
    END
  END di[4]
  PIN di[500]
    DIRECTION INPUT ;
    USE SIGNAL ;
    PORT
      LAYER M4 ;
        RECT  0 84.432 0.192 84.456 ;
    END
  END di[500]
  PIN di[501]
    DIRECTION INPUT ;
    USE SIGNAL ;
    PORT
      LAYER M4 ;
        RECT  0 84.576 0.192 84.6 ;
    END
  END di[501]
  PIN di[502]
    DIRECTION INPUT ;
    USE SIGNAL ;
    PORT
      LAYER M4 ;
        RECT  0 84.72 0.192 84.744 ;
    END
  END di[502]
  PIN di[503]
    DIRECTION INPUT ;
    USE SIGNAL ;
    PORT
      LAYER M4 ;
        RECT  0 84.912 0.192 84.936 ;
    END
  END di[503]
  PIN di[504]
    DIRECTION INPUT ;
    USE SIGNAL ;
    PORT
      LAYER M4 ;
        RECT  0 85.056 0.192 85.08 ;
    END
  END di[504]
  PIN di[505]
    DIRECTION INPUT ;
    USE SIGNAL ;
    PORT
      LAYER M4 ;
        RECT  0 85.2 0.192 85.224 ;
    END
  END di[505]
  PIN di[506]
    DIRECTION INPUT ;
    USE SIGNAL ;
    PORT
      LAYER M4 ;
        RECT  0 85.392 0.192 85.416 ;
    END
  END di[506]
  PIN di[507]
    DIRECTION INPUT ;
    USE SIGNAL ;
    PORT
      LAYER M4 ;
        RECT  0 85.536 0.192 85.56 ;
    END
  END di[507]
  PIN di[508]
    DIRECTION INPUT ;
    USE SIGNAL ;
    PORT
      LAYER M4 ;
        RECT  0 85.68 0.192 85.704 ;
    END
  END di[508]
  PIN di[509]
    DIRECTION INPUT ;
    USE SIGNAL ;
    PORT
      LAYER M4 ;
        RECT  0 85.872 0.192 85.896 ;
    END
  END di[509]
  PIN di[50]
    DIRECTION INPUT ;
    USE SIGNAL ;
    PORT
      LAYER M4 ;
        RECT  0 12.432 0.192 12.456 ;
    END
  END di[50]
  PIN di[510]
    DIRECTION INPUT ;
    USE SIGNAL ;
    PORT
      LAYER M4 ;
        RECT  0 86.016 0.192 86.04 ;
    END
  END di[510]
  PIN di[511]
    DIRECTION INPUT ;
    USE SIGNAL ;
    PORT
      LAYER M4 ;
        RECT  0 86.16 0.192 86.184 ;
    END
  END di[511]
  PIN di[512]
    DIRECTION INPUT ;
    USE SIGNAL ;
    PORT
      LAYER M4 ;
        RECT  0 86.352 0.192 86.376 ;
    END
  END di[512]
  PIN di[51]
    DIRECTION INPUT ;
    USE SIGNAL ;
    PORT
      LAYER M4 ;
        RECT  0 12.576 0.192 12.6 ;
    END
  END di[51]
  PIN di[52]
    DIRECTION INPUT ;
    USE SIGNAL ;
    PORT
      LAYER M4 ;
        RECT  0 12.72 0.192 12.744 ;
    END
  END di[52]
  PIN di[53]
    DIRECTION INPUT ;
    USE SIGNAL ;
    PORT
      LAYER M4 ;
        RECT  0 12.912 0.192 12.936 ;
    END
  END di[53]
  PIN di[54]
    DIRECTION INPUT ;
    USE SIGNAL ;
    PORT
      LAYER M4 ;
        RECT  0 13.056 0.192 13.08 ;
    END
  END di[54]
  PIN di[55]
    DIRECTION INPUT ;
    USE SIGNAL ;
    PORT
      LAYER M4 ;
        RECT  0 13.2 0.192 13.224 ;
    END
  END di[55]
  PIN di[56]
    DIRECTION INPUT ;
    USE SIGNAL ;
    PORT
      LAYER M4 ;
        RECT  0 13.392 0.192 13.416 ;
    END
  END di[56]
  PIN di[57]
    DIRECTION INPUT ;
    USE SIGNAL ;
    PORT
      LAYER M4 ;
        RECT  0 13.536 0.192 13.56 ;
    END
  END di[57]
  PIN di[58]
    DIRECTION INPUT ;
    USE SIGNAL ;
    PORT
      LAYER M4 ;
        RECT  0 13.68 0.192 13.704 ;
    END
  END di[58]
  PIN di[59]
    DIRECTION INPUT ;
    USE SIGNAL ;
    PORT
      LAYER M4 ;
        RECT  0 13.872 0.192 13.896 ;
    END
  END di[59]
  PIN di[5]
    DIRECTION INPUT ;
    USE SIGNAL ;
    PORT
      LAYER M4 ;
        RECT  0 5.232 0.192 5.256 ;
    END
  END di[5]
  PIN di[60]
    DIRECTION INPUT ;
    USE SIGNAL ;
    PORT
      LAYER M4 ;
        RECT  0 14.016 0.192 14.04 ;
    END
  END di[60]
  PIN di[61]
    DIRECTION INPUT ;
    USE SIGNAL ;
    PORT
      LAYER M4 ;
        RECT  0 14.16 0.192 14.184 ;
    END
  END di[61]
  PIN di[62]
    DIRECTION INPUT ;
    USE SIGNAL ;
    PORT
      LAYER M4 ;
        RECT  0 14.352 0.192 14.376 ;
    END
  END di[62]
  PIN di[63]
    DIRECTION INPUT ;
    USE SIGNAL ;
    PORT
      LAYER M4 ;
        RECT  0 14.496 0.192 14.52 ;
    END
  END di[63]
  PIN di[64]
    DIRECTION INPUT ;
    USE SIGNAL ;
    PORT
      LAYER M4 ;
        RECT  0 14.64 0.192 14.664 ;
    END
  END di[64]
  PIN di[65]
    DIRECTION INPUT ;
    USE SIGNAL ;
    PORT
      LAYER M4 ;
        RECT  0 14.832 0.192 14.856 ;
    END
  END di[65]
  PIN di[66]
    DIRECTION INPUT ;
    USE SIGNAL ;
    PORT
      LAYER M4 ;
        RECT  0 14.976 0.192 15 ;
    END
  END di[66]
  PIN di[67]
    DIRECTION INPUT ;
    USE SIGNAL ;
    PORT
      LAYER M4 ;
        RECT  0 15.12 0.192 15.144 ;
    END
  END di[67]
  PIN di[68]
    DIRECTION INPUT ;
    USE SIGNAL ;
    PORT
      LAYER M4 ;
        RECT  0 15.312 0.192 15.336 ;
    END
  END di[68]
  PIN di[69]
    DIRECTION INPUT ;
    USE SIGNAL ;
    PORT
      LAYER M4 ;
        RECT  0 15.456 0.192 15.48 ;
    END
  END di[69]
  PIN di[6]
    DIRECTION INPUT ;
    USE SIGNAL ;
    PORT
      LAYER M4 ;
        RECT  0 5.376 0.192 5.4 ;
    END
  END di[6]
  PIN di[70]
    DIRECTION INPUT ;
    USE SIGNAL ;
    PORT
      LAYER M4 ;
        RECT  0 15.6 0.192 15.624 ;
    END
  END di[70]
  PIN di[71]
    DIRECTION INPUT ;
    USE SIGNAL ;
    PORT
      LAYER M4 ;
        RECT  0 15.792 0.192 15.816 ;
    END
  END di[71]
  PIN di[72]
    DIRECTION INPUT ;
    USE SIGNAL ;
    PORT
      LAYER M4 ;
        RECT  0 15.936 0.192 15.96 ;
    END
  END di[72]
  PIN di[73]
    DIRECTION INPUT ;
    USE SIGNAL ;
    PORT
      LAYER M4 ;
        RECT  0 16.08 0.192 16.104 ;
    END
  END di[73]
  PIN di[74]
    DIRECTION INPUT ;
    USE SIGNAL ;
    PORT
      LAYER M4 ;
        RECT  0 16.272 0.192 16.296 ;
    END
  END di[74]
  PIN di[75]
    DIRECTION INPUT ;
    USE SIGNAL ;
    PORT
      LAYER M4 ;
        RECT  0 16.416 0.192 16.44 ;
    END
  END di[75]
  PIN di[76]
    DIRECTION INPUT ;
    USE SIGNAL ;
    PORT
      LAYER M4 ;
        RECT  0 16.56 0.192 16.584 ;
    END
  END di[76]
  PIN di[77]
    DIRECTION INPUT ;
    USE SIGNAL ;
    PORT
      LAYER M4 ;
        RECT  0 16.752 0.192 16.776 ;
    END
  END di[77]
  PIN di[78]
    DIRECTION INPUT ;
    USE SIGNAL ;
    PORT
      LAYER M4 ;
        RECT  0 16.896 0.192 16.92 ;
    END
  END di[78]
  PIN di[79]
    DIRECTION INPUT ;
    USE SIGNAL ;
    PORT
      LAYER M4 ;
        RECT  0 17.04 0.192 17.064 ;
    END
  END di[79]
  PIN di[7]
    DIRECTION INPUT ;
    USE SIGNAL ;
    PORT
      LAYER M4 ;
        RECT  0 5.52 0.192 5.544 ;
    END
  END di[7]
  PIN di[80]
    DIRECTION INPUT ;
    USE SIGNAL ;
    PORT
      LAYER M4 ;
        RECT  0 17.232 0.192 17.256 ;
    END
  END di[80]
  PIN di[81]
    DIRECTION INPUT ;
    USE SIGNAL ;
    PORT
      LAYER M4 ;
        RECT  0 17.376 0.192 17.4 ;
    END
  END di[81]
  PIN di[82]
    DIRECTION INPUT ;
    USE SIGNAL ;
    PORT
      LAYER M4 ;
        RECT  0 17.52 0.192 17.544 ;
    END
  END di[82]
  PIN di[83]
    DIRECTION INPUT ;
    USE SIGNAL ;
    PORT
      LAYER M4 ;
        RECT  0 17.712 0.192 17.736 ;
    END
  END di[83]
  PIN di[84]
    DIRECTION INPUT ;
    USE SIGNAL ;
    PORT
      LAYER M4 ;
        RECT  0 17.856 0.192 17.88 ;
    END
  END di[84]
  PIN di[85]
    DIRECTION INPUT ;
    USE SIGNAL ;
    PORT
      LAYER M4 ;
        RECT  0 18 0.192 18.024 ;
    END
  END di[85]
  PIN di[86]
    DIRECTION INPUT ;
    USE SIGNAL ;
    PORT
      LAYER M4 ;
        RECT  0 18.192 0.192 18.216 ;
    END
  END di[86]
  PIN di[87]
    DIRECTION INPUT ;
    USE SIGNAL ;
    PORT
      LAYER M4 ;
        RECT  0 18.336 0.192 18.36 ;
    END
  END di[87]
  PIN di[88]
    DIRECTION INPUT ;
    USE SIGNAL ;
    PORT
      LAYER M4 ;
        RECT  0 18.48 0.192 18.504 ;
    END
  END di[88]
  PIN di[89]
    DIRECTION INPUT ;
    USE SIGNAL ;
    PORT
      LAYER M4 ;
        RECT  0 18.672 0.192 18.696 ;
    END
  END di[89]
  PIN di[8]
    DIRECTION INPUT ;
    USE SIGNAL ;
    PORT
      LAYER M4 ;
        RECT  0 5.712 0.192 5.736 ;
    END
  END di[8]
  PIN di[90]
    DIRECTION INPUT ;
    USE SIGNAL ;
    PORT
      LAYER M4 ;
        RECT  0 18.816 0.192 18.84 ;
    END
  END di[90]
  PIN di[91]
    DIRECTION INPUT ;
    USE SIGNAL ;
    PORT
      LAYER M4 ;
        RECT  0 18.96 0.192 18.984 ;
    END
  END di[91]
  PIN di[92]
    DIRECTION INPUT ;
    USE SIGNAL ;
    PORT
      LAYER M4 ;
        RECT  0 19.152 0.192 19.176 ;
    END
  END di[92]
  PIN di[93]
    DIRECTION INPUT ;
    USE SIGNAL ;
    PORT
      LAYER M4 ;
        RECT  0 19.296 0.192 19.32 ;
    END
  END di[93]
  PIN di[94]
    DIRECTION INPUT ;
    USE SIGNAL ;
    PORT
      LAYER M4 ;
        RECT  0 19.44 0.192 19.464 ;
    END
  END di[94]
  PIN di[95]
    DIRECTION INPUT ;
    USE SIGNAL ;
    PORT
      LAYER M4 ;
        RECT  0 19.632 0.192 19.656 ;
    END
  END di[95]
  PIN di[96]
    DIRECTION INPUT ;
    USE SIGNAL ;
    PORT
      LAYER M4 ;
        RECT  0 19.776 0.192 19.8 ;
    END
  END di[96]
  PIN di[97]
    DIRECTION INPUT ;
    USE SIGNAL ;
    PORT
      LAYER M4 ;
        RECT  0 19.92 0.192 19.944 ;
    END
  END di[97]
  PIN di[98]
    DIRECTION INPUT ;
    USE SIGNAL ;
    PORT
      LAYER M4 ;
        RECT  0 20.112 0.192 20.136 ;
    END
  END di[98]
  PIN di[99]
    DIRECTION INPUT ;
    USE SIGNAL ;
    PORT
      LAYER M4 ;
        RECT  0 20.256 0.192 20.28 ;
    END
  END di[99]
  PIN di[9]
    DIRECTION INPUT ;
    USE SIGNAL ;
    PORT
      LAYER M4 ;
        RECT  0 5.856 0.192 5.88 ;
    END
  END di[9]
  PIN dq[0]
    DIRECTION OUTPUT ;
    USE SIGNAL ;
    PORT
      LAYER M4 ;
        RECT  36.528 4.416 36.72 4.44 ;
    END
  END dq[0]
  PIN dq[100]
    DIRECTION OUTPUT ;
    USE SIGNAL ;
    PORT
      LAYER M4 ;
        RECT  36.528 20.4 36.72 20.424 ;
    END
  END dq[100]
  PIN dq[101]
    DIRECTION OUTPUT ;
    USE SIGNAL ;
    PORT
      LAYER M4 ;
        RECT  36.528 20.592 36.72 20.616 ;
    END
  END dq[101]
  PIN dq[102]
    DIRECTION OUTPUT ;
    USE SIGNAL ;
    PORT
      LAYER M4 ;
        RECT  36.528 20.736 36.72 20.76 ;
    END
  END dq[102]
  PIN dq[103]
    DIRECTION OUTPUT ;
    USE SIGNAL ;
    PORT
      LAYER M4 ;
        RECT  36.528 20.88 36.72 20.904 ;
    END
  END dq[103]
  PIN dq[104]
    DIRECTION OUTPUT ;
    USE SIGNAL ;
    PORT
      LAYER M4 ;
        RECT  36.528 21.072 36.72 21.096 ;
    END
  END dq[104]
  PIN dq[105]
    DIRECTION OUTPUT ;
    USE SIGNAL ;
    PORT
      LAYER M4 ;
        RECT  36.528 21.216 36.72 21.24 ;
    END
  END dq[105]
  PIN dq[106]
    DIRECTION OUTPUT ;
    USE SIGNAL ;
    PORT
      LAYER M4 ;
        RECT  36.528 21.36 36.72 21.384 ;
    END
  END dq[106]
  PIN dq[107]
    DIRECTION OUTPUT ;
    USE SIGNAL ;
    PORT
      LAYER M4 ;
        RECT  36.528 21.552 36.72 21.576 ;
    END
  END dq[107]
  PIN dq[108]
    DIRECTION OUTPUT ;
    USE SIGNAL ;
    PORT
      LAYER M4 ;
        RECT  36.528 21.696 36.72 21.72 ;
    END
  END dq[108]
  PIN dq[109]
    DIRECTION OUTPUT ;
    USE SIGNAL ;
    PORT
      LAYER M4 ;
        RECT  36.528 21.84 36.72 21.864 ;
    END
  END dq[109]
  PIN dq[10]
    DIRECTION OUTPUT ;
    USE SIGNAL ;
    PORT
      LAYER M4 ;
        RECT  36.528 6 36.72 6.024 ;
    END
  END dq[10]
  PIN dq[110]
    DIRECTION OUTPUT ;
    USE SIGNAL ;
    PORT
      LAYER M4 ;
        RECT  36.528 22.032 36.72 22.056 ;
    END
  END dq[110]
  PIN dq[111]
    DIRECTION OUTPUT ;
    USE SIGNAL ;
    PORT
      LAYER M4 ;
        RECT  36.528 22.176 36.72 22.2 ;
    END
  END dq[111]
  PIN dq[112]
    DIRECTION OUTPUT ;
    USE SIGNAL ;
    PORT
      LAYER M4 ;
        RECT  36.528 22.32 36.72 22.344 ;
    END
  END dq[112]
  PIN dq[113]
    DIRECTION OUTPUT ;
    USE SIGNAL ;
    PORT
      LAYER M4 ;
        RECT  36.528 22.512 36.72 22.536 ;
    END
  END dq[113]
  PIN dq[114]
    DIRECTION OUTPUT ;
    USE SIGNAL ;
    PORT
      LAYER M4 ;
        RECT  36.528 22.656 36.72 22.68 ;
    END
  END dq[114]
  PIN dq[115]
    DIRECTION OUTPUT ;
    USE SIGNAL ;
    PORT
      LAYER M4 ;
        RECT  36.528 22.8 36.72 22.824 ;
    END
  END dq[115]
  PIN dq[116]
    DIRECTION OUTPUT ;
    USE SIGNAL ;
    PORT
      LAYER M4 ;
        RECT  36.528 22.992 36.72 23.016 ;
    END
  END dq[116]
  PIN dq[117]
    DIRECTION OUTPUT ;
    USE SIGNAL ;
    PORT
      LAYER M4 ;
        RECT  36.528 23.136 36.72 23.16 ;
    END
  END dq[117]
  PIN dq[118]
    DIRECTION OUTPUT ;
    USE SIGNAL ;
    PORT
      LAYER M4 ;
        RECT  36.528 23.28 36.72 23.304 ;
    END
  END dq[118]
  PIN dq[119]
    DIRECTION OUTPUT ;
    USE SIGNAL ;
    PORT
      LAYER M4 ;
        RECT  36.528 23.472 36.72 23.496 ;
    END
  END dq[119]
  PIN dq[11]
    DIRECTION OUTPUT ;
    USE SIGNAL ;
    PORT
      LAYER M4 ;
        RECT  36.528 6.192 36.72 6.216 ;
    END
  END dq[11]
  PIN dq[120]
    DIRECTION OUTPUT ;
    USE SIGNAL ;
    PORT
      LAYER M4 ;
        RECT  36.528 23.616 36.72 23.64 ;
    END
  END dq[120]
  PIN dq[121]
    DIRECTION OUTPUT ;
    USE SIGNAL ;
    PORT
      LAYER M4 ;
        RECT  36.528 23.76 36.72 23.784 ;
    END
  END dq[121]
  PIN dq[122]
    DIRECTION OUTPUT ;
    USE SIGNAL ;
    PORT
      LAYER M4 ;
        RECT  36.528 23.952 36.72 23.976 ;
    END
  END dq[122]
  PIN dq[123]
    DIRECTION OUTPUT ;
    USE SIGNAL ;
    PORT
      LAYER M4 ;
        RECT  36.528 24.096 36.72 24.12 ;
    END
  END dq[123]
  PIN dq[124]
    DIRECTION OUTPUT ;
    USE SIGNAL ;
    PORT
      LAYER M4 ;
        RECT  36.528 24.24 36.72 24.264 ;
    END
  END dq[124]
  PIN dq[125]
    DIRECTION OUTPUT ;
    USE SIGNAL ;
    PORT
      LAYER M4 ;
        RECT  36.528 24.432 36.72 24.456 ;
    END
  END dq[125]
  PIN dq[126]
    DIRECTION OUTPUT ;
    USE SIGNAL ;
    PORT
      LAYER M4 ;
        RECT  36.528 24.576 36.72 24.6 ;
    END
  END dq[126]
  PIN dq[127]
    DIRECTION OUTPUT ;
    USE SIGNAL ;
    PORT
      LAYER M4 ;
        RECT  36.528 24.72 36.72 24.744 ;
    END
  END dq[127]
  PIN dq[128]
    DIRECTION OUTPUT ;
    USE SIGNAL ;
    PORT
      LAYER M4 ;
        RECT  36.528 24.912 36.72 24.936 ;
    END
  END dq[128]
  PIN dq[129]
    DIRECTION OUTPUT ;
    USE SIGNAL ;
    PORT
      LAYER M4 ;
        RECT  36.528 25.056 36.72 25.08 ;
    END
  END dq[129]
  PIN dq[12]
    DIRECTION OUTPUT ;
    USE SIGNAL ;
    PORT
      LAYER M4 ;
        RECT  36.528 6.336 36.72 6.36 ;
    END
  END dq[12]
  PIN dq[130]
    DIRECTION OUTPUT ;
    USE SIGNAL ;
    PORT
      LAYER M4 ;
        RECT  36.528 25.2 36.72 25.224 ;
    END
  END dq[130]
  PIN dq[131]
    DIRECTION OUTPUT ;
    USE SIGNAL ;
    PORT
      LAYER M4 ;
        RECT  36.528 25.392 36.72 25.416 ;
    END
  END dq[131]
  PIN dq[132]
    DIRECTION OUTPUT ;
    USE SIGNAL ;
    PORT
      LAYER M4 ;
        RECT  36.528 25.536 36.72 25.56 ;
    END
  END dq[132]
  PIN dq[133]
    DIRECTION OUTPUT ;
    USE SIGNAL ;
    PORT
      LAYER M4 ;
        RECT  36.528 25.68 36.72 25.704 ;
    END
  END dq[133]
  PIN dq[134]
    DIRECTION OUTPUT ;
    USE SIGNAL ;
    PORT
      LAYER M4 ;
        RECT  36.528 25.872 36.72 25.896 ;
    END
  END dq[134]
  PIN dq[135]
    DIRECTION OUTPUT ;
    USE SIGNAL ;
    PORT
      LAYER M4 ;
        RECT  36.528 26.016 36.72 26.04 ;
    END
  END dq[135]
  PIN dq[136]
    DIRECTION OUTPUT ;
    USE SIGNAL ;
    PORT
      LAYER M4 ;
        RECT  36.528 26.16 36.72 26.184 ;
    END
  END dq[136]
  PIN dq[137]
    DIRECTION OUTPUT ;
    USE SIGNAL ;
    PORT
      LAYER M4 ;
        RECT  36.528 26.352 36.72 26.376 ;
    END
  END dq[137]
  PIN dq[138]
    DIRECTION OUTPUT ;
    USE SIGNAL ;
    PORT
      LAYER M4 ;
        RECT  36.528 26.496 36.72 26.52 ;
    END
  END dq[138]
  PIN dq[139]
    DIRECTION OUTPUT ;
    USE SIGNAL ;
    PORT
      LAYER M4 ;
        RECT  36.528 26.64 36.72 26.664 ;
    END
  END dq[139]
  PIN dq[13]
    DIRECTION OUTPUT ;
    USE SIGNAL ;
    PORT
      LAYER M4 ;
        RECT  36.528 6.48 36.72 6.504 ;
    END
  END dq[13]
  PIN dq[140]
    DIRECTION OUTPUT ;
    USE SIGNAL ;
    PORT
      LAYER M4 ;
        RECT  36.528 26.832 36.72 26.856 ;
    END
  END dq[140]
  PIN dq[141]
    DIRECTION OUTPUT ;
    USE SIGNAL ;
    PORT
      LAYER M4 ;
        RECT  36.528 26.976 36.72 27 ;
    END
  END dq[141]
  PIN dq[142]
    DIRECTION OUTPUT ;
    USE SIGNAL ;
    PORT
      LAYER M4 ;
        RECT  36.528 27.12 36.72 27.144 ;
    END
  END dq[142]
  PIN dq[143]
    DIRECTION OUTPUT ;
    USE SIGNAL ;
    PORT
      LAYER M4 ;
        RECT  36.528 27.312 36.72 27.336 ;
    END
  END dq[143]
  PIN dq[144]
    DIRECTION OUTPUT ;
    USE SIGNAL ;
    PORT
      LAYER M4 ;
        RECT  36.528 27.456 36.72 27.48 ;
    END
  END dq[144]
  PIN dq[145]
    DIRECTION OUTPUT ;
    USE SIGNAL ;
    PORT
      LAYER M4 ;
        RECT  36.528 27.6 36.72 27.624 ;
    END
  END dq[145]
  PIN dq[146]
    DIRECTION OUTPUT ;
    USE SIGNAL ;
    PORT
      LAYER M4 ;
        RECT  36.528 27.792 36.72 27.816 ;
    END
  END dq[146]
  PIN dq[147]
    DIRECTION OUTPUT ;
    USE SIGNAL ;
    PORT
      LAYER M4 ;
        RECT  36.528 27.936 36.72 27.96 ;
    END
  END dq[147]
  PIN dq[148]
    DIRECTION OUTPUT ;
    USE SIGNAL ;
    PORT
      LAYER M4 ;
        RECT  36.528 28.08 36.72 28.104 ;
    END
  END dq[148]
  PIN dq[149]
    DIRECTION OUTPUT ;
    USE SIGNAL ;
    PORT
      LAYER M4 ;
        RECT  36.528 28.272 36.72 28.296 ;
    END
  END dq[149]
  PIN dq[14]
    DIRECTION OUTPUT ;
    USE SIGNAL ;
    PORT
      LAYER M4 ;
        RECT  36.528 6.672 36.72 6.696 ;
    END
  END dq[14]
  PIN dq[150]
    DIRECTION OUTPUT ;
    USE SIGNAL ;
    PORT
      LAYER M4 ;
        RECT  36.528 28.416 36.72 28.44 ;
    END
  END dq[150]
  PIN dq[151]
    DIRECTION OUTPUT ;
    USE SIGNAL ;
    PORT
      LAYER M4 ;
        RECT  36.528 28.56 36.72 28.584 ;
    END
  END dq[151]
  PIN dq[152]
    DIRECTION OUTPUT ;
    USE SIGNAL ;
    PORT
      LAYER M4 ;
        RECT  36.528 28.752 36.72 28.776 ;
    END
  END dq[152]
  PIN dq[153]
    DIRECTION OUTPUT ;
    USE SIGNAL ;
    PORT
      LAYER M4 ;
        RECT  36.528 28.896 36.72 28.92 ;
    END
  END dq[153]
  PIN dq[154]
    DIRECTION OUTPUT ;
    USE SIGNAL ;
    PORT
      LAYER M4 ;
        RECT  36.528 29.04 36.72 29.064 ;
    END
  END dq[154]
  PIN dq[155]
    DIRECTION OUTPUT ;
    USE SIGNAL ;
    PORT
      LAYER M4 ;
        RECT  36.528 29.232 36.72 29.256 ;
    END
  END dq[155]
  PIN dq[156]
    DIRECTION OUTPUT ;
    USE SIGNAL ;
    PORT
      LAYER M4 ;
        RECT  36.528 29.376 36.72 29.4 ;
    END
  END dq[156]
  PIN dq[157]
    DIRECTION OUTPUT ;
    USE SIGNAL ;
    PORT
      LAYER M4 ;
        RECT  36.528 29.52 36.72 29.544 ;
    END
  END dq[157]
  PIN dq[158]
    DIRECTION OUTPUT ;
    USE SIGNAL ;
    PORT
      LAYER M4 ;
        RECT  36.528 29.712 36.72 29.736 ;
    END
  END dq[158]
  PIN dq[159]
    DIRECTION OUTPUT ;
    USE SIGNAL ;
    PORT
      LAYER M4 ;
        RECT  36.528 29.856 36.72 29.88 ;
    END
  END dq[159]
  PIN dq[15]
    DIRECTION OUTPUT ;
    USE SIGNAL ;
    PORT
      LAYER M4 ;
        RECT  36.528 6.816 36.72 6.84 ;
    END
  END dq[15]
  PIN dq[160]
    DIRECTION OUTPUT ;
    USE SIGNAL ;
    PORT
      LAYER M4 ;
        RECT  36.528 30 36.72 30.024 ;
    END
  END dq[160]
  PIN dq[161]
    DIRECTION OUTPUT ;
    USE SIGNAL ;
    PORT
      LAYER M4 ;
        RECT  36.528 30.192 36.72 30.216 ;
    END
  END dq[161]
  PIN dq[162]
    DIRECTION OUTPUT ;
    USE SIGNAL ;
    PORT
      LAYER M4 ;
        RECT  36.528 30.336 36.72 30.36 ;
    END
  END dq[162]
  PIN dq[163]
    DIRECTION OUTPUT ;
    USE SIGNAL ;
    PORT
      LAYER M4 ;
        RECT  36.528 30.48 36.72 30.504 ;
    END
  END dq[163]
  PIN dq[164]
    DIRECTION OUTPUT ;
    USE SIGNAL ;
    PORT
      LAYER M4 ;
        RECT  36.528 30.672 36.72 30.696 ;
    END
  END dq[164]
  PIN dq[165]
    DIRECTION OUTPUT ;
    USE SIGNAL ;
    PORT
      LAYER M4 ;
        RECT  36.528 30.816 36.72 30.84 ;
    END
  END dq[165]
  PIN dq[166]
    DIRECTION OUTPUT ;
    USE SIGNAL ;
    PORT
      LAYER M4 ;
        RECT  36.528 30.96 36.72 30.984 ;
    END
  END dq[166]
  PIN dq[167]
    DIRECTION OUTPUT ;
    USE SIGNAL ;
    PORT
      LAYER M4 ;
        RECT  36.528 31.152 36.72 31.176 ;
    END
  END dq[167]
  PIN dq[168]
    DIRECTION OUTPUT ;
    USE SIGNAL ;
    PORT
      LAYER M4 ;
        RECT  36.528 31.296 36.72 31.32 ;
    END
  END dq[168]
  PIN dq[169]
    DIRECTION OUTPUT ;
    USE SIGNAL ;
    PORT
      LAYER M4 ;
        RECT  36.528 31.44 36.72 31.464 ;
    END
  END dq[169]
  PIN dq[16]
    DIRECTION OUTPUT ;
    USE SIGNAL ;
    PORT
      LAYER M4 ;
        RECT  36.528 6.96 36.72 6.984 ;
    END
  END dq[16]
  PIN dq[170]
    DIRECTION OUTPUT ;
    USE SIGNAL ;
    PORT
      LAYER M4 ;
        RECT  36.528 31.632 36.72 31.656 ;
    END
  END dq[170]
  PIN dq[171]
    DIRECTION OUTPUT ;
    USE SIGNAL ;
    PORT
      LAYER M4 ;
        RECT  36.528 31.776 36.72 31.8 ;
    END
  END dq[171]
  PIN dq[172]
    DIRECTION OUTPUT ;
    USE SIGNAL ;
    PORT
      LAYER M4 ;
        RECT  36.528 31.92 36.72 31.944 ;
    END
  END dq[172]
  PIN dq[173]
    DIRECTION OUTPUT ;
    USE SIGNAL ;
    PORT
      LAYER M4 ;
        RECT  36.528 32.112 36.72 32.136 ;
    END
  END dq[173]
  PIN dq[174]
    DIRECTION OUTPUT ;
    USE SIGNAL ;
    PORT
      LAYER M4 ;
        RECT  36.528 32.256 36.72 32.28 ;
    END
  END dq[174]
  PIN dq[175]
    DIRECTION OUTPUT ;
    USE SIGNAL ;
    PORT
      LAYER M4 ;
        RECT  36.528 32.4 36.72 32.424 ;
    END
  END dq[175]
  PIN dq[176]
    DIRECTION OUTPUT ;
    USE SIGNAL ;
    PORT
      LAYER M4 ;
        RECT  36.528 32.592 36.72 32.616 ;
    END
  END dq[176]
  PIN dq[177]
    DIRECTION OUTPUT ;
    USE SIGNAL ;
    PORT
      LAYER M4 ;
        RECT  36.528 32.736 36.72 32.76 ;
    END
  END dq[177]
  PIN dq[178]
    DIRECTION OUTPUT ;
    USE SIGNAL ;
    PORT
      LAYER M4 ;
        RECT  36.528 32.88 36.72 32.904 ;
    END
  END dq[178]
  PIN dq[179]
    DIRECTION OUTPUT ;
    USE SIGNAL ;
    PORT
      LAYER M4 ;
        RECT  36.528 33.072 36.72 33.096 ;
    END
  END dq[179]
  PIN dq[17]
    DIRECTION OUTPUT ;
    USE SIGNAL ;
    PORT
      LAYER M4 ;
        RECT  36.528 7.152 36.72 7.176 ;
    END
  END dq[17]
  PIN dq[180]
    DIRECTION OUTPUT ;
    USE SIGNAL ;
    PORT
      LAYER M4 ;
        RECT  36.528 33.216 36.72 33.24 ;
    END
  END dq[180]
  PIN dq[181]
    DIRECTION OUTPUT ;
    USE SIGNAL ;
    PORT
      LAYER M4 ;
        RECT  36.528 33.36 36.72 33.384 ;
    END
  END dq[181]
  PIN dq[182]
    DIRECTION OUTPUT ;
    USE SIGNAL ;
    PORT
      LAYER M4 ;
        RECT  36.528 33.552 36.72 33.576 ;
    END
  END dq[182]
  PIN dq[183]
    DIRECTION OUTPUT ;
    USE SIGNAL ;
    PORT
      LAYER M4 ;
        RECT  36.528 33.696 36.72 33.72 ;
    END
  END dq[183]
  PIN dq[184]
    DIRECTION OUTPUT ;
    USE SIGNAL ;
    PORT
      LAYER M4 ;
        RECT  36.528 33.84 36.72 33.864 ;
    END
  END dq[184]
  PIN dq[185]
    DIRECTION OUTPUT ;
    USE SIGNAL ;
    PORT
      LAYER M4 ;
        RECT  36.528 34.032 36.72 34.056 ;
    END
  END dq[185]
  PIN dq[186]
    DIRECTION OUTPUT ;
    USE SIGNAL ;
    PORT
      LAYER M4 ;
        RECT  36.528 34.176 36.72 34.2 ;
    END
  END dq[186]
  PIN dq[187]
    DIRECTION OUTPUT ;
    USE SIGNAL ;
    PORT
      LAYER M4 ;
        RECT  36.528 34.32 36.72 34.344 ;
    END
  END dq[187]
  PIN dq[188]
    DIRECTION OUTPUT ;
    USE SIGNAL ;
    PORT
      LAYER M4 ;
        RECT  36.528 34.512 36.72 34.536 ;
    END
  END dq[188]
  PIN dq[189]
    DIRECTION OUTPUT ;
    USE SIGNAL ;
    PORT
      LAYER M4 ;
        RECT  36.528 34.656 36.72 34.68 ;
    END
  END dq[189]
  PIN dq[18]
    DIRECTION OUTPUT ;
    USE SIGNAL ;
    PORT
      LAYER M4 ;
        RECT  36.528 7.296 36.72 7.32 ;
    END
  END dq[18]
  PIN dq[190]
    DIRECTION OUTPUT ;
    USE SIGNAL ;
    PORT
      LAYER M4 ;
        RECT  36.528 34.8 36.72 34.824 ;
    END
  END dq[190]
  PIN dq[191]
    DIRECTION OUTPUT ;
    USE SIGNAL ;
    PORT
      LAYER M4 ;
        RECT  36.528 34.992 36.72 35.016 ;
    END
  END dq[191]
  PIN dq[192]
    DIRECTION OUTPUT ;
    USE SIGNAL ;
    PORT
      LAYER M4 ;
        RECT  36.528 35.136 36.72 35.16 ;
    END
  END dq[192]
  PIN dq[193]
    DIRECTION OUTPUT ;
    USE SIGNAL ;
    PORT
      LAYER M4 ;
        RECT  36.528 35.28 36.72 35.304 ;
    END
  END dq[193]
  PIN dq[194]
    DIRECTION OUTPUT ;
    USE SIGNAL ;
    PORT
      LAYER M4 ;
        RECT  36.528 35.472 36.72 35.496 ;
    END
  END dq[194]
  PIN dq[195]
    DIRECTION OUTPUT ;
    USE SIGNAL ;
    PORT
      LAYER M4 ;
        RECT  36.528 35.616 36.72 35.64 ;
    END
  END dq[195]
  PIN dq[196]
    DIRECTION OUTPUT ;
    USE SIGNAL ;
    PORT
      LAYER M4 ;
        RECT  36.528 35.76 36.72 35.784 ;
    END
  END dq[196]
  PIN dq[197]
    DIRECTION OUTPUT ;
    USE SIGNAL ;
    PORT
      LAYER M4 ;
        RECT  36.528 35.952 36.72 35.976 ;
    END
  END dq[197]
  PIN dq[198]
    DIRECTION OUTPUT ;
    USE SIGNAL ;
    PORT
      LAYER M4 ;
        RECT  36.528 36.096 36.72 36.12 ;
    END
  END dq[198]
  PIN dq[199]
    DIRECTION OUTPUT ;
    USE SIGNAL ;
    PORT
      LAYER M4 ;
        RECT  36.528 36.24 36.72 36.264 ;
    END
  END dq[199]
  PIN dq[19]
    DIRECTION OUTPUT ;
    USE SIGNAL ;
    PORT
      LAYER M4 ;
        RECT  36.528 7.44 36.72 7.464 ;
    END
  END dq[19]
  PIN dq[1]
    DIRECTION OUTPUT ;
    USE SIGNAL ;
    PORT
      LAYER M4 ;
        RECT  36.528 4.56 36.72 4.584 ;
    END
  END dq[1]
  PIN dq[200]
    DIRECTION OUTPUT ;
    USE SIGNAL ;
    PORT
      LAYER M4 ;
        RECT  36.528 36.432 36.72 36.456 ;
    END
  END dq[200]
  PIN dq[201]
    DIRECTION OUTPUT ;
    USE SIGNAL ;
    PORT
      LAYER M4 ;
        RECT  36.528 36.576 36.72 36.6 ;
    END
  END dq[201]
  PIN dq[202]
    DIRECTION OUTPUT ;
    USE SIGNAL ;
    PORT
      LAYER M4 ;
        RECT  36.528 36.72 36.72 36.744 ;
    END
  END dq[202]
  PIN dq[203]
    DIRECTION OUTPUT ;
    USE SIGNAL ;
    PORT
      LAYER M4 ;
        RECT  36.528 36.912 36.72 36.936 ;
    END
  END dq[203]
  PIN dq[204]
    DIRECTION OUTPUT ;
    USE SIGNAL ;
    PORT
      LAYER M4 ;
        RECT  36.528 37.056 36.72 37.08 ;
    END
  END dq[204]
  PIN dq[205]
    DIRECTION OUTPUT ;
    USE SIGNAL ;
    PORT
      LAYER M4 ;
        RECT  36.528 37.2 36.72 37.224 ;
    END
  END dq[205]
  PIN dq[206]
    DIRECTION OUTPUT ;
    USE SIGNAL ;
    PORT
      LAYER M4 ;
        RECT  36.528 37.392 36.72 37.416 ;
    END
  END dq[206]
  PIN dq[207]
    DIRECTION OUTPUT ;
    USE SIGNAL ;
    PORT
      LAYER M4 ;
        RECT  36.528 37.536 36.72 37.56 ;
    END
  END dq[207]
  PIN dq[208]
    DIRECTION OUTPUT ;
    USE SIGNAL ;
    PORT
      LAYER M4 ;
        RECT  36.528 37.68 36.72 37.704 ;
    END
  END dq[208]
  PIN dq[209]
    DIRECTION OUTPUT ;
    USE SIGNAL ;
    PORT
      LAYER M4 ;
        RECT  36.528 37.872 36.72 37.896 ;
    END
  END dq[209]
  PIN dq[20]
    DIRECTION OUTPUT ;
    USE SIGNAL ;
    PORT
      LAYER M4 ;
        RECT  36.528 7.632 36.72 7.656 ;
    END
  END dq[20]
  PIN dq[210]
    DIRECTION OUTPUT ;
    USE SIGNAL ;
    PORT
      LAYER M4 ;
        RECT  36.528 38.016 36.72 38.04 ;
    END
  END dq[210]
  PIN dq[211]
    DIRECTION OUTPUT ;
    USE SIGNAL ;
    PORT
      LAYER M4 ;
        RECT  36.528 38.16 36.72 38.184 ;
    END
  END dq[211]
  PIN dq[212]
    DIRECTION OUTPUT ;
    USE SIGNAL ;
    PORT
      LAYER M4 ;
        RECT  36.528 38.352 36.72 38.376 ;
    END
  END dq[212]
  PIN dq[213]
    DIRECTION OUTPUT ;
    USE SIGNAL ;
    PORT
      LAYER M4 ;
        RECT  36.528 38.496 36.72 38.52 ;
    END
  END dq[213]
  PIN dq[214]
    DIRECTION OUTPUT ;
    USE SIGNAL ;
    PORT
      LAYER M4 ;
        RECT  36.528 38.64 36.72 38.664 ;
    END
  END dq[214]
  PIN dq[215]
    DIRECTION OUTPUT ;
    USE SIGNAL ;
    PORT
      LAYER M4 ;
        RECT  36.528 38.832 36.72 38.856 ;
    END
  END dq[215]
  PIN dq[216]
    DIRECTION OUTPUT ;
    USE SIGNAL ;
    PORT
      LAYER M4 ;
        RECT  36.528 38.976 36.72 39 ;
    END
  END dq[216]
  PIN dq[217]
    DIRECTION OUTPUT ;
    USE SIGNAL ;
    PORT
      LAYER M4 ;
        RECT  36.528 39.12 36.72 39.144 ;
    END
  END dq[217]
  PIN dq[218]
    DIRECTION OUTPUT ;
    USE SIGNAL ;
    PORT
      LAYER M4 ;
        RECT  36.528 39.312 36.72 39.336 ;
    END
  END dq[218]
  PIN dq[219]
    DIRECTION OUTPUT ;
    USE SIGNAL ;
    PORT
      LAYER M4 ;
        RECT  36.528 39.456 36.72 39.48 ;
    END
  END dq[219]
  PIN dq[21]
    DIRECTION OUTPUT ;
    USE SIGNAL ;
    PORT
      LAYER M4 ;
        RECT  36.528 7.776 36.72 7.8 ;
    END
  END dq[21]
  PIN dq[220]
    DIRECTION OUTPUT ;
    USE SIGNAL ;
    PORT
      LAYER M4 ;
        RECT  36.528 39.6 36.72 39.624 ;
    END
  END dq[220]
  PIN dq[221]
    DIRECTION OUTPUT ;
    USE SIGNAL ;
    PORT
      LAYER M4 ;
        RECT  36.528 39.792 36.72 39.816 ;
    END
  END dq[221]
  PIN dq[222]
    DIRECTION OUTPUT ;
    USE SIGNAL ;
    PORT
      LAYER M4 ;
        RECT  36.528 39.936 36.72 39.96 ;
    END
  END dq[222]
  PIN dq[223]
    DIRECTION OUTPUT ;
    USE SIGNAL ;
    PORT
      LAYER M4 ;
        RECT  36.528 40.08 36.72 40.104 ;
    END
  END dq[223]
  PIN dq[224]
    DIRECTION OUTPUT ;
    USE SIGNAL ;
    PORT
      LAYER M4 ;
        RECT  36.528 40.272 36.72 40.296 ;
    END
  END dq[224]
  PIN dq[225]
    DIRECTION OUTPUT ;
    USE SIGNAL ;
    PORT
      LAYER M4 ;
        RECT  36.528 40.416 36.72 40.44 ;
    END
  END dq[225]
  PIN dq[226]
    DIRECTION OUTPUT ;
    USE SIGNAL ;
    PORT
      LAYER M4 ;
        RECT  36.528 40.56 36.72 40.584 ;
    END
  END dq[226]
  PIN dq[227]
    DIRECTION OUTPUT ;
    USE SIGNAL ;
    PORT
      LAYER M4 ;
        RECT  36.528 40.752 36.72 40.776 ;
    END
  END dq[227]
  PIN dq[228]
    DIRECTION OUTPUT ;
    USE SIGNAL ;
    PORT
      LAYER M4 ;
        RECT  36.528 40.896 36.72 40.92 ;
    END
  END dq[228]
  PIN dq[229]
    DIRECTION OUTPUT ;
    USE SIGNAL ;
    PORT
      LAYER M4 ;
        RECT  36.528 41.04 36.72 41.064 ;
    END
  END dq[229]
  PIN dq[22]
    DIRECTION OUTPUT ;
    USE SIGNAL ;
    PORT
      LAYER M4 ;
        RECT  36.528 7.92 36.72 7.944 ;
    END
  END dq[22]
  PIN dq[230]
    DIRECTION OUTPUT ;
    USE SIGNAL ;
    PORT
      LAYER M4 ;
        RECT  36.528 41.232 36.72 41.256 ;
    END
  END dq[230]
  PIN dq[231]
    DIRECTION OUTPUT ;
    USE SIGNAL ;
    PORT
      LAYER M4 ;
        RECT  36.528 41.376 36.72 41.4 ;
    END
  END dq[231]
  PIN dq[232]
    DIRECTION OUTPUT ;
    USE SIGNAL ;
    PORT
      LAYER M4 ;
        RECT  36.528 41.52 36.72 41.544 ;
    END
  END dq[232]
  PIN dq[233]
    DIRECTION OUTPUT ;
    USE SIGNAL ;
    PORT
      LAYER M4 ;
        RECT  36.528 41.712 36.72 41.736 ;
    END
  END dq[233]
  PIN dq[234]
    DIRECTION OUTPUT ;
    USE SIGNAL ;
    PORT
      LAYER M4 ;
        RECT  36.528 41.856 36.72 41.88 ;
    END
  END dq[234]
  PIN dq[235]
    DIRECTION OUTPUT ;
    USE SIGNAL ;
    PORT
      LAYER M4 ;
        RECT  36.528 42 36.72 42.024 ;
    END
  END dq[235]
  PIN dq[236]
    DIRECTION OUTPUT ;
    USE SIGNAL ;
    PORT
      LAYER M4 ;
        RECT  36.528 42.192 36.72 42.216 ;
    END
  END dq[236]
  PIN dq[237]
    DIRECTION OUTPUT ;
    USE SIGNAL ;
    PORT
      LAYER M4 ;
        RECT  36.528 42.336 36.72 42.36 ;
    END
  END dq[237]
  PIN dq[238]
    DIRECTION OUTPUT ;
    USE SIGNAL ;
    PORT
      LAYER M4 ;
        RECT  36.528 42.48 36.72 42.504 ;
    END
  END dq[238]
  PIN dq[239]
    DIRECTION OUTPUT ;
    USE SIGNAL ;
    PORT
      LAYER M4 ;
        RECT  36.528 42.672 36.72 42.696 ;
    END
  END dq[239]
  PIN dq[23]
    DIRECTION OUTPUT ;
    USE SIGNAL ;
    PORT
      LAYER M4 ;
        RECT  36.528 8.112 36.72 8.136 ;
    END
  END dq[23]
  PIN dq[240]
    DIRECTION OUTPUT ;
    USE SIGNAL ;
    PORT
      LAYER M4 ;
        RECT  36.528 42.816 36.72 42.84 ;
    END
  END dq[240]
  PIN dq[241]
    DIRECTION OUTPUT ;
    USE SIGNAL ;
    PORT
      LAYER M4 ;
        RECT  36.528 42.96 36.72 42.984 ;
    END
  END dq[241]
  PIN dq[242]
    DIRECTION OUTPUT ;
    USE SIGNAL ;
    PORT
      LAYER M4 ;
        RECT  36.528 43.152 36.72 43.176 ;
    END
  END dq[242]
  PIN dq[243]
    DIRECTION OUTPUT ;
    USE SIGNAL ;
    PORT
      LAYER M4 ;
        RECT  36.528 43.296 36.72 43.32 ;
    END
  END dq[243]
  PIN dq[244]
    DIRECTION OUTPUT ;
    USE SIGNAL ;
    PORT
      LAYER M4 ;
        RECT  36.528 43.44 36.72 43.464 ;
    END
  END dq[244]
  PIN dq[245]
    DIRECTION OUTPUT ;
    USE SIGNAL ;
    PORT
      LAYER M4 ;
        RECT  36.528 43.632 36.72 43.656 ;
    END
  END dq[245]
  PIN dq[246]
    DIRECTION OUTPUT ;
    USE SIGNAL ;
    PORT
      LAYER M4 ;
        RECT  36.528 43.776 36.72 43.8 ;
    END
  END dq[246]
  PIN dq[247]
    DIRECTION OUTPUT ;
    USE SIGNAL ;
    PORT
      LAYER M4 ;
        RECT  36.528 43.92 36.72 43.944 ;
    END
  END dq[247]
  PIN dq[248]
    DIRECTION OUTPUT ;
    USE SIGNAL ;
    PORT
      LAYER M4 ;
        RECT  36.528 44.112 36.72 44.136 ;
    END
  END dq[248]
  PIN dq[249]
    DIRECTION OUTPUT ;
    USE SIGNAL ;
    PORT
      LAYER M4 ;
        RECT  36.528 44.256 36.72 44.28 ;
    END
  END dq[249]
  PIN dq[24]
    DIRECTION OUTPUT ;
    USE SIGNAL ;
    PORT
      LAYER M4 ;
        RECT  36.528 8.256 36.72 8.28 ;
    END
  END dq[24]
  PIN dq[250]
    DIRECTION OUTPUT ;
    USE SIGNAL ;
    PORT
      LAYER M4 ;
        RECT  36.528 44.4 36.72 44.424 ;
    END
  END dq[250]
  PIN dq[251]
    DIRECTION OUTPUT ;
    USE SIGNAL ;
    PORT
      LAYER M4 ;
        RECT  36.528 44.592 36.72 44.616 ;
    END
  END dq[251]
  PIN dq[252]
    DIRECTION OUTPUT ;
    USE SIGNAL ;
    PORT
      LAYER M4 ;
        RECT  36.528 44.736 36.72 44.76 ;
    END
  END dq[252]
  PIN dq[253]
    DIRECTION OUTPUT ;
    USE SIGNAL ;
    PORT
      LAYER M4 ;
        RECT  36.528 44.88 36.72 44.904 ;
    END
  END dq[253]
  PIN dq[254]
    DIRECTION OUTPUT ;
    USE SIGNAL ;
    PORT
      LAYER M4 ;
        RECT  36.528 45.072 36.72 45.096 ;
    END
  END dq[254]
  PIN dq[255]
    DIRECTION OUTPUT ;
    USE SIGNAL ;
    PORT
      LAYER M4 ;
        RECT  36.528 45.216 36.72 45.24 ;
    END
  END dq[255]
  PIN dq[256]
    DIRECTION OUTPUT ;
    USE SIGNAL ;
    PORT
      LAYER M4 ;
        RECT  36.528 45.36 36.72 45.384 ;
    END
  END dq[256]
  PIN dq[257]
    DIRECTION OUTPUT ;
    USE SIGNAL ;
    PORT
      LAYER M4 ;
        RECT  36.528 45.552 36.72 45.576 ;
    END
  END dq[257]
  PIN dq[258]
    DIRECTION OUTPUT ;
    USE SIGNAL ;
    PORT
      LAYER M4 ;
        RECT  36.528 45.696 36.72 45.72 ;
    END
  END dq[258]
  PIN dq[259]
    DIRECTION OUTPUT ;
    USE SIGNAL ;
    PORT
      LAYER M4 ;
        RECT  36.528 45.84 36.72 45.864 ;
    END
  END dq[259]
  PIN dq[25]
    DIRECTION OUTPUT ;
    USE SIGNAL ;
    PORT
      LAYER M4 ;
        RECT  36.528 8.4 36.72 8.424 ;
    END
  END dq[25]
  PIN dq[260]
    DIRECTION OUTPUT ;
    USE SIGNAL ;
    PORT
      LAYER M4 ;
        RECT  36.528 46.032 36.72 46.056 ;
    END
  END dq[260]
  PIN dq[261]
    DIRECTION OUTPUT ;
    USE SIGNAL ;
    PORT
      LAYER M4 ;
        RECT  36.528 46.176 36.72 46.2 ;
    END
  END dq[261]
  PIN dq[262]
    DIRECTION OUTPUT ;
    USE SIGNAL ;
    PORT
      LAYER M4 ;
        RECT  36.528 46.32 36.72 46.344 ;
    END
  END dq[262]
  PIN dq[263]
    DIRECTION OUTPUT ;
    USE SIGNAL ;
    PORT
      LAYER M4 ;
        RECT  36.528 46.512 36.72 46.536 ;
    END
  END dq[263]
  PIN dq[264]
    DIRECTION OUTPUT ;
    USE SIGNAL ;
    PORT
      LAYER M4 ;
        RECT  36.528 46.656 36.72 46.68 ;
    END
  END dq[264]
  PIN dq[265]
    DIRECTION OUTPUT ;
    USE SIGNAL ;
    PORT
      LAYER M4 ;
        RECT  36.528 46.8 36.72 46.824 ;
    END
  END dq[265]
  PIN dq[266]
    DIRECTION OUTPUT ;
    USE SIGNAL ;
    PORT
      LAYER M4 ;
        RECT  36.528 46.992 36.72 47.016 ;
    END
  END dq[266]
  PIN dq[267]
    DIRECTION OUTPUT ;
    USE SIGNAL ;
    PORT
      LAYER M4 ;
        RECT  36.528 47.136 36.72 47.16 ;
    END
  END dq[267]
  PIN dq[268]
    DIRECTION OUTPUT ;
    USE SIGNAL ;
    PORT
      LAYER M4 ;
        RECT  36.528 47.28 36.72 47.304 ;
    END
  END dq[268]
  PIN dq[269]
    DIRECTION OUTPUT ;
    USE SIGNAL ;
    PORT
      LAYER M4 ;
        RECT  36.528 47.472 36.72 47.496 ;
    END
  END dq[269]
  PIN dq[26]
    DIRECTION OUTPUT ;
    USE SIGNAL ;
    PORT
      LAYER M4 ;
        RECT  36.528 8.592 36.72 8.616 ;
    END
  END dq[26]
  PIN dq[270]
    DIRECTION OUTPUT ;
    USE SIGNAL ;
    PORT
      LAYER M4 ;
        RECT  36.528 47.616 36.72 47.64 ;
    END
  END dq[270]
  PIN dq[271]
    DIRECTION OUTPUT ;
    USE SIGNAL ;
    PORT
      LAYER M4 ;
        RECT  36.528 47.76 36.72 47.784 ;
    END
  END dq[271]
  PIN dq[272]
    DIRECTION OUTPUT ;
    USE SIGNAL ;
    PORT
      LAYER M4 ;
        RECT  36.528 47.952 36.72 47.976 ;
    END
  END dq[272]
  PIN dq[273]
    DIRECTION OUTPUT ;
    USE SIGNAL ;
    PORT
      LAYER M4 ;
        RECT  36.528 48.096 36.72 48.12 ;
    END
  END dq[273]
  PIN dq[274]
    DIRECTION OUTPUT ;
    USE SIGNAL ;
    PORT
      LAYER M4 ;
        RECT  36.528 48.24 36.72 48.264 ;
    END
  END dq[274]
  PIN dq[275]
    DIRECTION OUTPUT ;
    USE SIGNAL ;
    PORT
      LAYER M4 ;
        RECT  36.528 48.432 36.72 48.456 ;
    END
  END dq[275]
  PIN dq[276]
    DIRECTION OUTPUT ;
    USE SIGNAL ;
    PORT
      LAYER M4 ;
        RECT  36.528 48.576 36.72 48.6 ;
    END
  END dq[276]
  PIN dq[277]
    DIRECTION OUTPUT ;
    USE SIGNAL ;
    PORT
      LAYER M4 ;
        RECT  36.528 48.72 36.72 48.744 ;
    END
  END dq[277]
  PIN dq[278]
    DIRECTION OUTPUT ;
    USE SIGNAL ;
    PORT
      LAYER M4 ;
        RECT  36.528 48.912 36.72 48.936 ;
    END
  END dq[278]
  PIN dq[279]
    DIRECTION OUTPUT ;
    USE SIGNAL ;
    PORT
      LAYER M4 ;
        RECT  36.528 49.056 36.72 49.08 ;
    END
  END dq[279]
  PIN dq[27]
    DIRECTION OUTPUT ;
    USE SIGNAL ;
    PORT
      LAYER M4 ;
        RECT  36.528 8.736 36.72 8.76 ;
    END
  END dq[27]
  PIN dq[280]
    DIRECTION OUTPUT ;
    USE SIGNAL ;
    PORT
      LAYER M4 ;
        RECT  36.528 49.2 36.72 49.224 ;
    END
  END dq[280]
  PIN dq[281]
    DIRECTION OUTPUT ;
    USE SIGNAL ;
    PORT
      LAYER M4 ;
        RECT  36.528 49.392 36.72 49.416 ;
    END
  END dq[281]
  PIN dq[282]
    DIRECTION OUTPUT ;
    USE SIGNAL ;
    PORT
      LAYER M4 ;
        RECT  36.528 49.536 36.72 49.56 ;
    END
  END dq[282]
  PIN dq[283]
    DIRECTION OUTPUT ;
    USE SIGNAL ;
    PORT
      LAYER M4 ;
        RECT  36.528 49.68 36.72 49.704 ;
    END
  END dq[283]
  PIN dq[284]
    DIRECTION OUTPUT ;
    USE SIGNAL ;
    PORT
      LAYER M4 ;
        RECT  36.528 49.872 36.72 49.896 ;
    END
  END dq[284]
  PIN dq[285]
    DIRECTION OUTPUT ;
    USE SIGNAL ;
    PORT
      LAYER M4 ;
        RECT  36.528 50.016 36.72 50.04 ;
    END
  END dq[285]
  PIN dq[286]
    DIRECTION OUTPUT ;
    USE SIGNAL ;
    PORT
      LAYER M4 ;
        RECT  36.528 50.16 36.72 50.184 ;
    END
  END dq[286]
  PIN dq[287]
    DIRECTION OUTPUT ;
    USE SIGNAL ;
    PORT
      LAYER M4 ;
        RECT  36.528 50.352 36.72 50.376 ;
    END
  END dq[287]
  PIN dq[288]
    DIRECTION OUTPUT ;
    USE SIGNAL ;
    PORT
      LAYER M4 ;
        RECT  36.528 50.496 36.72 50.52 ;
    END
  END dq[288]
  PIN dq[289]
    DIRECTION OUTPUT ;
    USE SIGNAL ;
    PORT
      LAYER M4 ;
        RECT  36.528 50.64 36.72 50.664 ;
    END
  END dq[289]
  PIN dq[28]
    DIRECTION OUTPUT ;
    USE SIGNAL ;
    PORT
      LAYER M4 ;
        RECT  36.528 8.88 36.72 8.904 ;
    END
  END dq[28]
  PIN dq[290]
    DIRECTION OUTPUT ;
    USE SIGNAL ;
    PORT
      LAYER M4 ;
        RECT  36.528 50.832 36.72 50.856 ;
    END
  END dq[290]
  PIN dq[291]
    DIRECTION OUTPUT ;
    USE SIGNAL ;
    PORT
      LAYER M4 ;
        RECT  36.528 50.976 36.72 51 ;
    END
  END dq[291]
  PIN dq[292]
    DIRECTION OUTPUT ;
    USE SIGNAL ;
    PORT
      LAYER M4 ;
        RECT  36.528 51.12 36.72 51.144 ;
    END
  END dq[292]
  PIN dq[293]
    DIRECTION OUTPUT ;
    USE SIGNAL ;
    PORT
      LAYER M4 ;
        RECT  36.528 51.312 36.72 51.336 ;
    END
  END dq[293]
  PIN dq[294]
    DIRECTION OUTPUT ;
    USE SIGNAL ;
    PORT
      LAYER M4 ;
        RECT  36.528 51.456 36.72 51.48 ;
    END
  END dq[294]
  PIN dq[295]
    DIRECTION OUTPUT ;
    USE SIGNAL ;
    PORT
      LAYER M4 ;
        RECT  36.528 51.6 36.72 51.624 ;
    END
  END dq[295]
  PIN dq[296]
    DIRECTION OUTPUT ;
    USE SIGNAL ;
    PORT
      LAYER M4 ;
        RECT  36.528 51.792 36.72 51.816 ;
    END
  END dq[296]
  PIN dq[297]
    DIRECTION OUTPUT ;
    USE SIGNAL ;
    PORT
      LAYER M4 ;
        RECT  36.528 51.936 36.72 51.96 ;
    END
  END dq[297]
  PIN dq[298]
    DIRECTION OUTPUT ;
    USE SIGNAL ;
    PORT
      LAYER M4 ;
        RECT  36.528 52.08 36.72 52.104 ;
    END
  END dq[298]
  PIN dq[299]
    DIRECTION OUTPUT ;
    USE SIGNAL ;
    PORT
      LAYER M4 ;
        RECT  36.528 52.272 36.72 52.296 ;
    END
  END dq[299]
  PIN dq[29]
    DIRECTION OUTPUT ;
    USE SIGNAL ;
    PORT
      LAYER M4 ;
        RECT  36.528 9.072 36.72 9.096 ;
    END
  END dq[29]
  PIN dq[2]
    DIRECTION OUTPUT ;
    USE SIGNAL ;
    PORT
      LAYER M4 ;
        RECT  36.528 4.752 36.72 4.776 ;
    END
  END dq[2]
  PIN dq[300]
    DIRECTION OUTPUT ;
    USE SIGNAL ;
    PORT
      LAYER M4 ;
        RECT  36.528 52.416 36.72 52.44 ;
    END
  END dq[300]
  PIN dq[301]
    DIRECTION OUTPUT ;
    USE SIGNAL ;
    PORT
      LAYER M4 ;
        RECT  36.528 52.56 36.72 52.584 ;
    END
  END dq[301]
  PIN dq[302]
    DIRECTION OUTPUT ;
    USE SIGNAL ;
    PORT
      LAYER M4 ;
        RECT  36.528 52.752 36.72 52.776 ;
    END
  END dq[302]
  PIN dq[303]
    DIRECTION OUTPUT ;
    USE SIGNAL ;
    PORT
      LAYER M4 ;
        RECT  36.528 52.896 36.72 52.92 ;
    END
  END dq[303]
  PIN dq[304]
    DIRECTION OUTPUT ;
    USE SIGNAL ;
    PORT
      LAYER M4 ;
        RECT  36.528 53.04 36.72 53.064 ;
    END
  END dq[304]
  PIN dq[305]
    DIRECTION OUTPUT ;
    USE SIGNAL ;
    PORT
      LAYER M4 ;
        RECT  36.528 53.232 36.72 53.256 ;
    END
  END dq[305]
  PIN dq[306]
    DIRECTION OUTPUT ;
    USE SIGNAL ;
    PORT
      LAYER M4 ;
        RECT  36.528 53.376 36.72 53.4 ;
    END
  END dq[306]
  PIN dq[307]
    DIRECTION OUTPUT ;
    USE SIGNAL ;
    PORT
      LAYER M4 ;
        RECT  36.528 53.52 36.72 53.544 ;
    END
  END dq[307]
  PIN dq[308]
    DIRECTION OUTPUT ;
    USE SIGNAL ;
    PORT
      LAYER M4 ;
        RECT  36.528 53.712 36.72 53.736 ;
    END
  END dq[308]
  PIN dq[309]
    DIRECTION OUTPUT ;
    USE SIGNAL ;
    PORT
      LAYER M4 ;
        RECT  36.528 53.856 36.72 53.88 ;
    END
  END dq[309]
  PIN dq[30]
    DIRECTION OUTPUT ;
    USE SIGNAL ;
    PORT
      LAYER M4 ;
        RECT  36.528 9.216 36.72 9.24 ;
    END
  END dq[30]
  PIN dq[310]
    DIRECTION OUTPUT ;
    USE SIGNAL ;
    PORT
      LAYER M4 ;
        RECT  36.528 54 36.72 54.024 ;
    END
  END dq[310]
  PIN dq[311]
    DIRECTION OUTPUT ;
    USE SIGNAL ;
    PORT
      LAYER M4 ;
        RECT  36.528 54.192 36.72 54.216 ;
    END
  END dq[311]
  PIN dq[312]
    DIRECTION OUTPUT ;
    USE SIGNAL ;
    PORT
      LAYER M4 ;
        RECT  36.528 54.336 36.72 54.36 ;
    END
  END dq[312]
  PIN dq[313]
    DIRECTION OUTPUT ;
    USE SIGNAL ;
    PORT
      LAYER M4 ;
        RECT  36.528 54.48 36.72 54.504 ;
    END
  END dq[313]
  PIN dq[314]
    DIRECTION OUTPUT ;
    USE SIGNAL ;
    PORT
      LAYER M4 ;
        RECT  36.528 54.672 36.72 54.696 ;
    END
  END dq[314]
  PIN dq[315]
    DIRECTION OUTPUT ;
    USE SIGNAL ;
    PORT
      LAYER M4 ;
        RECT  36.528 54.816 36.72 54.84 ;
    END
  END dq[315]
  PIN dq[316]
    DIRECTION OUTPUT ;
    USE SIGNAL ;
    PORT
      LAYER M4 ;
        RECT  36.528 54.96 36.72 54.984 ;
    END
  END dq[316]
  PIN dq[317]
    DIRECTION OUTPUT ;
    USE SIGNAL ;
    PORT
      LAYER M4 ;
        RECT  36.528 55.152 36.72 55.176 ;
    END
  END dq[317]
  PIN dq[318]
    DIRECTION OUTPUT ;
    USE SIGNAL ;
    PORT
      LAYER M4 ;
        RECT  36.528 55.296 36.72 55.32 ;
    END
  END dq[318]
  PIN dq[319]
    DIRECTION OUTPUT ;
    USE SIGNAL ;
    PORT
      LAYER M4 ;
        RECT  36.528 55.44 36.72 55.464 ;
    END
  END dq[319]
  PIN dq[31]
    DIRECTION OUTPUT ;
    USE SIGNAL ;
    PORT
      LAYER M4 ;
        RECT  36.528 9.36 36.72 9.384 ;
    END
  END dq[31]
  PIN dq[320]
    DIRECTION OUTPUT ;
    USE SIGNAL ;
    PORT
      LAYER M4 ;
        RECT  36.528 55.632 36.72 55.656 ;
    END
  END dq[320]
  PIN dq[321]
    DIRECTION OUTPUT ;
    USE SIGNAL ;
    PORT
      LAYER M4 ;
        RECT  36.528 55.776 36.72 55.8 ;
    END
  END dq[321]
  PIN dq[322]
    DIRECTION OUTPUT ;
    USE SIGNAL ;
    PORT
      LAYER M4 ;
        RECT  36.528 55.92 36.72 55.944 ;
    END
  END dq[322]
  PIN dq[323]
    DIRECTION OUTPUT ;
    USE SIGNAL ;
    PORT
      LAYER M4 ;
        RECT  36.528 56.112 36.72 56.136 ;
    END
  END dq[323]
  PIN dq[324]
    DIRECTION OUTPUT ;
    USE SIGNAL ;
    PORT
      LAYER M4 ;
        RECT  36.528 56.256 36.72 56.28 ;
    END
  END dq[324]
  PIN dq[325]
    DIRECTION OUTPUT ;
    USE SIGNAL ;
    PORT
      LAYER M4 ;
        RECT  36.528 56.4 36.72 56.424 ;
    END
  END dq[325]
  PIN dq[326]
    DIRECTION OUTPUT ;
    USE SIGNAL ;
    PORT
      LAYER M4 ;
        RECT  36.528 56.592 36.72 56.616 ;
    END
  END dq[326]
  PIN dq[327]
    DIRECTION OUTPUT ;
    USE SIGNAL ;
    PORT
      LAYER M4 ;
        RECT  36.528 56.736 36.72 56.76 ;
    END
  END dq[327]
  PIN dq[328]
    DIRECTION OUTPUT ;
    USE SIGNAL ;
    PORT
      LAYER M4 ;
        RECT  36.528 56.88 36.72 56.904 ;
    END
  END dq[328]
  PIN dq[329]
    DIRECTION OUTPUT ;
    USE SIGNAL ;
    PORT
      LAYER M4 ;
        RECT  36.528 57.072 36.72 57.096 ;
    END
  END dq[329]
  PIN dq[32]
    DIRECTION OUTPUT ;
    USE SIGNAL ;
    PORT
      LAYER M4 ;
        RECT  36.528 9.552 36.72 9.576 ;
    END
  END dq[32]
  PIN dq[330]
    DIRECTION OUTPUT ;
    USE SIGNAL ;
    PORT
      LAYER M4 ;
        RECT  36.528 57.216 36.72 57.24 ;
    END
  END dq[330]
  PIN dq[331]
    DIRECTION OUTPUT ;
    USE SIGNAL ;
    PORT
      LAYER M4 ;
        RECT  36.528 57.36 36.72 57.384 ;
    END
  END dq[331]
  PIN dq[332]
    DIRECTION OUTPUT ;
    USE SIGNAL ;
    PORT
      LAYER M4 ;
        RECT  36.528 57.552 36.72 57.576 ;
    END
  END dq[332]
  PIN dq[333]
    DIRECTION OUTPUT ;
    USE SIGNAL ;
    PORT
      LAYER M4 ;
        RECT  36.528 57.696 36.72 57.72 ;
    END
  END dq[333]
  PIN dq[334]
    DIRECTION OUTPUT ;
    USE SIGNAL ;
    PORT
      LAYER M4 ;
        RECT  36.528 57.84 36.72 57.864 ;
    END
  END dq[334]
  PIN dq[335]
    DIRECTION OUTPUT ;
    USE SIGNAL ;
    PORT
      LAYER M4 ;
        RECT  36.528 58.032 36.72 58.056 ;
    END
  END dq[335]
  PIN dq[336]
    DIRECTION OUTPUT ;
    USE SIGNAL ;
    PORT
      LAYER M4 ;
        RECT  36.528 58.176 36.72 58.2 ;
    END
  END dq[336]
  PIN dq[337]
    DIRECTION OUTPUT ;
    USE SIGNAL ;
    PORT
      LAYER M4 ;
        RECT  36.528 58.32 36.72 58.344 ;
    END
  END dq[337]
  PIN dq[338]
    DIRECTION OUTPUT ;
    USE SIGNAL ;
    PORT
      LAYER M4 ;
        RECT  36.528 58.512 36.72 58.536 ;
    END
  END dq[338]
  PIN dq[339]
    DIRECTION OUTPUT ;
    USE SIGNAL ;
    PORT
      LAYER M4 ;
        RECT  36.528 58.656 36.72 58.68 ;
    END
  END dq[339]
  PIN dq[33]
    DIRECTION OUTPUT ;
    USE SIGNAL ;
    PORT
      LAYER M4 ;
        RECT  36.528 9.696 36.72 9.72 ;
    END
  END dq[33]
  PIN dq[340]
    DIRECTION OUTPUT ;
    USE SIGNAL ;
    PORT
      LAYER M4 ;
        RECT  36.528 58.8 36.72 58.824 ;
    END
  END dq[340]
  PIN dq[341]
    DIRECTION OUTPUT ;
    USE SIGNAL ;
    PORT
      LAYER M4 ;
        RECT  36.528 58.992 36.72 59.016 ;
    END
  END dq[341]
  PIN dq[342]
    DIRECTION OUTPUT ;
    USE SIGNAL ;
    PORT
      LAYER M4 ;
        RECT  36.528 59.136 36.72 59.16 ;
    END
  END dq[342]
  PIN dq[343]
    DIRECTION OUTPUT ;
    USE SIGNAL ;
    PORT
      LAYER M4 ;
        RECT  36.528 59.28 36.72 59.304 ;
    END
  END dq[343]
  PIN dq[344]
    DIRECTION OUTPUT ;
    USE SIGNAL ;
    PORT
      LAYER M4 ;
        RECT  36.528 59.472 36.72 59.496 ;
    END
  END dq[344]
  PIN dq[345]
    DIRECTION OUTPUT ;
    USE SIGNAL ;
    PORT
      LAYER M4 ;
        RECT  36.528 59.616 36.72 59.64 ;
    END
  END dq[345]
  PIN dq[346]
    DIRECTION OUTPUT ;
    USE SIGNAL ;
    PORT
      LAYER M4 ;
        RECT  36.528 59.76 36.72 59.784 ;
    END
  END dq[346]
  PIN dq[347]
    DIRECTION OUTPUT ;
    USE SIGNAL ;
    PORT
      LAYER M4 ;
        RECT  36.528 59.952 36.72 59.976 ;
    END
  END dq[347]
  PIN dq[348]
    DIRECTION OUTPUT ;
    USE SIGNAL ;
    PORT
      LAYER M4 ;
        RECT  36.528 60.096 36.72 60.12 ;
    END
  END dq[348]
  PIN dq[349]
    DIRECTION OUTPUT ;
    USE SIGNAL ;
    PORT
      LAYER M4 ;
        RECT  36.528 60.24 36.72 60.264 ;
    END
  END dq[349]
  PIN dq[34]
    DIRECTION OUTPUT ;
    USE SIGNAL ;
    PORT
      LAYER M4 ;
        RECT  36.528 9.84 36.72 9.864 ;
    END
  END dq[34]
  PIN dq[350]
    DIRECTION OUTPUT ;
    USE SIGNAL ;
    PORT
      LAYER M4 ;
        RECT  36.528 60.432 36.72 60.456 ;
    END
  END dq[350]
  PIN dq[351]
    DIRECTION OUTPUT ;
    USE SIGNAL ;
    PORT
      LAYER M4 ;
        RECT  36.528 60.576 36.72 60.6 ;
    END
  END dq[351]
  PIN dq[352]
    DIRECTION OUTPUT ;
    USE SIGNAL ;
    PORT
      LAYER M4 ;
        RECT  36.528 60.72 36.72 60.744 ;
    END
  END dq[352]
  PIN dq[353]
    DIRECTION OUTPUT ;
    USE SIGNAL ;
    PORT
      LAYER M4 ;
        RECT  36.528 60.912 36.72 60.936 ;
    END
  END dq[353]
  PIN dq[354]
    DIRECTION OUTPUT ;
    USE SIGNAL ;
    PORT
      LAYER M4 ;
        RECT  36.528 61.056 36.72 61.08 ;
    END
  END dq[354]
  PIN dq[355]
    DIRECTION OUTPUT ;
    USE SIGNAL ;
    PORT
      LAYER M4 ;
        RECT  36.528 61.2 36.72 61.224 ;
    END
  END dq[355]
  PIN dq[356]
    DIRECTION OUTPUT ;
    USE SIGNAL ;
    PORT
      LAYER M4 ;
        RECT  36.528 61.392 36.72 61.416 ;
    END
  END dq[356]
  PIN dq[357]
    DIRECTION OUTPUT ;
    USE SIGNAL ;
    PORT
      LAYER M4 ;
        RECT  36.528 61.536 36.72 61.56 ;
    END
  END dq[357]
  PIN dq[358]
    DIRECTION OUTPUT ;
    USE SIGNAL ;
    PORT
      LAYER M4 ;
        RECT  36.528 61.68 36.72 61.704 ;
    END
  END dq[358]
  PIN dq[359]
    DIRECTION OUTPUT ;
    USE SIGNAL ;
    PORT
      LAYER M4 ;
        RECT  36.528 61.872 36.72 61.896 ;
    END
  END dq[359]
  PIN dq[35]
    DIRECTION OUTPUT ;
    USE SIGNAL ;
    PORT
      LAYER M4 ;
        RECT  36.528 10.032 36.72 10.056 ;
    END
  END dq[35]
  PIN dq[360]
    DIRECTION OUTPUT ;
    USE SIGNAL ;
    PORT
      LAYER M4 ;
        RECT  36.528 62.016 36.72 62.04 ;
    END
  END dq[360]
  PIN dq[361]
    DIRECTION OUTPUT ;
    USE SIGNAL ;
    PORT
      LAYER M4 ;
        RECT  36.528 62.16 36.72 62.184 ;
    END
  END dq[361]
  PIN dq[362]
    DIRECTION OUTPUT ;
    USE SIGNAL ;
    PORT
      LAYER M4 ;
        RECT  36.528 62.352 36.72 62.376 ;
    END
  END dq[362]
  PIN dq[363]
    DIRECTION OUTPUT ;
    USE SIGNAL ;
    PORT
      LAYER M4 ;
        RECT  36.528 62.496 36.72 62.52 ;
    END
  END dq[363]
  PIN dq[364]
    DIRECTION OUTPUT ;
    USE SIGNAL ;
    PORT
      LAYER M4 ;
        RECT  36.528 62.64 36.72 62.664 ;
    END
  END dq[364]
  PIN dq[365]
    DIRECTION OUTPUT ;
    USE SIGNAL ;
    PORT
      LAYER M4 ;
        RECT  36.528 62.832 36.72 62.856 ;
    END
  END dq[365]
  PIN dq[366]
    DIRECTION OUTPUT ;
    USE SIGNAL ;
    PORT
      LAYER M4 ;
        RECT  36.528 62.976 36.72 63 ;
    END
  END dq[366]
  PIN dq[367]
    DIRECTION OUTPUT ;
    USE SIGNAL ;
    PORT
      LAYER M4 ;
        RECT  36.528 63.12 36.72 63.144 ;
    END
  END dq[367]
  PIN dq[368]
    DIRECTION OUTPUT ;
    USE SIGNAL ;
    PORT
      LAYER M4 ;
        RECT  36.528 63.312 36.72 63.336 ;
    END
  END dq[368]
  PIN dq[369]
    DIRECTION OUTPUT ;
    USE SIGNAL ;
    PORT
      LAYER M4 ;
        RECT  36.528 63.456 36.72 63.48 ;
    END
  END dq[369]
  PIN dq[36]
    DIRECTION OUTPUT ;
    USE SIGNAL ;
    PORT
      LAYER M4 ;
        RECT  36.528 10.176 36.72 10.2 ;
    END
  END dq[36]
  PIN dq[370]
    DIRECTION OUTPUT ;
    USE SIGNAL ;
    PORT
      LAYER M4 ;
        RECT  36.528 63.6 36.72 63.624 ;
    END
  END dq[370]
  PIN dq[371]
    DIRECTION OUTPUT ;
    USE SIGNAL ;
    PORT
      LAYER M4 ;
        RECT  36.528 63.792 36.72 63.816 ;
    END
  END dq[371]
  PIN dq[372]
    DIRECTION OUTPUT ;
    USE SIGNAL ;
    PORT
      LAYER M4 ;
        RECT  36.528 63.936 36.72 63.96 ;
    END
  END dq[372]
  PIN dq[373]
    DIRECTION OUTPUT ;
    USE SIGNAL ;
    PORT
      LAYER M4 ;
        RECT  36.528 64.08 36.72 64.104 ;
    END
  END dq[373]
  PIN dq[374]
    DIRECTION OUTPUT ;
    USE SIGNAL ;
    PORT
      LAYER M4 ;
        RECT  36.528 64.272 36.72 64.296 ;
    END
  END dq[374]
  PIN dq[375]
    DIRECTION OUTPUT ;
    USE SIGNAL ;
    PORT
      LAYER M4 ;
        RECT  36.528 64.416 36.72 64.44 ;
    END
  END dq[375]
  PIN dq[376]
    DIRECTION OUTPUT ;
    USE SIGNAL ;
    PORT
      LAYER M4 ;
        RECT  36.528 64.56 36.72 64.584 ;
    END
  END dq[376]
  PIN dq[377]
    DIRECTION OUTPUT ;
    USE SIGNAL ;
    PORT
      LAYER M4 ;
        RECT  36.528 64.752 36.72 64.776 ;
    END
  END dq[377]
  PIN dq[378]
    DIRECTION OUTPUT ;
    USE SIGNAL ;
    PORT
      LAYER M4 ;
        RECT  36.528 64.896 36.72 64.92 ;
    END
  END dq[378]
  PIN dq[379]
    DIRECTION OUTPUT ;
    USE SIGNAL ;
    PORT
      LAYER M4 ;
        RECT  36.528 65.04 36.72 65.064 ;
    END
  END dq[379]
  PIN dq[37]
    DIRECTION OUTPUT ;
    USE SIGNAL ;
    PORT
      LAYER M4 ;
        RECT  36.528 10.32 36.72 10.344 ;
    END
  END dq[37]
  PIN dq[380]
    DIRECTION OUTPUT ;
    USE SIGNAL ;
    PORT
      LAYER M4 ;
        RECT  36.528 65.232 36.72 65.256 ;
    END
  END dq[380]
  PIN dq[381]
    DIRECTION OUTPUT ;
    USE SIGNAL ;
    PORT
      LAYER M4 ;
        RECT  36.528 65.376 36.72 65.4 ;
    END
  END dq[381]
  PIN dq[382]
    DIRECTION OUTPUT ;
    USE SIGNAL ;
    PORT
      LAYER M4 ;
        RECT  36.528 65.52 36.72 65.544 ;
    END
  END dq[382]
  PIN dq[383]
    DIRECTION OUTPUT ;
    USE SIGNAL ;
    PORT
      LAYER M4 ;
        RECT  36.528 65.712 36.72 65.736 ;
    END
  END dq[383]
  PIN dq[384]
    DIRECTION OUTPUT ;
    USE SIGNAL ;
    PORT
      LAYER M4 ;
        RECT  36.528 65.856 36.72 65.88 ;
    END
  END dq[384]
  PIN dq[385]
    DIRECTION OUTPUT ;
    USE SIGNAL ;
    PORT
      LAYER M4 ;
        RECT  36.528 66 36.72 66.024 ;
    END
  END dq[385]
  PIN dq[386]
    DIRECTION OUTPUT ;
    USE SIGNAL ;
    PORT
      LAYER M4 ;
        RECT  36.528 66.192 36.72 66.216 ;
    END
  END dq[386]
  PIN dq[387]
    DIRECTION OUTPUT ;
    USE SIGNAL ;
    PORT
      LAYER M4 ;
        RECT  36.528 66.336 36.72 66.36 ;
    END
  END dq[387]
  PIN dq[388]
    DIRECTION OUTPUT ;
    USE SIGNAL ;
    PORT
      LAYER M4 ;
        RECT  36.528 66.48 36.72 66.504 ;
    END
  END dq[388]
  PIN dq[389]
    DIRECTION OUTPUT ;
    USE SIGNAL ;
    PORT
      LAYER M4 ;
        RECT  36.528 66.672 36.72 66.696 ;
    END
  END dq[389]
  PIN dq[38]
    DIRECTION OUTPUT ;
    USE SIGNAL ;
    PORT
      LAYER M4 ;
        RECT  36.528 10.512 36.72 10.536 ;
    END
  END dq[38]
  PIN dq[390]
    DIRECTION OUTPUT ;
    USE SIGNAL ;
    PORT
      LAYER M4 ;
        RECT  36.528 66.816 36.72 66.84 ;
    END
  END dq[390]
  PIN dq[391]
    DIRECTION OUTPUT ;
    USE SIGNAL ;
    PORT
      LAYER M4 ;
        RECT  36.528 66.96 36.72 66.984 ;
    END
  END dq[391]
  PIN dq[392]
    DIRECTION OUTPUT ;
    USE SIGNAL ;
    PORT
      LAYER M4 ;
        RECT  36.528 67.152 36.72 67.176 ;
    END
  END dq[392]
  PIN dq[393]
    DIRECTION OUTPUT ;
    USE SIGNAL ;
    PORT
      LAYER M4 ;
        RECT  36.528 67.296 36.72 67.32 ;
    END
  END dq[393]
  PIN dq[394]
    DIRECTION OUTPUT ;
    USE SIGNAL ;
    PORT
      LAYER M4 ;
        RECT  36.528 67.44 36.72 67.464 ;
    END
  END dq[394]
  PIN dq[395]
    DIRECTION OUTPUT ;
    USE SIGNAL ;
    PORT
      LAYER M4 ;
        RECT  36.528 67.632 36.72 67.656 ;
    END
  END dq[395]
  PIN dq[396]
    DIRECTION OUTPUT ;
    USE SIGNAL ;
    PORT
      LAYER M4 ;
        RECT  36.528 67.776 36.72 67.8 ;
    END
  END dq[396]
  PIN dq[397]
    DIRECTION OUTPUT ;
    USE SIGNAL ;
    PORT
      LAYER M4 ;
        RECT  36.528 67.92 36.72 67.944 ;
    END
  END dq[397]
  PIN dq[398]
    DIRECTION OUTPUT ;
    USE SIGNAL ;
    PORT
      LAYER M4 ;
        RECT  36.528 68.112 36.72 68.136 ;
    END
  END dq[398]
  PIN dq[399]
    DIRECTION OUTPUT ;
    USE SIGNAL ;
    PORT
      LAYER M4 ;
        RECT  36.528 68.256 36.72 68.28 ;
    END
  END dq[399]
  PIN dq[39]
    DIRECTION OUTPUT ;
    USE SIGNAL ;
    PORT
      LAYER M4 ;
        RECT  36.528 10.656 36.72 10.68 ;
    END
  END dq[39]
  PIN dq[3]
    DIRECTION OUTPUT ;
    USE SIGNAL ;
    PORT
      LAYER M4 ;
        RECT  36.528 4.896 36.72 4.92 ;
    END
  END dq[3]
  PIN dq[400]
    DIRECTION OUTPUT ;
    USE SIGNAL ;
    PORT
      LAYER M4 ;
        RECT  36.528 68.4 36.72 68.424 ;
    END
  END dq[400]
  PIN dq[401]
    DIRECTION OUTPUT ;
    USE SIGNAL ;
    PORT
      LAYER M4 ;
        RECT  36.528 68.592 36.72 68.616 ;
    END
  END dq[401]
  PIN dq[402]
    DIRECTION OUTPUT ;
    USE SIGNAL ;
    PORT
      LAYER M4 ;
        RECT  36.528 68.736 36.72 68.76 ;
    END
  END dq[402]
  PIN dq[403]
    DIRECTION OUTPUT ;
    USE SIGNAL ;
    PORT
      LAYER M4 ;
        RECT  36.528 68.88 36.72 68.904 ;
    END
  END dq[403]
  PIN dq[404]
    DIRECTION OUTPUT ;
    USE SIGNAL ;
    PORT
      LAYER M4 ;
        RECT  36.528 69.072 36.72 69.096 ;
    END
  END dq[404]
  PIN dq[405]
    DIRECTION OUTPUT ;
    USE SIGNAL ;
    PORT
      LAYER M4 ;
        RECT  36.528 69.216 36.72 69.24 ;
    END
  END dq[405]
  PIN dq[406]
    DIRECTION OUTPUT ;
    USE SIGNAL ;
    PORT
      LAYER M4 ;
        RECT  36.528 69.36 36.72 69.384 ;
    END
  END dq[406]
  PIN dq[407]
    DIRECTION OUTPUT ;
    USE SIGNAL ;
    PORT
      LAYER M4 ;
        RECT  36.528 69.552 36.72 69.576 ;
    END
  END dq[407]
  PIN dq[408]
    DIRECTION OUTPUT ;
    USE SIGNAL ;
    PORT
      LAYER M4 ;
        RECT  36.528 69.696 36.72 69.72 ;
    END
  END dq[408]
  PIN dq[409]
    DIRECTION OUTPUT ;
    USE SIGNAL ;
    PORT
      LAYER M4 ;
        RECT  36.528 69.84 36.72 69.864 ;
    END
  END dq[409]
  PIN dq[40]
    DIRECTION OUTPUT ;
    USE SIGNAL ;
    PORT
      LAYER M4 ;
        RECT  36.528 10.8 36.72 10.824 ;
    END
  END dq[40]
  PIN dq[410]
    DIRECTION OUTPUT ;
    USE SIGNAL ;
    PORT
      LAYER M4 ;
        RECT  36.528 70.032 36.72 70.056 ;
    END
  END dq[410]
  PIN dq[411]
    DIRECTION OUTPUT ;
    USE SIGNAL ;
    PORT
      LAYER M4 ;
        RECT  36.528 70.176 36.72 70.2 ;
    END
  END dq[411]
  PIN dq[412]
    DIRECTION OUTPUT ;
    USE SIGNAL ;
    PORT
      LAYER M4 ;
        RECT  36.528 70.32 36.72 70.344 ;
    END
  END dq[412]
  PIN dq[413]
    DIRECTION OUTPUT ;
    USE SIGNAL ;
    PORT
      LAYER M4 ;
        RECT  36.528 70.512 36.72 70.536 ;
    END
  END dq[413]
  PIN dq[414]
    DIRECTION OUTPUT ;
    USE SIGNAL ;
    PORT
      LAYER M4 ;
        RECT  36.528 70.656 36.72 70.68 ;
    END
  END dq[414]
  PIN dq[415]
    DIRECTION OUTPUT ;
    USE SIGNAL ;
    PORT
      LAYER M4 ;
        RECT  36.528 70.8 36.72 70.824 ;
    END
  END dq[415]
  PIN dq[416]
    DIRECTION OUTPUT ;
    USE SIGNAL ;
    PORT
      LAYER M4 ;
        RECT  36.528 70.992 36.72 71.016 ;
    END
  END dq[416]
  PIN dq[417]
    DIRECTION OUTPUT ;
    USE SIGNAL ;
    PORT
      LAYER M4 ;
        RECT  36.528 71.136 36.72 71.16 ;
    END
  END dq[417]
  PIN dq[418]
    DIRECTION OUTPUT ;
    USE SIGNAL ;
    PORT
      LAYER M4 ;
        RECT  36.528 71.28 36.72 71.304 ;
    END
  END dq[418]
  PIN dq[419]
    DIRECTION OUTPUT ;
    USE SIGNAL ;
    PORT
      LAYER M4 ;
        RECT  36.528 71.472 36.72 71.496 ;
    END
  END dq[419]
  PIN dq[41]
    DIRECTION OUTPUT ;
    USE SIGNAL ;
    PORT
      LAYER M4 ;
        RECT  36.528 10.992 36.72 11.016 ;
    END
  END dq[41]
  PIN dq[420]
    DIRECTION OUTPUT ;
    USE SIGNAL ;
    PORT
      LAYER M4 ;
        RECT  36.528 71.616 36.72 71.64 ;
    END
  END dq[420]
  PIN dq[421]
    DIRECTION OUTPUT ;
    USE SIGNAL ;
    PORT
      LAYER M4 ;
        RECT  36.528 71.76 36.72 71.784 ;
    END
  END dq[421]
  PIN dq[422]
    DIRECTION OUTPUT ;
    USE SIGNAL ;
    PORT
      LAYER M4 ;
        RECT  36.528 71.952 36.72 71.976 ;
    END
  END dq[422]
  PIN dq[423]
    DIRECTION OUTPUT ;
    USE SIGNAL ;
    PORT
      LAYER M4 ;
        RECT  36.528 72.096 36.72 72.12 ;
    END
  END dq[423]
  PIN dq[424]
    DIRECTION OUTPUT ;
    USE SIGNAL ;
    PORT
      LAYER M4 ;
        RECT  36.528 72.24 36.72 72.264 ;
    END
  END dq[424]
  PIN dq[425]
    DIRECTION OUTPUT ;
    USE SIGNAL ;
    PORT
      LAYER M4 ;
        RECT  36.528 72.432 36.72 72.456 ;
    END
  END dq[425]
  PIN dq[426]
    DIRECTION OUTPUT ;
    USE SIGNAL ;
    PORT
      LAYER M4 ;
        RECT  36.528 72.576 36.72 72.6 ;
    END
  END dq[426]
  PIN dq[427]
    DIRECTION OUTPUT ;
    USE SIGNAL ;
    PORT
      LAYER M4 ;
        RECT  36.528 72.72 36.72 72.744 ;
    END
  END dq[427]
  PIN dq[428]
    DIRECTION OUTPUT ;
    USE SIGNAL ;
    PORT
      LAYER M4 ;
        RECT  36.528 72.912 36.72 72.936 ;
    END
  END dq[428]
  PIN dq[429]
    DIRECTION OUTPUT ;
    USE SIGNAL ;
    PORT
      LAYER M4 ;
        RECT  36.528 73.056 36.72 73.08 ;
    END
  END dq[429]
  PIN dq[42]
    DIRECTION OUTPUT ;
    USE SIGNAL ;
    PORT
      LAYER M4 ;
        RECT  36.528 11.136 36.72 11.16 ;
    END
  END dq[42]
  PIN dq[430]
    DIRECTION OUTPUT ;
    USE SIGNAL ;
    PORT
      LAYER M4 ;
        RECT  36.528 73.2 36.72 73.224 ;
    END
  END dq[430]
  PIN dq[431]
    DIRECTION OUTPUT ;
    USE SIGNAL ;
    PORT
      LAYER M4 ;
        RECT  36.528 73.392 36.72 73.416 ;
    END
  END dq[431]
  PIN dq[432]
    DIRECTION OUTPUT ;
    USE SIGNAL ;
    PORT
      LAYER M4 ;
        RECT  36.528 73.536 36.72 73.56 ;
    END
  END dq[432]
  PIN dq[433]
    DIRECTION OUTPUT ;
    USE SIGNAL ;
    PORT
      LAYER M4 ;
        RECT  36.528 73.68 36.72 73.704 ;
    END
  END dq[433]
  PIN dq[434]
    DIRECTION OUTPUT ;
    USE SIGNAL ;
    PORT
      LAYER M4 ;
        RECT  36.528 73.872 36.72 73.896 ;
    END
  END dq[434]
  PIN dq[435]
    DIRECTION OUTPUT ;
    USE SIGNAL ;
    PORT
      LAYER M4 ;
        RECT  36.528 74.016 36.72 74.04 ;
    END
  END dq[435]
  PIN dq[436]
    DIRECTION OUTPUT ;
    USE SIGNAL ;
    PORT
      LAYER M4 ;
        RECT  36.528 74.16 36.72 74.184 ;
    END
  END dq[436]
  PIN dq[437]
    DIRECTION OUTPUT ;
    USE SIGNAL ;
    PORT
      LAYER M4 ;
        RECT  36.528 74.352 36.72 74.376 ;
    END
  END dq[437]
  PIN dq[438]
    DIRECTION OUTPUT ;
    USE SIGNAL ;
    PORT
      LAYER M4 ;
        RECT  36.528 74.496 36.72 74.52 ;
    END
  END dq[438]
  PIN dq[439]
    DIRECTION OUTPUT ;
    USE SIGNAL ;
    PORT
      LAYER M4 ;
        RECT  36.528 74.64 36.72 74.664 ;
    END
  END dq[439]
  PIN dq[43]
    DIRECTION OUTPUT ;
    USE SIGNAL ;
    PORT
      LAYER M4 ;
        RECT  36.528 11.28 36.72 11.304 ;
    END
  END dq[43]
  PIN dq[440]
    DIRECTION OUTPUT ;
    USE SIGNAL ;
    PORT
      LAYER M4 ;
        RECT  36.528 74.832 36.72 74.856 ;
    END
  END dq[440]
  PIN dq[441]
    DIRECTION OUTPUT ;
    USE SIGNAL ;
    PORT
      LAYER M4 ;
        RECT  36.528 74.976 36.72 75 ;
    END
  END dq[441]
  PIN dq[442]
    DIRECTION OUTPUT ;
    USE SIGNAL ;
    PORT
      LAYER M4 ;
        RECT  36.528 75.12 36.72 75.144 ;
    END
  END dq[442]
  PIN dq[443]
    DIRECTION OUTPUT ;
    USE SIGNAL ;
    PORT
      LAYER M4 ;
        RECT  36.528 75.312 36.72 75.336 ;
    END
  END dq[443]
  PIN dq[444]
    DIRECTION OUTPUT ;
    USE SIGNAL ;
    PORT
      LAYER M4 ;
        RECT  36.528 75.456 36.72 75.48 ;
    END
  END dq[444]
  PIN dq[445]
    DIRECTION OUTPUT ;
    USE SIGNAL ;
    PORT
      LAYER M4 ;
        RECT  36.528 75.6 36.72 75.624 ;
    END
  END dq[445]
  PIN dq[446]
    DIRECTION OUTPUT ;
    USE SIGNAL ;
    PORT
      LAYER M4 ;
        RECT  36.528 75.792 36.72 75.816 ;
    END
  END dq[446]
  PIN dq[447]
    DIRECTION OUTPUT ;
    USE SIGNAL ;
    PORT
      LAYER M4 ;
        RECT  36.528 75.936 36.72 75.96 ;
    END
  END dq[447]
  PIN dq[448]
    DIRECTION OUTPUT ;
    USE SIGNAL ;
    PORT
      LAYER M4 ;
        RECT  36.528 76.08 36.72 76.104 ;
    END
  END dq[448]
  PIN dq[449]
    DIRECTION OUTPUT ;
    USE SIGNAL ;
    PORT
      LAYER M4 ;
        RECT  36.528 76.272 36.72 76.296 ;
    END
  END dq[449]
  PIN dq[44]
    DIRECTION OUTPUT ;
    USE SIGNAL ;
    PORT
      LAYER M4 ;
        RECT  36.528 11.472 36.72 11.496 ;
    END
  END dq[44]
  PIN dq[450]
    DIRECTION OUTPUT ;
    USE SIGNAL ;
    PORT
      LAYER M4 ;
        RECT  36.528 76.416 36.72 76.44 ;
    END
  END dq[450]
  PIN dq[451]
    DIRECTION OUTPUT ;
    USE SIGNAL ;
    PORT
      LAYER M4 ;
        RECT  36.528 76.56 36.72 76.584 ;
    END
  END dq[451]
  PIN dq[452]
    DIRECTION OUTPUT ;
    USE SIGNAL ;
    PORT
      LAYER M4 ;
        RECT  36.528 76.752 36.72 76.776 ;
    END
  END dq[452]
  PIN dq[453]
    DIRECTION OUTPUT ;
    USE SIGNAL ;
    PORT
      LAYER M4 ;
        RECT  36.528 76.896 36.72 76.92 ;
    END
  END dq[453]
  PIN dq[454]
    DIRECTION OUTPUT ;
    USE SIGNAL ;
    PORT
      LAYER M4 ;
        RECT  36.528 77.04 36.72 77.064 ;
    END
  END dq[454]
  PIN dq[455]
    DIRECTION OUTPUT ;
    USE SIGNAL ;
    PORT
      LAYER M4 ;
        RECT  36.528 77.232 36.72 77.256 ;
    END
  END dq[455]
  PIN dq[456]
    DIRECTION OUTPUT ;
    USE SIGNAL ;
    PORT
      LAYER M4 ;
        RECT  36.528 77.376 36.72 77.4 ;
    END
  END dq[456]
  PIN dq[457]
    DIRECTION OUTPUT ;
    USE SIGNAL ;
    PORT
      LAYER M4 ;
        RECT  36.528 77.52 36.72 77.544 ;
    END
  END dq[457]
  PIN dq[458]
    DIRECTION OUTPUT ;
    USE SIGNAL ;
    PORT
      LAYER M4 ;
        RECT  36.528 77.712 36.72 77.736 ;
    END
  END dq[458]
  PIN dq[459]
    DIRECTION OUTPUT ;
    USE SIGNAL ;
    PORT
      LAYER M4 ;
        RECT  36.528 77.856 36.72 77.88 ;
    END
  END dq[459]
  PIN dq[45]
    DIRECTION OUTPUT ;
    USE SIGNAL ;
    PORT
      LAYER M4 ;
        RECT  36.528 11.616 36.72 11.64 ;
    END
  END dq[45]
  PIN dq[460]
    DIRECTION OUTPUT ;
    USE SIGNAL ;
    PORT
      LAYER M4 ;
        RECT  36.528 78 36.72 78.024 ;
    END
  END dq[460]
  PIN dq[461]
    DIRECTION OUTPUT ;
    USE SIGNAL ;
    PORT
      LAYER M4 ;
        RECT  36.528 78.192 36.72 78.216 ;
    END
  END dq[461]
  PIN dq[462]
    DIRECTION OUTPUT ;
    USE SIGNAL ;
    PORT
      LAYER M4 ;
        RECT  36.528 78.336 36.72 78.36 ;
    END
  END dq[462]
  PIN dq[463]
    DIRECTION OUTPUT ;
    USE SIGNAL ;
    PORT
      LAYER M4 ;
        RECT  36.528 78.48 36.72 78.504 ;
    END
  END dq[463]
  PIN dq[464]
    DIRECTION OUTPUT ;
    USE SIGNAL ;
    PORT
      LAYER M4 ;
        RECT  36.528 78.672 36.72 78.696 ;
    END
  END dq[464]
  PIN dq[465]
    DIRECTION OUTPUT ;
    USE SIGNAL ;
    PORT
      LAYER M4 ;
        RECT  36.528 78.816 36.72 78.84 ;
    END
  END dq[465]
  PIN dq[466]
    DIRECTION OUTPUT ;
    USE SIGNAL ;
    PORT
      LAYER M4 ;
        RECT  36.528 78.96 36.72 78.984 ;
    END
  END dq[466]
  PIN dq[467]
    DIRECTION OUTPUT ;
    USE SIGNAL ;
    PORT
      LAYER M4 ;
        RECT  36.528 79.152 36.72 79.176 ;
    END
  END dq[467]
  PIN dq[468]
    DIRECTION OUTPUT ;
    USE SIGNAL ;
    PORT
      LAYER M4 ;
        RECT  36.528 79.296 36.72 79.32 ;
    END
  END dq[468]
  PIN dq[469]
    DIRECTION OUTPUT ;
    USE SIGNAL ;
    PORT
      LAYER M4 ;
        RECT  36.528 79.44 36.72 79.464 ;
    END
  END dq[469]
  PIN dq[46]
    DIRECTION OUTPUT ;
    USE SIGNAL ;
    PORT
      LAYER M4 ;
        RECT  36.528 11.76 36.72 11.784 ;
    END
  END dq[46]
  PIN dq[470]
    DIRECTION OUTPUT ;
    USE SIGNAL ;
    PORT
      LAYER M4 ;
        RECT  36.528 79.632 36.72 79.656 ;
    END
  END dq[470]
  PIN dq[471]
    DIRECTION OUTPUT ;
    USE SIGNAL ;
    PORT
      LAYER M4 ;
        RECT  36.528 79.776 36.72 79.8 ;
    END
  END dq[471]
  PIN dq[472]
    DIRECTION OUTPUT ;
    USE SIGNAL ;
    PORT
      LAYER M4 ;
        RECT  36.528 79.92 36.72 79.944 ;
    END
  END dq[472]
  PIN dq[473]
    DIRECTION OUTPUT ;
    USE SIGNAL ;
    PORT
      LAYER M4 ;
        RECT  36.528 80.112 36.72 80.136 ;
    END
  END dq[473]
  PIN dq[474]
    DIRECTION OUTPUT ;
    USE SIGNAL ;
    PORT
      LAYER M4 ;
        RECT  36.528 80.256 36.72 80.28 ;
    END
  END dq[474]
  PIN dq[475]
    DIRECTION OUTPUT ;
    USE SIGNAL ;
    PORT
      LAYER M4 ;
        RECT  36.528 80.4 36.72 80.424 ;
    END
  END dq[475]
  PIN dq[476]
    DIRECTION OUTPUT ;
    USE SIGNAL ;
    PORT
      LAYER M4 ;
        RECT  36.528 80.592 36.72 80.616 ;
    END
  END dq[476]
  PIN dq[477]
    DIRECTION OUTPUT ;
    USE SIGNAL ;
    PORT
      LAYER M4 ;
        RECT  36.528 80.736 36.72 80.76 ;
    END
  END dq[477]
  PIN dq[478]
    DIRECTION OUTPUT ;
    USE SIGNAL ;
    PORT
      LAYER M4 ;
        RECT  36.528 80.88 36.72 80.904 ;
    END
  END dq[478]
  PIN dq[479]
    DIRECTION OUTPUT ;
    USE SIGNAL ;
    PORT
      LAYER M4 ;
        RECT  36.528 81.072 36.72 81.096 ;
    END
  END dq[479]
  PIN dq[47]
    DIRECTION OUTPUT ;
    USE SIGNAL ;
    PORT
      LAYER M4 ;
        RECT  36.528 11.952 36.72 11.976 ;
    END
  END dq[47]
  PIN dq[480]
    DIRECTION OUTPUT ;
    USE SIGNAL ;
    PORT
      LAYER M4 ;
        RECT  36.528 81.216 36.72 81.24 ;
    END
  END dq[480]
  PIN dq[481]
    DIRECTION OUTPUT ;
    USE SIGNAL ;
    PORT
      LAYER M4 ;
        RECT  36.528 81.36 36.72 81.384 ;
    END
  END dq[481]
  PIN dq[482]
    DIRECTION OUTPUT ;
    USE SIGNAL ;
    PORT
      LAYER M4 ;
        RECT  36.528 81.552 36.72 81.576 ;
    END
  END dq[482]
  PIN dq[483]
    DIRECTION OUTPUT ;
    USE SIGNAL ;
    PORT
      LAYER M4 ;
        RECT  36.528 81.696 36.72 81.72 ;
    END
  END dq[483]
  PIN dq[484]
    DIRECTION OUTPUT ;
    USE SIGNAL ;
    PORT
      LAYER M4 ;
        RECT  36.528 81.84 36.72 81.864 ;
    END
  END dq[484]
  PIN dq[485]
    DIRECTION OUTPUT ;
    USE SIGNAL ;
    PORT
      LAYER M4 ;
        RECT  36.528 82.032 36.72 82.056 ;
    END
  END dq[485]
  PIN dq[486]
    DIRECTION OUTPUT ;
    USE SIGNAL ;
    PORT
      LAYER M4 ;
        RECT  36.528 82.176 36.72 82.2 ;
    END
  END dq[486]
  PIN dq[487]
    DIRECTION OUTPUT ;
    USE SIGNAL ;
    PORT
      LAYER M4 ;
        RECT  36.528 82.32 36.72 82.344 ;
    END
  END dq[487]
  PIN dq[488]
    DIRECTION OUTPUT ;
    USE SIGNAL ;
    PORT
      LAYER M4 ;
        RECT  36.528 82.512 36.72 82.536 ;
    END
  END dq[488]
  PIN dq[489]
    DIRECTION OUTPUT ;
    USE SIGNAL ;
    PORT
      LAYER M4 ;
        RECT  36.528 82.656 36.72 82.68 ;
    END
  END dq[489]
  PIN dq[48]
    DIRECTION OUTPUT ;
    USE SIGNAL ;
    PORT
      LAYER M4 ;
        RECT  36.528 12.096 36.72 12.12 ;
    END
  END dq[48]
  PIN dq[490]
    DIRECTION OUTPUT ;
    USE SIGNAL ;
    PORT
      LAYER M4 ;
        RECT  36.528 82.8 36.72 82.824 ;
    END
  END dq[490]
  PIN dq[491]
    DIRECTION OUTPUT ;
    USE SIGNAL ;
    PORT
      LAYER M4 ;
        RECT  36.528 82.992 36.72 83.016 ;
    END
  END dq[491]
  PIN dq[492]
    DIRECTION OUTPUT ;
    USE SIGNAL ;
    PORT
      LAYER M4 ;
        RECT  36.528 83.136 36.72 83.16 ;
    END
  END dq[492]
  PIN dq[493]
    DIRECTION OUTPUT ;
    USE SIGNAL ;
    PORT
      LAYER M4 ;
        RECT  36.528 83.28 36.72 83.304 ;
    END
  END dq[493]
  PIN dq[494]
    DIRECTION OUTPUT ;
    USE SIGNAL ;
    PORT
      LAYER M4 ;
        RECT  36.528 83.472 36.72 83.496 ;
    END
  END dq[494]
  PIN dq[495]
    DIRECTION OUTPUT ;
    USE SIGNAL ;
    PORT
      LAYER M4 ;
        RECT  36.528 83.616 36.72 83.64 ;
    END
  END dq[495]
  PIN dq[496]
    DIRECTION OUTPUT ;
    USE SIGNAL ;
    PORT
      LAYER M4 ;
        RECT  36.528 83.76 36.72 83.784 ;
    END
  END dq[496]
  PIN dq[497]
    DIRECTION OUTPUT ;
    USE SIGNAL ;
    PORT
      LAYER M4 ;
        RECT  36.528 83.952 36.72 83.976 ;
    END
  END dq[497]
  PIN dq[498]
    DIRECTION OUTPUT ;
    USE SIGNAL ;
    PORT
      LAYER M4 ;
        RECT  36.528 84.096 36.72 84.12 ;
    END
  END dq[498]
  PIN dq[499]
    DIRECTION OUTPUT ;
    USE SIGNAL ;
    PORT
      LAYER M4 ;
        RECT  36.528 84.24 36.72 84.264 ;
    END
  END dq[499]
  PIN dq[49]
    DIRECTION OUTPUT ;
    USE SIGNAL ;
    PORT
      LAYER M4 ;
        RECT  36.528 12.24 36.72 12.264 ;
    END
  END dq[49]
  PIN dq[4]
    DIRECTION OUTPUT ;
    USE SIGNAL ;
    PORT
      LAYER M4 ;
        RECT  36.528 5.04 36.72 5.064 ;
    END
  END dq[4]
  PIN dq[500]
    DIRECTION OUTPUT ;
    USE SIGNAL ;
    PORT
      LAYER M4 ;
        RECT  36.528 84.432 36.72 84.456 ;
    END
  END dq[500]
  PIN dq[501]
    DIRECTION OUTPUT ;
    USE SIGNAL ;
    PORT
      LAYER M4 ;
        RECT  36.528 84.576 36.72 84.6 ;
    END
  END dq[501]
  PIN dq[502]
    DIRECTION OUTPUT ;
    USE SIGNAL ;
    PORT
      LAYER M4 ;
        RECT  36.528 84.72 36.72 84.744 ;
    END
  END dq[502]
  PIN dq[503]
    DIRECTION OUTPUT ;
    USE SIGNAL ;
    PORT
      LAYER M4 ;
        RECT  36.528 84.912 36.72 84.936 ;
    END
  END dq[503]
  PIN dq[504]
    DIRECTION OUTPUT ;
    USE SIGNAL ;
    PORT
      LAYER M4 ;
        RECT  36.528 85.056 36.72 85.08 ;
    END
  END dq[504]
  PIN dq[505]
    DIRECTION OUTPUT ;
    USE SIGNAL ;
    PORT
      LAYER M4 ;
        RECT  36.528 85.2 36.72 85.224 ;
    END
  END dq[505]
  PIN dq[506]
    DIRECTION OUTPUT ;
    USE SIGNAL ;
    PORT
      LAYER M4 ;
        RECT  36.528 85.392 36.72 85.416 ;
    END
  END dq[506]
  PIN dq[507]
    DIRECTION OUTPUT ;
    USE SIGNAL ;
    PORT
      LAYER M4 ;
        RECT  36.528 85.536 36.72 85.56 ;
    END
  END dq[507]
  PIN dq[508]
    DIRECTION OUTPUT ;
    USE SIGNAL ;
    PORT
      LAYER M4 ;
        RECT  36.528 85.68 36.72 85.704 ;
    END
  END dq[508]
  PIN dq[509]
    DIRECTION OUTPUT ;
    USE SIGNAL ;
    PORT
      LAYER M4 ;
        RECT  36.528 85.872 36.72 85.896 ;
    END
  END dq[509]
  PIN dq[50]
    DIRECTION OUTPUT ;
    USE SIGNAL ;
    PORT
      LAYER M4 ;
        RECT  36.528 12.432 36.72 12.456 ;
    END
  END dq[50]
  PIN dq[510]
    DIRECTION OUTPUT ;
    USE SIGNAL ;
    PORT
      LAYER M4 ;
        RECT  36.528 86.016 36.72 86.04 ;
    END
  END dq[510]
  PIN dq[511]
    DIRECTION OUTPUT ;
    USE SIGNAL ;
    PORT
      LAYER M4 ;
        RECT  36.528 86.16 36.72 86.184 ;
    END
  END dq[511]
  PIN dq[512]
    DIRECTION OUTPUT ;
    USE SIGNAL ;
    PORT
      LAYER M4 ;
        RECT  36.528 86.352 36.72 86.376 ;
    END
  END dq[512]
  PIN dq[51]
    DIRECTION OUTPUT ;
    USE SIGNAL ;
    PORT
      LAYER M4 ;
        RECT  36.528 12.576 36.72 12.6 ;
    END
  END dq[51]
  PIN dq[52]
    DIRECTION OUTPUT ;
    USE SIGNAL ;
    PORT
      LAYER M4 ;
        RECT  36.528 12.72 36.72 12.744 ;
    END
  END dq[52]
  PIN dq[53]
    DIRECTION OUTPUT ;
    USE SIGNAL ;
    PORT
      LAYER M4 ;
        RECT  36.528 12.912 36.72 12.936 ;
    END
  END dq[53]
  PIN dq[54]
    DIRECTION OUTPUT ;
    USE SIGNAL ;
    PORT
      LAYER M4 ;
        RECT  36.528 13.056 36.72 13.08 ;
    END
  END dq[54]
  PIN dq[55]
    DIRECTION OUTPUT ;
    USE SIGNAL ;
    PORT
      LAYER M4 ;
        RECT  36.528 13.2 36.72 13.224 ;
    END
  END dq[55]
  PIN dq[56]
    DIRECTION OUTPUT ;
    USE SIGNAL ;
    PORT
      LAYER M4 ;
        RECT  36.528 13.392 36.72 13.416 ;
    END
  END dq[56]
  PIN dq[57]
    DIRECTION OUTPUT ;
    USE SIGNAL ;
    PORT
      LAYER M4 ;
        RECT  36.528 13.536 36.72 13.56 ;
    END
  END dq[57]
  PIN dq[58]
    DIRECTION OUTPUT ;
    USE SIGNAL ;
    PORT
      LAYER M4 ;
        RECT  36.528 13.68 36.72 13.704 ;
    END
  END dq[58]
  PIN dq[59]
    DIRECTION OUTPUT ;
    USE SIGNAL ;
    PORT
      LAYER M4 ;
        RECT  36.528 13.872 36.72 13.896 ;
    END
  END dq[59]
  PIN dq[5]
    DIRECTION OUTPUT ;
    USE SIGNAL ;
    PORT
      LAYER M4 ;
        RECT  36.528 5.232 36.72 5.256 ;
    END
  END dq[5]
  PIN dq[60]
    DIRECTION OUTPUT ;
    USE SIGNAL ;
    PORT
      LAYER M4 ;
        RECT  36.528 14.016 36.72 14.04 ;
    END
  END dq[60]
  PIN dq[61]
    DIRECTION OUTPUT ;
    USE SIGNAL ;
    PORT
      LAYER M4 ;
        RECT  36.528 14.16 36.72 14.184 ;
    END
  END dq[61]
  PIN dq[62]
    DIRECTION OUTPUT ;
    USE SIGNAL ;
    PORT
      LAYER M4 ;
        RECT  36.528 14.352 36.72 14.376 ;
    END
  END dq[62]
  PIN dq[63]
    DIRECTION OUTPUT ;
    USE SIGNAL ;
    PORT
      LAYER M4 ;
        RECT  36.528 14.496 36.72 14.52 ;
    END
  END dq[63]
  PIN dq[64]
    DIRECTION OUTPUT ;
    USE SIGNAL ;
    PORT
      LAYER M4 ;
        RECT  36.528 14.64 36.72 14.664 ;
    END
  END dq[64]
  PIN dq[65]
    DIRECTION OUTPUT ;
    USE SIGNAL ;
    PORT
      LAYER M4 ;
        RECT  36.528 14.832 36.72 14.856 ;
    END
  END dq[65]
  PIN dq[66]
    DIRECTION OUTPUT ;
    USE SIGNAL ;
    PORT
      LAYER M4 ;
        RECT  36.528 14.976 36.72 15 ;
    END
  END dq[66]
  PIN dq[67]
    DIRECTION OUTPUT ;
    USE SIGNAL ;
    PORT
      LAYER M4 ;
        RECT  36.528 15.12 36.72 15.144 ;
    END
  END dq[67]
  PIN dq[68]
    DIRECTION OUTPUT ;
    USE SIGNAL ;
    PORT
      LAYER M4 ;
        RECT  36.528 15.312 36.72 15.336 ;
    END
  END dq[68]
  PIN dq[69]
    DIRECTION OUTPUT ;
    USE SIGNAL ;
    PORT
      LAYER M4 ;
        RECT  36.528 15.456 36.72 15.48 ;
    END
  END dq[69]
  PIN dq[6]
    DIRECTION OUTPUT ;
    USE SIGNAL ;
    PORT
      LAYER M4 ;
        RECT  36.528 5.376 36.72 5.4 ;
    END
  END dq[6]
  PIN dq[70]
    DIRECTION OUTPUT ;
    USE SIGNAL ;
    PORT
      LAYER M4 ;
        RECT  36.528 15.6 36.72 15.624 ;
    END
  END dq[70]
  PIN dq[71]
    DIRECTION OUTPUT ;
    USE SIGNAL ;
    PORT
      LAYER M4 ;
        RECT  36.528 15.792 36.72 15.816 ;
    END
  END dq[71]
  PIN dq[72]
    DIRECTION OUTPUT ;
    USE SIGNAL ;
    PORT
      LAYER M4 ;
        RECT  36.528 15.936 36.72 15.96 ;
    END
  END dq[72]
  PIN dq[73]
    DIRECTION OUTPUT ;
    USE SIGNAL ;
    PORT
      LAYER M4 ;
        RECT  36.528 16.08 36.72 16.104 ;
    END
  END dq[73]
  PIN dq[74]
    DIRECTION OUTPUT ;
    USE SIGNAL ;
    PORT
      LAYER M4 ;
        RECT  36.528 16.272 36.72 16.296 ;
    END
  END dq[74]
  PIN dq[75]
    DIRECTION OUTPUT ;
    USE SIGNAL ;
    PORT
      LAYER M4 ;
        RECT  36.528 16.416 36.72 16.44 ;
    END
  END dq[75]
  PIN dq[76]
    DIRECTION OUTPUT ;
    USE SIGNAL ;
    PORT
      LAYER M4 ;
        RECT  36.528 16.56 36.72 16.584 ;
    END
  END dq[76]
  PIN dq[77]
    DIRECTION OUTPUT ;
    USE SIGNAL ;
    PORT
      LAYER M4 ;
        RECT  36.528 16.752 36.72 16.776 ;
    END
  END dq[77]
  PIN dq[78]
    DIRECTION OUTPUT ;
    USE SIGNAL ;
    PORT
      LAYER M4 ;
        RECT  36.528 16.896 36.72 16.92 ;
    END
  END dq[78]
  PIN dq[79]
    DIRECTION OUTPUT ;
    USE SIGNAL ;
    PORT
      LAYER M4 ;
        RECT  36.528 17.04 36.72 17.064 ;
    END
  END dq[79]
  PIN dq[7]
    DIRECTION OUTPUT ;
    USE SIGNAL ;
    PORT
      LAYER M4 ;
        RECT  36.528 5.52 36.72 5.544 ;
    END
  END dq[7]
  PIN dq[80]
    DIRECTION OUTPUT ;
    USE SIGNAL ;
    PORT
      LAYER M4 ;
        RECT  36.528 17.232 36.72 17.256 ;
    END
  END dq[80]
  PIN dq[81]
    DIRECTION OUTPUT ;
    USE SIGNAL ;
    PORT
      LAYER M4 ;
        RECT  36.528 17.376 36.72 17.4 ;
    END
  END dq[81]
  PIN dq[82]
    DIRECTION OUTPUT ;
    USE SIGNAL ;
    PORT
      LAYER M4 ;
        RECT  36.528 17.52 36.72 17.544 ;
    END
  END dq[82]
  PIN dq[83]
    DIRECTION OUTPUT ;
    USE SIGNAL ;
    PORT
      LAYER M4 ;
        RECT  36.528 17.712 36.72 17.736 ;
    END
  END dq[83]
  PIN dq[84]
    DIRECTION OUTPUT ;
    USE SIGNAL ;
    PORT
      LAYER M4 ;
        RECT  36.528 17.856 36.72 17.88 ;
    END
  END dq[84]
  PIN dq[85]
    DIRECTION OUTPUT ;
    USE SIGNAL ;
    PORT
      LAYER M4 ;
        RECT  36.528 18 36.72 18.024 ;
    END
  END dq[85]
  PIN dq[86]
    DIRECTION OUTPUT ;
    USE SIGNAL ;
    PORT
      LAYER M4 ;
        RECT  36.528 18.192 36.72 18.216 ;
    END
  END dq[86]
  PIN dq[87]
    DIRECTION OUTPUT ;
    USE SIGNAL ;
    PORT
      LAYER M4 ;
        RECT  36.528 18.336 36.72 18.36 ;
    END
  END dq[87]
  PIN dq[88]
    DIRECTION OUTPUT ;
    USE SIGNAL ;
    PORT
      LAYER M4 ;
        RECT  36.528 18.48 36.72 18.504 ;
    END
  END dq[88]
  PIN dq[89]
    DIRECTION OUTPUT ;
    USE SIGNAL ;
    PORT
      LAYER M4 ;
        RECT  36.528 18.672 36.72 18.696 ;
    END
  END dq[89]
  PIN dq[8]
    DIRECTION OUTPUT ;
    USE SIGNAL ;
    PORT
      LAYER M4 ;
        RECT  36.528 5.712 36.72 5.736 ;
    END
  END dq[8]
  PIN dq[90]
    DIRECTION OUTPUT ;
    USE SIGNAL ;
    PORT
      LAYER M4 ;
        RECT  36.528 18.816 36.72 18.84 ;
    END
  END dq[90]
  PIN dq[91]
    DIRECTION OUTPUT ;
    USE SIGNAL ;
    PORT
      LAYER M4 ;
        RECT  36.528 18.96 36.72 18.984 ;
    END
  END dq[91]
  PIN dq[92]
    DIRECTION OUTPUT ;
    USE SIGNAL ;
    PORT
      LAYER M4 ;
        RECT  36.528 19.152 36.72 19.176 ;
    END
  END dq[92]
  PIN dq[93]
    DIRECTION OUTPUT ;
    USE SIGNAL ;
    PORT
      LAYER M4 ;
        RECT  36.528 19.296 36.72 19.32 ;
    END
  END dq[93]
  PIN dq[94]
    DIRECTION OUTPUT ;
    USE SIGNAL ;
    PORT
      LAYER M4 ;
        RECT  36.528 19.44 36.72 19.464 ;
    END
  END dq[94]
  PIN dq[95]
    DIRECTION OUTPUT ;
    USE SIGNAL ;
    PORT
      LAYER M4 ;
        RECT  36.528 19.632 36.72 19.656 ;
    END
  END dq[95]
  PIN dq[96]
    DIRECTION OUTPUT ;
    USE SIGNAL ;
    PORT
      LAYER M4 ;
        RECT  36.528 19.776 36.72 19.8 ;
    END
  END dq[96]
  PIN dq[97]
    DIRECTION OUTPUT ;
    USE SIGNAL ;
    PORT
      LAYER M4 ;
        RECT  36.528 19.92 36.72 19.944 ;
    END
  END dq[97]
  PIN dq[98]
    DIRECTION OUTPUT ;
    USE SIGNAL ;
    PORT
      LAYER M4 ;
        RECT  36.528 20.112 36.72 20.136 ;
    END
  END dq[98]
  PIN dq[99]
    DIRECTION OUTPUT ;
    USE SIGNAL ;
    PORT
      LAYER M4 ;
        RECT  36.528 20.256 36.72 20.28 ;
    END
  END dq[99]
  PIN dq[9]
    DIRECTION OUTPUT ;
    USE SIGNAL ;
    PORT
      LAYER M4 ;
        RECT  36.528 5.856 36.72 5.88 ;
    END
  END dq[9]
  PIN VDD
    DIRECTION INOUT ;
    USE POWER ;
    PORT
      LAYER M5 ;
        RECT  32.292 2.151 32.412 88.569 ;
        RECT  29.592 2.151 29.712 88.569 ;
        RECT  26.892 2.151 27.012 88.569 ;
        RECT  24.192 2.151 24.312 88.569 ;
        RECT  21.492 2.151 21.612 88.569 ;
        RECT  18.792 2.151 18.912 88.569 ;
        RECT  16.092 2.151 16.212 88.569 ;
        RECT  13.392 2.151 13.512 88.569 ;
        RECT  10.692 2.151 10.812 88.569 ;
        RECT  7.992 2.151 8.112 88.569 ;
        RECT  5.292 2.151 5.412 88.569 ;
        RECT  2.592 2.151 2.712 88.569 ;
    END
  END VDD
  PIN VSS
    DIRECTION INOUT ;
    USE GROUND ;
    PORT
      LAYER M5 ;
        RECT  32.1 2.137 32.22 88.583 ;
        RECT  29.4 2.137 29.52 88.583 ;
        RECT  26.7 2.137 26.82 88.583 ;
        RECT  24 2.137 24.12 88.583 ;
        RECT  21.3 2.137 21.42 88.583 ;
        RECT  18.6 2.137 18.72 88.583 ;
        RECT  15.9 2.137 16.02 88.583 ;
        RECT  13.2 2.137 13.32 88.583 ;
        RECT  10.5 2.137 10.62 88.583 ;
        RECT  7.8 2.137 7.92 88.583 ;
        RECT  5.1 2.137 5.22 88.583 ;
        RECT  2.4 2.137 2.52 88.583 ;
    END
  END VSS
  # OT_OBS_CLOSED layer=M5 d_um=1.536 added=56
  OBS
    LAYER RVTN ;
     RECT  2.16 2.16 34.56 2.295 ;
     RECT  2.16 2.565 34.56 2.835 ;
     RECT  2.16 3.105 34.56 3.375 ;
     RECT  2.16 3.645 34.56 3.915 ;
     RECT  2.16 4.185 34.56 4.455 ;
     RECT  2.16 4.725 34.56 4.995 ;
     RECT  2.16 5.265 34.56 5.535 ;
     RECT  2.16 5.805 34.56 6.075 ;
     RECT  2.16 6.345 34.56 6.615 ;
     RECT  2.16 6.885 34.56 7.155 ;
     RECT  2.16 7.425 34.56 7.695 ;
     RECT  2.16 7.965 34.56 8.235 ;
     RECT  2.16 8.505 34.56 8.775 ;
     RECT  2.16 9.045 34.56 9.315 ;
     RECT  2.16 9.585 34.56 9.855 ;
     RECT  2.16 10.125 34.56 10.395 ;
     RECT  2.16 10.665 34.56 10.935 ;
     RECT  2.16 11.205 34.56 11.475 ;
     RECT  2.16 11.745 34.56 12.015 ;
     RECT  2.16 12.285 34.56 12.555 ;
     RECT  2.16 12.825 34.56 13.095 ;
     RECT  2.16 13.365 34.56 13.635 ;
     RECT  2.16 13.905 34.56 14.175 ;
     RECT  2.16 14.445 34.56 14.715 ;
     RECT  2.16 14.985 34.56 15.255 ;
     RECT  2.16 15.525 34.56 15.795 ;
     RECT  2.16 16.065 34.56 16.335 ;
     RECT  2.16 16.605 34.56 16.875 ;
     RECT  2.16 17.145 34.56 17.415 ;
     RECT  2.16 17.685 34.56 17.955 ;
     RECT  2.16 18.225 34.56 18.495 ;
     RECT  2.16 18.765 34.56 19.035 ;
     RECT  2.16 19.305 34.56 19.575 ;
     RECT  2.16 19.845 34.56 20.115 ;
     RECT  2.16 20.385 34.56 20.655 ;
     RECT  2.16 20.925 34.56 21.195 ;
     RECT  2.16 21.465 34.56 21.735 ;
     RECT  2.16 22.005 34.56 22.275 ;
     RECT  2.16 22.545 34.56 22.815 ;
     RECT  2.16 23.085 34.56 23.355 ;
     RECT  2.16 23.625 34.56 23.895 ;
     RECT  2.16 24.165 34.56 24.435 ;
     RECT  2.16 24.705 34.56 24.975 ;
     RECT  2.16 25.245 34.56 25.515 ;
     RECT  2.16 25.785 34.56 26.055 ;
     RECT  2.16 26.325 34.56 26.595 ;
     RECT  2.16 26.865 34.56 27.135 ;
     RECT  2.16 27.405 34.56 27.675 ;
     RECT  2.16 27.945 34.56 28.215 ;
     RECT  2.16 28.485 34.56 28.755 ;
     RECT  2.16 29.025 34.56 29.295 ;
     RECT  2.16 29.565 34.56 29.835 ;
     RECT  2.16 30.105 34.56 30.375 ;
     RECT  2.16 30.645 34.56 30.915 ;
     RECT  2.16 31.185 34.56 31.455 ;
     RECT  2.16 31.725 34.56 31.995 ;
     RECT  2.16 32.265 34.56 32.535 ;
     RECT  2.16 32.805 34.56 33.075 ;
     RECT  2.16 33.345 34.56 33.615 ;
     RECT  2.16 33.885 34.56 34.155 ;
     RECT  2.16 34.425 34.56 34.695 ;
     RECT  2.16 34.965 34.56 35.235 ;
     RECT  2.16 35.505 34.56 35.775 ;
     RECT  2.16 36.045 34.56 36.315 ;
     RECT  2.16 36.585 34.56 36.855 ;
     RECT  2.16 37.125 34.56 37.395 ;
     RECT  2.16 37.665 34.56 37.935 ;
     RECT  2.16 38.205 34.56 38.475 ;
     RECT  2.16 38.745 34.56 39.015 ;
     RECT  2.16 39.285 34.56 39.555 ;
     RECT  2.16 39.825 34.56 40.095 ;
     RECT  2.16 40.365 34.56 40.635 ;
     RECT  2.16 40.905 34.56 41.175 ;
     RECT  2.16 41.445 34.56 41.715 ;
     RECT  2.16 41.985 34.56 42.255 ;
     RECT  2.16 42.525 34.56 42.795 ;
     RECT  2.16 43.065 34.56 43.335 ;
     RECT  2.16 43.605 34.56 43.875 ;
     RECT  2.16 44.145 34.56 44.415 ;
     RECT  2.16 44.685 34.56 44.955 ;
     RECT  2.16 45.225 34.56 45.495 ;
     RECT  2.16 45.765 34.56 46.035 ;
     RECT  2.16 46.305 34.56 46.575 ;
     RECT  2.16 46.845 34.56 47.115 ;
     RECT  2.16 47.385 34.56 47.655 ;
     RECT  2.16 47.925 34.56 48.195 ;
     RECT  2.16 48.465 34.56 48.735 ;
     RECT  2.16 49.005 34.56 49.275 ;
     RECT  2.16 49.545 34.56 49.815 ;
     RECT  2.16 50.085 34.56 50.355 ;
     RECT  2.16 50.625 34.56 50.895 ;
     RECT  2.16 51.165 34.56 51.435 ;
     RECT  2.16 51.705 34.56 51.975 ;
     RECT  2.16 52.245 34.56 52.515 ;
     RECT  2.16 52.785 34.56 53.055 ;
     RECT  2.16 53.325 34.56 53.595 ;
     RECT  2.16 53.865 34.56 54.135 ;
     RECT  2.16 54.405 34.56 54.675 ;
     RECT  2.16 54.945 34.56 55.215 ;
     RECT  2.16 55.485 34.56 55.755 ;
     RECT  2.16 56.025 34.56 56.295 ;
     RECT  2.16 56.565 34.56 56.835 ;
     RECT  2.16 57.105 34.56 57.375 ;
     RECT  2.16 57.645 34.56 57.915 ;
     RECT  2.16 58.185 34.56 58.455 ;
     RECT  2.16 58.725 34.56 58.995 ;
     RECT  2.16 59.265 34.56 59.535 ;
     RECT  2.16 59.805 34.56 60.075 ;
     RECT  2.16 60.345 34.56 60.615 ;
     RECT  2.16 60.885 34.56 61.155 ;
     RECT  2.16 61.425 34.56 61.695 ;
     RECT  2.16 61.965 34.56 62.235 ;
     RECT  2.16 62.505 34.56 62.775 ;
     RECT  2.16 63.045 34.56 63.315 ;
     RECT  2.16 63.585 34.56 63.855 ;
     RECT  2.16 64.125 34.56 64.395 ;
     RECT  2.16 64.665 34.56 64.935 ;
     RECT  2.16 65.205 34.56 65.475 ;
     RECT  2.16 65.745 34.56 66.015 ;
     RECT  2.16 66.285 34.56 66.555 ;
     RECT  2.16 66.825 34.56 67.095 ;
     RECT  2.16 67.365 34.56 67.635 ;
     RECT  2.16 67.905 34.56 68.175 ;
     RECT  2.16 68.445 34.56 68.715 ;
     RECT  2.16 68.985 34.56 69.255 ;
     RECT  2.16 69.525 34.56 69.795 ;
     RECT  2.16 70.065 34.56 70.335 ;
     RECT  2.16 70.605 34.56 70.875 ;
     RECT  2.16 71.145 34.56 71.415 ;
     RECT  2.16 71.685 34.56 71.955 ;
     RECT  2.16 72.225 34.56 72.495 ;
     RECT  2.16 72.765 34.56 73.035 ;
     RECT  2.16 73.305 34.56 73.575 ;
     RECT  2.16 73.845 34.56 74.115 ;
     RECT  2.16 74.385 34.56 74.655 ;
     RECT  2.16 74.925 34.56 75.195 ;
     RECT  2.16 75.465 34.56 75.735 ;
     RECT  2.16 76.005 34.56 76.275 ;
     RECT  2.16 76.545 34.56 76.815 ;
     RECT  2.16 77.085 34.56 77.355 ;
     RECT  2.16 77.625 34.56 77.895 ;
     RECT  2.16 78.165 34.56 78.435 ;
     RECT  2.16 78.705 34.56 78.975 ;
     RECT  2.16 79.245 34.56 79.515 ;
     RECT  2.16 79.785 34.56 80.055 ;
     RECT  2.16 80.325 34.56 80.595 ;
     RECT  2.16 80.865 34.56 81.135 ;
     RECT  2.16 81.405 34.56 81.675 ;
     RECT  2.16 81.945 34.56 82.215 ;
     RECT  2.16 82.485 34.56 82.755 ;
     RECT  2.16 83.025 34.56 83.295 ;
     RECT  2.16 83.565 34.56 83.835 ;
     RECT  2.16 84.105 34.56 84.375 ;
     RECT  2.16 84.645 34.56 84.915 ;
     RECT  2.16 85.185 34.56 85.455 ;
     RECT  2.16 85.725 34.56 85.995 ;
     RECT  2.16 86.265 34.56 86.535 ;
     RECT  2.16 86.805 34.56 87.075 ;
     RECT  2.16 87.345 34.56 87.615 ;
     RECT  2.16 87.885 34.56 88.155 ;
     RECT  2.16 88.425 34.56 88.56 ;
    LAYER RVTP ;
     RECT  2.16 2.295 34.56 2.565 ;
     RECT  2.16 2.835 34.56 3.105 ;
     RECT  2.16 3.375 34.56 3.645 ;
     RECT  2.16 3.915 34.56 4.185 ;
     RECT  2.16 4.455 34.56 4.725 ;
     RECT  2.16 4.995 34.56 5.265 ;
     RECT  2.16 5.535 34.56 5.805 ;
     RECT  2.16 6.075 34.56 6.345 ;
     RECT  2.16 6.615 34.56 6.885 ;
     RECT  2.16 7.155 34.56 7.425 ;
     RECT  2.16 7.695 34.56 7.965 ;
     RECT  2.16 8.235 34.56 8.505 ;
     RECT  2.16 8.775 34.56 9.045 ;
     RECT  2.16 9.315 34.56 9.585 ;
     RECT  2.16 9.855 34.56 10.125 ;
     RECT  2.16 10.395 34.56 10.665 ;
     RECT  2.16 10.935 34.56 11.205 ;
     RECT  2.16 11.475 34.56 11.745 ;
     RECT  2.16 12.015 34.56 12.285 ;
     RECT  2.16 12.555 34.56 12.825 ;
     RECT  2.16 13.095 34.56 13.365 ;
     RECT  2.16 13.635 34.56 13.905 ;
     RECT  2.16 14.175 34.56 14.445 ;
     RECT  2.16 14.715 34.56 14.985 ;
     RECT  2.16 15.255 34.56 15.525 ;
     RECT  2.16 15.795 34.56 16.065 ;
     RECT  2.16 16.335 34.56 16.605 ;
     RECT  2.16 16.875 34.56 17.145 ;
     RECT  2.16 17.415 34.56 17.685 ;
     RECT  2.16 17.955 34.56 18.225 ;
     RECT  2.16 18.495 34.56 18.765 ;
     RECT  2.16 19.035 34.56 19.305 ;
     RECT  2.16 19.575 34.56 19.845 ;
     RECT  2.16 20.115 34.56 20.385 ;
     RECT  2.16 20.655 34.56 20.925 ;
     RECT  2.16 21.195 34.56 21.465 ;
     RECT  2.16 21.735 34.56 22.005 ;
     RECT  2.16 22.275 34.56 22.545 ;
     RECT  2.16 22.815 34.56 23.085 ;
     RECT  2.16 23.355 34.56 23.625 ;
     RECT  2.16 23.895 34.56 24.165 ;
     RECT  2.16 24.435 34.56 24.705 ;
     RECT  2.16 24.975 34.56 25.245 ;
     RECT  2.16 25.515 34.56 25.785 ;
     RECT  2.16 26.055 34.56 26.325 ;
     RECT  2.16 26.595 34.56 26.865 ;
     RECT  2.16 27.135 34.56 27.405 ;
     RECT  2.16 27.675 34.56 27.945 ;
     RECT  2.16 28.215 34.56 28.485 ;
     RECT  2.16 28.755 34.56 29.025 ;
     RECT  2.16 29.295 34.56 29.565 ;
     RECT  2.16 29.835 34.56 30.105 ;
     RECT  2.16 30.375 34.56 30.645 ;
     RECT  2.16 30.915 34.56 31.185 ;
     RECT  2.16 31.455 34.56 31.725 ;
     RECT  2.16 31.995 34.56 32.265 ;
     RECT  2.16 32.535 34.56 32.805 ;
     RECT  2.16 33.075 34.56 33.345 ;
     RECT  2.16 33.615 34.56 33.885 ;
     RECT  2.16 34.155 34.56 34.425 ;
     RECT  2.16 34.695 34.56 34.965 ;
     RECT  2.16 35.235 34.56 35.505 ;
     RECT  2.16 35.775 34.56 36.045 ;
     RECT  2.16 36.315 34.56 36.585 ;
     RECT  2.16 36.855 34.56 37.125 ;
     RECT  2.16 37.395 34.56 37.665 ;
     RECT  2.16 37.935 34.56 38.205 ;
     RECT  2.16 38.475 34.56 38.745 ;
     RECT  2.16 39.015 34.56 39.285 ;
     RECT  2.16 39.555 34.56 39.825 ;
     RECT  2.16 40.095 34.56 40.365 ;
     RECT  2.16 40.635 34.56 40.905 ;
     RECT  2.16 41.175 34.56 41.445 ;
     RECT  2.16 41.715 34.56 41.985 ;
     RECT  2.16 42.255 34.56 42.525 ;
     RECT  2.16 42.795 34.56 43.065 ;
     RECT  2.16 43.335 34.56 43.605 ;
     RECT  2.16 43.875 34.56 44.145 ;
     RECT  2.16 44.415 34.56 44.685 ;
     RECT  2.16 44.955 34.56 45.225 ;
     RECT  2.16 45.495 34.56 45.765 ;
     RECT  2.16 46.035 34.56 46.305 ;
     RECT  2.16 46.575 34.56 46.845 ;
     RECT  2.16 47.115 34.56 47.385 ;
     RECT  2.16 47.655 34.56 47.925 ;
     RECT  2.16 48.195 34.56 48.465 ;
     RECT  2.16 48.735 34.56 49.005 ;
     RECT  2.16 49.275 34.56 49.545 ;
     RECT  2.16 49.815 34.56 50.085 ;
     RECT  2.16 50.355 34.56 50.625 ;
     RECT  2.16 50.895 34.56 51.165 ;
     RECT  2.16 51.435 34.56 51.705 ;
     RECT  2.16 51.975 34.56 52.245 ;
     RECT  2.16 52.515 34.56 52.785 ;
     RECT  2.16 53.055 34.56 53.325 ;
     RECT  2.16 53.595 34.56 53.865 ;
     RECT  2.16 54.135 34.56 54.405 ;
     RECT  2.16 54.675 34.56 54.945 ;
     RECT  2.16 55.215 34.56 55.485 ;
     RECT  2.16 55.755 34.56 56.025 ;
     RECT  2.16 56.295 34.56 56.565 ;
     RECT  2.16 56.835 34.56 57.105 ;
     RECT  2.16 57.375 34.56 57.645 ;
     RECT  2.16 57.915 34.56 58.185 ;
     RECT  2.16 58.455 34.56 58.725 ;
     RECT  2.16 58.995 34.56 59.265 ;
     RECT  2.16 59.535 34.56 59.805 ;
     RECT  2.16 60.075 34.56 60.345 ;
     RECT  2.16 60.615 34.56 60.885 ;
     RECT  2.16 61.155 34.56 61.425 ;
     RECT  2.16 61.695 34.56 61.965 ;
     RECT  2.16 62.235 34.56 62.505 ;
     RECT  2.16 62.775 34.56 63.045 ;
     RECT  2.16 63.315 34.56 63.585 ;
     RECT  2.16 63.855 34.56 64.125 ;
     RECT  2.16 64.395 34.56 64.665 ;
     RECT  2.16 64.935 34.56 65.205 ;
     RECT  2.16 65.475 34.56 65.745 ;
     RECT  2.16 66.015 34.56 66.285 ;
     RECT  2.16 66.555 34.56 66.825 ;
     RECT  2.16 67.095 34.56 67.365 ;
     RECT  2.16 67.635 34.56 67.905 ;
     RECT  2.16 68.175 34.56 68.445 ;
     RECT  2.16 68.715 34.56 68.985 ;
     RECT  2.16 69.255 34.56 69.525 ;
     RECT  2.16 69.795 34.56 70.065 ;
     RECT  2.16 70.335 34.56 70.605 ;
     RECT  2.16 70.875 34.56 71.145 ;
     RECT  2.16 71.415 34.56 71.685 ;
     RECT  2.16 71.955 34.56 72.225 ;
     RECT  2.16 72.495 34.56 72.765 ;
     RECT  2.16 73.035 34.56 73.305 ;
     RECT  2.16 73.575 34.56 73.845 ;
     RECT  2.16 74.115 34.56 74.385 ;
     RECT  2.16 74.655 34.56 74.925 ;
     RECT  2.16 75.195 34.56 75.465 ;
     RECT  2.16 75.735 34.56 76.005 ;
     RECT  2.16 76.275 34.56 76.545 ;
     RECT  2.16 76.815 34.56 77.085 ;
     RECT  2.16 77.355 34.56 77.625 ;
     RECT  2.16 77.895 34.56 78.165 ;
     RECT  2.16 78.435 34.56 78.705 ;
     RECT  2.16 78.975 34.56 79.245 ;
     RECT  2.16 79.515 34.56 79.785 ;
     RECT  2.16 80.055 34.56 80.325 ;
     RECT  2.16 80.595 34.56 80.865 ;
     RECT  2.16 81.135 34.56 81.405 ;
     RECT  2.16 81.675 34.56 81.945 ;
     RECT  2.16 82.215 34.56 82.485 ;
     RECT  2.16 82.755 34.56 83.025 ;
     RECT  2.16 83.295 34.56 83.565 ;
     RECT  2.16 83.835 34.56 84.105 ;
     RECT  2.16 84.375 34.56 84.645 ;
     RECT  2.16 84.915 34.56 85.185 ;
     RECT  2.16 85.455 34.56 85.725 ;
     RECT  2.16 85.995 34.56 86.265 ;
     RECT  2.16 86.535 34.56 86.805 ;
     RECT  2.16 87.075 34.56 87.345 ;
     RECT  2.16 87.615 34.56 87.885 ;
     RECT  2.16 88.155 34.56 88.425 ;
    LAYER M1 ;
     RECT  2.16 2.151 34.56 88.569 ;
    LAYER M2 ;
     RECT  0.319 33.048 2.16 33.066 ;
     RECT  0.211 52.992 2.16 53.01 ;
     RECT  0.211 63.252 2.16 63.27 ;
     RECT  0.535 67.68 2.16 67.698 ;
     RECT  0.247 69.498 2.16 69.516 ;
     RECT  0.211 73.512 2.16 73.53 ;
     RECT  18.175 90.558 18.383 90.576 ;
     RECT  2.16 2.151 34.56 88.569 ;
     RECT  34.56 5.076 34.763 24.894 ;
     RECT  34.56 25.758 34.763 76.068 ;
     RECT  34.56 76.824 34.763 85.446 ;
     RECT  34.763 5.166 34.799 24.894 ;
     RECT  34.763 25.758 34.799 63.072 ;
     RECT  34.763 76.824 34.799 83.592 ;
     RECT  34.763 84.348 34.799 85.446 ;
     RECT  34.56 86.346 34.799 88.074 ;
     RECT  34.799 5.616 34.835 6.372 ;
     RECT  34.799 86.706 35.051 88.074 ;
     RECT  35.051 86.976 35.087 88.074 ;
     RECT  35.087 86.976 35.159 87.804 ;
     RECT  35.159 86.976 35.339 87.264 ;
     RECT  34.56 3.726 35.375 4.284 ;
     RECT  34.835 5.616 35.375 6.102 ;
     RECT  34.799 7.164 35.375 24.498 ;
     RECT  34.799 27.306 35.375 33.336 ;
     RECT  34.799 34.164 35.375 50.148 ;
     RECT  34.799 50.94 35.375 53.622 ;
     RECT  34.799 54.378 35.375 60.102 ;
     RECT  34.763 63.9 35.375 76.068 ;
     RECT  34.799 80.946 35.375 83.484 ;
     RECT  35.375 3.96 35.411 4.284 ;
     RECT  35.375 12.726 35.411 13.464 ;
     RECT  35.375 46.044 35.411 48.222 ;
     RECT  35.375 58.536 35.411 60.102 ;
     RECT  35.375 63.9 35.411 72.324 ;
     RECT  35.375 73.08 35.411 73.944 ;
     RECT  35.411 63.9 35.447 65.304 ;
     RECT  34.799 76.824 35.447 80.118 ;
     RECT  35.339 86.976 35.915 86.994 ;
     RECT  35.411 3.96 35.951 4.14 ;
     RECT  35.375 7.776 35.951 7.794 ;
     RECT  35.375 10.476 35.951 11.538 ;
     RECT  35.411 13.446 35.951 13.464 ;
     RECT  35.375 14.256 35.951 16.128 ;
     RECT  35.375 16.956 35.951 24.498 ;
     RECT  34.799 25.758 35.951 26.424 ;
     RECT  35.375 27.756 35.951 33.336 ;
     RECT  35.375 34.2 35.951 40.464 ;
     RECT  35.375 41.454 35.951 43.056 ;
     RECT  35.375 43.956 35.951 45.288 ;
     RECT  35.411 46.044 35.951 46.908 ;
     RECT  35.375 49.086 35.951 50.148 ;
     RECT  35.375 50.976 35.951 53.388 ;
     RECT  35.375 54.378 35.951 57.672 ;
     RECT  35.411 58.536 35.951 58.554 ;
     RECT  35.411 59.346 35.951 60.102 ;
     RECT  34.799 61.128 35.951 63.072 ;
     RECT  35.447 63.9 35.951 64.35 ;
     RECT  35.447 65.286 35.951 65.304 ;
     RECT  35.411 66.33 35.951 72.324 ;
     RECT  35.411 73.08 35.951 73.098 ;
     RECT  35.411 73.926 35.951 73.944 ;
     RECT  35.375 74.898 35.951 76.068 ;
     RECT  35.447 76.824 35.951 76.842 ;
     RECT  35.447 77.67 35.951 80.118 ;
     RECT  35.375 80.946 35.951 83.394 ;
     RECT  34.799 84.348 35.951 85.284 ;
     RECT  35.951 4.122 35.987 4.14 ;
     RECT  35.375 5.616 35.987 5.634 ;
     RECT  35.375 8.586 35.987 9.648 ;
     RECT  35.951 11.214 35.987 11.502 ;
     RECT  35.951 14.256 35.987 14.976 ;
     RECT  35.951 20.088 35.987 20.646 ;
     RECT  35.951 21.546 35.987 21.564 ;
     RECT  35.951 23.166 35.987 23.652 ;
     RECT  35.951 26.1 35.987 26.118 ;
     RECT  35.951 27.99 35.987 29.322 ;
     RECT  35.951 30.456 35.987 32.598 ;
     RECT  35.951 34.2 35.987 35.028 ;
     RECT  35.951 36.126 35.987 37.998 ;
     RECT  35.951 39.33 35.987 40.122 ;
     RECT  35.951 41.724 35.987 43.056 ;
     RECT  35.951 44.046 35.987 45.288 ;
     RECT  35.951 46.584 35.987 46.872 ;
     RECT  35.411 47.664 35.987 48.222 ;
     RECT  35.951 49.518 35.987 50.148 ;
     RECT  35.951 51.408 35.987 51.426 ;
     RECT  35.951 52.29 35.987 52.344 ;
     RECT  35.951 54.99 35.987 55.314 ;
     RECT  35.951 56.538 35.987 57.672 ;
     RECT  35.951 59.346 35.987 59.364 ;
     RECT  35.951 61.74 35.987 62.064 ;
     RECT  35.951 63.054 35.987 63.072 ;
     RECT  35.951 66.33 35.987 66.888 ;
     RECT  35.951 68.796 35.987 69.894 ;
     RECT  35.951 70.65 35.987 70.668 ;
     RECT  35.951 71.928 35.987 71.946 ;
     RECT  35.951 75.816 35.987 75.834 ;
     RECT  35.951 78.714 35.987 79.542 ;
     RECT  35.951 81.144 35.987 82.746 ;
     RECT  35.951 84.456 35.987 84.978 ;
     RECT  35.987 9.126 36.023 9.144 ;
     RECT  35.987 11.484 36.023 11.502 ;
     RECT  35.987 14.418 36.023 14.436 ;
     RECT  35.951 18.396 36.023 18.792 ;
     RECT  35.987 20.628 36.023 20.646 ;
     RECT  35.987 29.304 36.023 29.322 ;
     RECT  35.987 30.618 36.023 32.598 ;
     RECT  35.987 34.2 36.023 34.218 ;
     RECT  35.987 36.864 36.023 36.882 ;
     RECT  35.987 37.746 36.023 37.764 ;
     RECT  35.987 39.726 36.023 39.744 ;
     RECT  35.987 41.994 36.023 42.282 ;
     RECT  35.987 43.038 36.023 43.056 ;
     RECT  35.987 47.664 36.023 47.682 ;
     RECT  35.987 49.518 36.023 49.536 ;
     RECT  35.987 56.538 36.023 57.564 ;
     RECT  35.987 61.74 36.023 61.992 ;
     RECT  35.987 66.366 36.023 66.546 ;
     RECT  35.987 69.264 36.023 69.282 ;
     RECT  35.987 79.326 36.023 79.344 ;
     RECT  35.987 81.486 36.023 82.242 ;
     RECT  36.023 18.774 36.059 18.792 ;
     RECT  35.987 27.99 36.059 28.008 ;
     RECT  36.023 30.996 36.059 31.014 ;
     RECT  36.023 31.806 36.059 32.094 ;
     RECT  35.987 34.974 36.059 34.992 ;
     RECT  36.023 42.264 36.059 42.282 ;
     RECT  35.987 52.29 36.059 52.308 ;
     RECT  36.023 56.88 36.059 57.204 ;
     RECT  36.023 61.974 36.059 61.992 ;
     RECT  36.023 66.366 36.059 66.384 ;
     RECT  36.023 81.954 36.059 81.972 ;
     RECT  36.059 32.076 36.095 32.094 ;
     RECT  36.059 57.186 36.095 57.204 ;
    LAYER M3 ;
     RECT  2.415 2.143 2.505 2.413 ;
     RECT  5.115 2.143 5.205 2.413 ;
     RECT  7.815 2.143 7.905 2.413 ;
     RECT  10.515 2.143 10.605 2.413 ;
     RECT  13.215 2.143 13.305 2.413 ;
     RECT  15.915 2.143 16.005 2.413 ;
     RECT  18.615 2.143 18.705 2.413 ;
     RECT  21.315 2.143 21.405 2.413 ;
     RECT  24.015 2.143 24.105 2.413 ;
     RECT  26.715 2.143 26.805 2.413 ;
     RECT  29.415 2.143 29.505 2.413 ;
     RECT  32.115 2.143 32.205 2.413 ;
     RECT  34.2 3.379 34.434 3.541 ;
     RECT  34.02 3.541 34.434 3.577 ;
     RECT  33.66 3.577 34.434 3.919 ;
     RECT  35.352 3.721 35.37 3.919 ;
     RECT  33.66 3.919 35.37 3.955 ;
     RECT  33.66 3.955 35.946 4.117 ;
     RECT  2.415 2.413 2.697 4.225 ;
     RECT  33.516 4.117 35.982 4.225 ;
     RECT  3.744 4.225 3.762 4.261 ;
     RECT  3.636 4.261 3.942 4.379 ;
     RECT  3.636 4.379 3.762 4.541 ;
     RECT  2.415 4.225 2.826 4.555 ;
     RECT  33.156 4.225 35.982 4.589 ;
     RECT  5.115 2.413 5.397 4.801 ;
     RECT  7.815 2.413 8.097 4.801 ;
     RECT  6.84 4.801 6.858 4.919 ;
     RECT  7.815 4.801 8.694 4.919 ;
     RECT  30.78 4.801 30.798 4.919 ;
     RECT  2.304 4.555 2.826 4.999 ;
     RECT  32.115 2.413 32.397 4.999 ;
     RECT  33.156 4.589 35.946 4.999 ;
     RECT  6.912 4.927 6.93 5.029 ;
     RECT  7.815 4.919 8.097 5.029 ;
     RECT  32.115 4.999 35.946 5.069 ;
     RECT  4.536 4.801 5.397 5.071 ;
     RECT  6.912 5.029 8.097 5.099 ;
     RECT  4.536 5.071 6.066 5.189 ;
     RECT  32.115 5.069 34.794 5.261 ;
     RECT  2.304 4.999 3.402 5.341 ;
     RECT  0.252 5.371 0.27 5.501 ;
     RECT  6.984 5.099 8.097 5.531 ;
     RECT  35.928 5.069 35.946 5.611 ;
     RECT  2.304 5.341 3.51 5.809 ;
     RECT  4.536 5.189 5.958 5.809 ;
     RECT  7.74 5.531 8.097 5.885 ;
     RECT  35.928 5.611 35.982 5.885 ;
     RECT  2.304 5.809 5.958 5.909 ;
     RECT  35.928 5.885 35.946 6.029 ;
     RECT  32.115 5.261 34.758 6.079 ;
     RECT  6.912 6.007 6.93 6.107 ;
     RECT  4.5 5.909 5.958 6.115 ;
     RECT  30.78 6.151 31.338 6.241 ;
     RECT  32.115 6.079 35.37 6.241 ;
     RECT  30.78 6.241 35.37 6.305 ;
     RECT  31.932 6.305 35.37 6.341 ;
     RECT  30.78 6.305 30.87 6.719 ;
     RECT  2.304 5.909 3.582 6.763 ;
     RECT  4.5 6.115 6.858 6.763 ;
     RECT  7.815 5.885 8.097 6.859 ;
     RECT  2.304 6.763 6.858 6.889 ;
     RECT  7.668 6.859 8.097 6.889 ;
     RECT  2.304 6.889 6.93 6.925 ;
     RECT  7.668 6.889 8.154 6.925 ;
     RECT  2.304 6.925 8.154 7.115 ;
     RECT  6.804 7.115 8.154 7.357 ;
     RECT  32.115 6.341 35.37 7.357 ;
     RECT  32.076 7.357 35.37 7.765 ;
     RECT  32.076 7.765 35.946 7.771 ;
     RECT  6.804 7.357 8.19 7.861 ;
     RECT  31.788 7.771 35.946 7.889 ;
     RECT  6.804 7.861 8.73 8.159 ;
     RECT  31.788 7.889 34.794 8.167 ;
     RECT  2.304 7.115 5.994 8.195 ;
     RECT  3.888 8.195 5.994 8.203 ;
     RECT  6.804 8.159 8.37 8.203 ;
     RECT  30.78 6.719 30.798 8.203 ;
     RECT  3.888 8.203 8.37 8.231 ;
     RECT  31.68 8.167 34.794 8.231 ;
     RECT  31.68 8.231 34.29 8.339 ;
     RECT  35.928 7.889 35.946 8.395 ;
     RECT  35.928 8.395 35.982 8.587 ;
     RECT  35.928 8.587 36.018 8.731 ;
     RECT  31.968 8.339 34.29 8.771 ;
     RECT  35.892 8.731 36.018 8.879 ;
     RECT  2.304 8.195 2.934 8.971 ;
     RECT  3.924 8.231 8.37 8.971 ;
     RECT  0.216 8.875 0.234 9.005 ;
     RECT  2.304 8.971 8.37 9.067 ;
     RECT  30.78 8.203 30.87 9.077 ;
     RECT  2.304 9.067 8.406 9.113 ;
     RECT  2.304 9.113 8.097 9.149 ;
     RECT  35.928 8.879 36.018 9.149 ;
     RECT  2.304 9.149 6.678 9.239 ;
     RECT  2.304 9.239 3.294 9.275 ;
     RECT  32.076 8.771 34.29 9.481 ;
     RECT  6.48 9.239 6.678 9.509 ;
     RECT  32.076 9.481 34.794 9.517 ;
     RECT  6.66 9.509 6.678 9.617 ;
     RECT  35.928 9.149 35.982 9.653 ;
     RECT  32.004 9.517 34.794 9.835 ;
     RECT  35.928 9.653 35.946 9.835 ;
     RECT  30.78 9.077 30.798 9.931 ;
     RECT  32.004 9.835 35.946 9.931 ;
     RECT  4.428 9.239 5.706 9.979 ;
     RECT  31.968 9.931 35.946 10.021 ;
     RECT  10.515 2.413 10.797 10.057 ;
     RECT  30.78 9.931 30.834 10.057 ;
     RECT  10.515 10.057 10.818 10.193 ;
     RECT  2.304 9.275 3.186 10.201 ;
     RECT  4.104 9.979 5.706 10.201 ;
     RECT  7.815 9.149 8.097 10.201 ;
     RECT  30.78 10.057 30.87 10.229 ;
     RECT  2.304 10.201 5.706 10.315 ;
     RECT  31.932 10.021 35.946 10.463 ;
     RECT  2.304 10.315 6.426 10.471 ;
     RECT  9.756 10.363 9.774 10.471 ;
     RECT  9.684 10.471 9.774 10.499 ;
     RECT  31.932 10.463 34.254 10.561 ;
     RECT  9.684 10.499 9.702 10.589 ;
     RECT  7.815 10.201 8.154 10.741 ;
     RECT  7.815 10.741 8.19 10.975 ;
     RECT  7.815 10.975 8.37 11.011 ;
     RECT  7.416 11.011 8.37 11.173 ;
     RECT  35.352 10.463 35.946 11.209 ;
     RECT  7.38 11.173 8.37 11.245 ;
     RECT  2.304 10.471 6.57 11.281 ;
     RECT  7.38 11.245 9.162 11.281 ;
     RECT  0.252 10.027 0.27 11.309 ;
     RECT  2.304 11.281 9.162 11.371 ;
     RECT  2.304 11.371 9.522 11.399 ;
     RECT  31.788 10.561 34.254 11.443 ;
     RECT  31.788 11.443 34.326 11.467 ;
     RECT  35.352 11.209 35.982 11.467 ;
     RECT  31.788 11.467 35.982 11.479 ;
     RECT  2.304 11.399 8.586 11.507 ;
     RECT  30.852 10.229 30.87 11.515 ;
     RECT  31.788 11.479 36.018 11.515 ;
     RECT  2.304 11.507 7.038 11.705 ;
     RECT  30.852 11.515 36.018 11.713 ;
     RECT  30.78 11.713 36.018 11.981 ;
     RECT  30.78 11.981 35.37 12.281 ;
     RECT  30.852 12.281 35.37 12.317 ;
     RECT  7.815 11.507 8.586 12.389 ;
     RECT  7.815 12.389 8.442 12.515 ;
     RECT  2.304 11.705 3.114 12.631 ;
     RECT  3.852 11.705 7.038 12.631 ;
     RECT  31.068 12.317 35.37 12.715 ;
     RECT  10.515 10.193 10.797 12.757 ;
     RECT  9.504 11.399 9.522 12.821 ;
     RECT  2.304 12.631 7.038 12.901 ;
     RECT  7.815 12.515 8.37 12.901 ;
     RECT  31.068 12.715 35.406 12.941 ;
     RECT  35.352 12.941 35.406 13.051 ;
     RECT  2.304 12.901 8.37 13.199 ;
     RECT  31.068 12.941 34.29 13.289 ;
     RECT  7.815 13.199 8.37 13.559 ;
     RECT  10.515 12.757 10.854 13.675 ;
     RECT  10.515 13.675 10.926 13.829 ;
     RECT  35.352 13.051 35.946 13.867 ;
     RECT  30.78 13.675 30.906 13.973 ;
     RECT  2.304 13.199 7.074 13.981 ;
     RECT  7.815 13.559 8.097 13.981 ;
     RECT  30.78 13.973 30.87 14.009 ;
     RECT  35.352 13.867 35.982 14.045 ;
     RECT  0.252 14.011 0.27 14.141 ;
     RECT  35.928 14.045 35.982 14.155 ;
     RECT  30.78 14.009 30.798 14.207 ;
     RECT  32.115 13.289 34.29 14.215 ;
     RECT  32.076 14.215 34.326 14.347 ;
     RECT  2.304 13.981 8.097 14.369 ;
     RECT  8.964 14.251 8.982 14.549 ;
     RECT  35.928 14.155 36.018 14.813 ;
     RECT  32.076 14.347 34.902 14.881 ;
     RECT  35.928 14.813 35.982 15.005 ;
     RECT  32.004 14.881 34.902 15.061 ;
     RECT  2.304 14.369 5.922 15.115 ;
     RECT  31.788 15.061 34.902 15.115 ;
     RECT  35.928 15.005 35.946 15.115 ;
     RECT  31.788 15.115 35.946 15.151 ;
     RECT  2.268 15.115 5.922 15.179 ;
     RECT  6.732 14.369 8.097 15.187 ;
     RECT  6.12 15.187 8.097 15.251 ;
     RECT  2.268 15.179 5.397 15.323 ;
     RECT  30.78 15.151 35.946 15.557 ;
     RECT  10.515 13.829 10.797 15.691 ;
     RECT  0.252 15.595 0.27 15.773 ;
     RECT  10.515 15.691 10.818 15.791 ;
     RECT  2.304 15.323 5.397 15.961 ;
     RECT  6.12 15.251 6.822 15.961 ;
     RECT  2.304 15.961 6.822 16.025 ;
     RECT  3.42 16.025 6.822 16.267 ;
     RECT  7.596 15.251 8.097 16.267 ;
     RECT  3.42 16.267 8.097 16.411 ;
     RECT  10.515 15.791 10.797 16.609 ;
     RECT  10.515 16.609 10.818 16.843 ;
     RECT  31.932 15.557 35.946 16.843 ;
     RECT  3.42 16.411 8.154 16.871 ;
     RECT  10.515 16.843 10.926 16.943 ;
     RECT  31.536 16.843 35.946 16.943 ;
     RECT  2.304 16.025 2.697 16.951 ;
     RECT  3.42 16.871 8.097 16.951 ;
     RECT  17.1 16.951 17.118 17.249 ;
     RECT  30.78 15.557 30.798 17.249 ;
     RECT  31.536 16.943 34.398 17.483 ;
     RECT  0.216 17.515 0.234 17.645 ;
     RECT  31.824 17.483 34.398 17.707 ;
     RECT  35.352 16.943 35.946 17.707 ;
     RECT  2.304 16.951 8.097 17.851 ;
     RECT  2.268 17.851 8.097 17.915 ;
     RECT  9.108 17.761 9.126 17.923 ;
     RECT  2.304 17.915 8.097 17.951 ;
     RECT  6.444 17.951 8.097 17.995 ;
     RECT  31.824 17.707 35.946 17.995 ;
     RECT  9.108 17.923 9.234 18.059 ;
     RECT  31.824 17.995 35.982 18.059 ;
     RECT  6.444 17.995 8.298 18.149 ;
     RECT  30.78 18.031 30.87 18.149 ;
     RECT  35.82 18.059 35.982 18.187 ;
     RECT  30.78 18.149 30.798 18.221 ;
     RECT  35.82 18.187 36.018 18.331 ;
     RECT  9.108 18.059 9.198 18.419 ;
     RECT  31.824 18.059 34.758 18.527 ;
     RECT  2.304 17.951 5.706 18.689 ;
     RECT  31.824 18.527 34.434 18.689 ;
     RECT  0.252 18.667 0.27 18.797 ;
     RECT  6.444 18.149 7.074 18.797 ;
     RECT  35.82 18.331 36.054 18.797 ;
     RECT  9.18 18.419 9.198 18.841 ;
     RECT  10.515 16.943 10.797 18.841 ;
     RECT  3.996 18.689 5.706 18.959 ;
     RECT  13.215 2.413 13.497 19.075 ;
     RECT  30.852 18.931 30.87 19.075 ;
     RECT  4.032 18.959 5.706 19.111 ;
     RECT  7.815 18.149 8.226 19.111 ;
     RECT  9.18 18.841 10.797 19.139 ;
     RECT  6.804 18.797 7.074 19.192 ;
     RECT  7.815 19.111 8.37 19.192 ;
     RECT  13.068 19.075 13.497 19.229 ;
     RECT  35.82 18.797 35.946 19.291 ;
     RECT  6.804 19.192 8.37 19.409 ;
     RECT  6.948 19.409 8.37 19.571 ;
     RECT  4.032 19.111 5.814 19.615 ;
     RECT  35.352 19.291 35.946 19.627 ;
     RECT  4.032 19.615 5.994 19.651 ;
     RECT  9.18 19.139 9.198 19.679 ;
     RECT  7.02 19.571 8.37 19.769 ;
     RECT  2.304 18.689 3.222 19.804 ;
     RECT  30.78 19.075 30.87 19.885 ;
     RECT  31.896 18.689 34.434 19.885 ;
     RECT  35.352 19.627 35.982 19.885 ;
     RECT  7.272 19.769 8.37 19.921 ;
     RECT  0.252 19.819 0.27 19.949 ;
     RECT  7.272 19.921 8.478 19.949 ;
     RECT  30.78 19.885 35.982 19.949 ;
     RECT  7.815 19.949 8.478 20.039 ;
     RECT  35.352 19.949 35.982 20.107 ;
     RECT  2.304 19.804 3.258 20.191 ;
     RECT  4.032 19.651 6.174 20.191 ;
     RECT  35.352 20.107 36.018 20.219 ;
     RECT  35.928 20.219 36.018 20.651 ;
     RECT  2.304 20.191 6.174 20.695 ;
     RECT  6.912 20.623 6.93 20.695 ;
     RECT  2.304 20.695 6.93 20.731 ;
     RECT  7.815 20.039 8.19 20.731 ;
     RECT  30.78 19.949 34.434 20.731 ;
     RECT  30.78 20.731 34.866 20.849 ;
     RECT  9 20.623 9.018 20.921 ;
     RECT  2.304 20.731 8.19 20.957 ;
     RECT  30.78 20.849 30.87 21.029 ;
     RECT  32.04 20.849 34.866 21.199 ;
     RECT  35.928 20.651 35.982 21.199 ;
     RECT  32.04 21.199 35.982 21.389 ;
     RECT  35.928 21.389 35.982 21.569 ;
     RECT  0.216 21.451 0.234 21.581 ;
     RECT  30.852 21.029 30.87 21.803 ;
     RECT  2.304 20.957 8.097 21.929 ;
     RECT  32.04 21.389 34.866 22.037 ;
     RECT  30.78 21.973 30.798 22.073 ;
     RECT  2.304 21.929 6.426 22.081 ;
     RECT  32.04 22.037 34.794 22.109 ;
     RECT  2.268 22.081 6.426 22.205 ;
     RECT  32.04 22.109 34.326 22.207 ;
     RECT  7.632 21.929 8.097 22.219 ;
     RECT  2.304 22.205 6.426 22.253 ;
     RECT  7.632 22.219 8.298 22.505 ;
     RECT  31.536 22.207 34.326 22.549 ;
     RECT  6.372 22.253 6.426 22.613 ;
     RECT  9.252 22.621 9.27 22.739 ;
     RECT  31.176 22.549 34.326 22.739 ;
     RECT  35.928 21.569 35.946 22.795 ;
     RECT  31.932 22.739 34.326 22.987 ;
     RECT  6.372 22.613 6.39 23.009 ;
     RECT  31.932 22.987 34.686 23.125 ;
     RECT  7.632 22.505 8.097 23.165 ;
     RECT  7.74 23.165 8.097 23.279 ;
     RECT  2.304 22.253 5.562 23.431 ;
     RECT  31.932 23.125 34.794 23.549 ;
     RECT  30.78 23.557 30.798 23.593 ;
     RECT  32.004 23.549 34.794 23.611 ;
     RECT  30.78 23.593 30.87 23.693 ;
     RECT  30.78 23.693 30.798 23.729 ;
     RECT  2.304 23.431 6.03 23.755 ;
     RECT  7.815 23.279 8.097 23.863 ;
     RECT  2.268 23.755 6.03 23.927 ;
     RECT  2.304 23.927 6.03 23.947 ;
     RECT  2.304 23.947 6.318 23.971 ;
     RECT  35.928 22.795 35.982 23.981 ;
     RECT  2.304 23.971 6.786 24.097 ;
     RECT  32.004 23.611 34.866 24.197 ;
     RECT  7.815 23.863 8.73 24.359 ;
     RECT  2.304 24.097 6.858 24.469 ;
     RECT  7.815 24.359 8.586 24.469 ;
     RECT  30.78 24.673 30.798 24.709 ;
     RECT  32.004 24.197 34.794 24.781 ;
     RECT  31.824 24.781 34.794 24.899 ;
     RECT  31.932 24.899 34.794 24.941 ;
     RECT  30.78 24.709 30.87 24.971 ;
     RECT  30.852 24.971 30.87 25.079 ;
     RECT  2.304 24.469 8.586 25.085 ;
     RECT  31.932 24.941 34.398 25.169 ;
     RECT  7.38 25.085 8.586 25.229 ;
     RECT  7.524 25.229 8.586 25.321 ;
     RECT  7.524 25.321 8.838 25.439 ;
     RECT  31.932 25.169 34.326 25.439 ;
     RECT  10.515 19.139 10.797 25.447 ;
     RECT  0.252 25.387 0.27 25.517 ;
     RECT  35.928 23.981 35.946 25.531 ;
     RECT  10.515 25.447 10.854 25.547 ;
     RECT  35.928 25.531 35.982 25.675 ;
     RECT  2.304 25.085 6.606 25.709 ;
     RECT  8.928 25.591 8.946 25.789 ;
     RECT  4.32 25.709 6.606 25.825 ;
     RECT  8.928 25.789 8.982 25.861 ;
     RECT  2.304 25.709 3.51 25.867 ;
     RECT  35.352 25.675 35.982 26.123 ;
     RECT  35.352 26.123 35.946 26.189 ;
     RECT  7.815 25.439 8.097 26.221 ;
     RECT  8.928 25.861 9.162 26.221 ;
     RECT  30.78 26.221 30.942 26.321 ;
     RECT  31.932 25.439 34.218 26.347 ;
     RECT  7.815 26.221 9.162 26.357 ;
     RECT  4.32 25.825 6.714 26.393 ;
     RECT  30.78 26.321 30.87 26.393 ;
     RECT  7.815 26.357 8.262 26.401 ;
     RECT  2.268 25.867 3.51 26.491 ;
     RECT  4.32 26.393 6.354 26.491 ;
     RECT  7.272 26.401 8.262 26.519 ;
     RECT  9.036 26.357 9.162 26.519 ;
     RECT  31.932 26.347 34.794 26.519 ;
     RECT  9.108 26.519 9.162 26.591 ;
     RECT  2.268 26.491 6.354 26.765 ;
     RECT  7.272 26.519 8.19 26.813 ;
     RECT  2.268 26.765 6.282 26.861 ;
     RECT  9.288 26.671 9.306 26.969 ;
     RECT  2.268 26.861 6.246 27.059 ;
     RECT  2.268 27.059 5.958 27.167 ;
     RECT  7.272 26.813 8.097 27.301 ;
     RECT  32.115 26.519 34.794 27.301 ;
     RECT  35.928 26.189 35.946 27.301 ;
     RECT  7.02 27.301 8.097 27.341 ;
     RECT  32.115 27.301 35.946 27.341 ;
     RECT  35.928 27.341 35.946 27.451 ;
     RECT  32.115 27.341 34.794 27.571 ;
     RECT  7.092 27.341 8.097 27.599 ;
     RECT  9.18 27.481 9.198 27.599 ;
     RECT  30.78 27.481 30.798 27.643 ;
     RECT  30.78 27.643 30.834 27.707 ;
     RECT  30.816 27.707 30.834 27.751 ;
     RECT  30.816 27.751 30.906 27.779 ;
     RECT  35.928 27.451 35.982 27.787 ;
     RECT  30.888 27.779 30.906 27.905 ;
     RECT  35.928 27.787 36.054 28.013 ;
     RECT  2.304 27.167 5.958 28.021 ;
     RECT  32.076 27.571 34.794 28.255 ;
     RECT  31.356 28.255 34.794 28.319 ;
     RECT  31.356 28.319 34.254 28.409 ;
     RECT  35.928 28.013 35.982 28.411 ;
     RECT  2.304 28.021 6.246 28.489 ;
     RECT  7.272 27.599 8.097 28.489 ;
     RECT  2.304 28.489 8.097 29.029 ;
     RECT  35.352 28.411 35.982 29.035 ;
     RECT  31.824 28.409 34.254 29.101 ;
     RECT  35.352 29.035 36.018 29.101 ;
     RECT  2.304 29.029 8.298 29.219 ;
     RECT  31.824 29.101 36.018 29.327 ;
     RECT  6.912 29.219 8.298 29.363 ;
     RECT  6.912 29.363 8.226 29.399 ;
     RECT  31.824 29.327 35.982 29.399 ;
     RECT  9 29.605 9.018 29.641 ;
     RECT  9 29.641 9.09 29.759 ;
     RECT  31.824 29.399 34.218 29.767 ;
     RECT  30.78 28.723 30.798 29.803 ;
     RECT  31.788 29.767 34.218 30.145 ;
     RECT  2.304 29.219 6.102 30.172 ;
     RECT  2.268 30.172 6.102 30.181 ;
     RECT  6.912 29.399 8.097 30.181 ;
     RECT  2.268 30.181 8.097 30.299 ;
     RECT  35.352 29.399 35.982 30.331 ;
     RECT  3.888 30.299 8.097 30.343 ;
     RECT  30.78 29.803 30.87 30.343 ;
     RECT  31.788 30.145 34.254 30.343 ;
     RECT  3.888 30.343 8.226 30.479 ;
     RECT  7.815 30.479 8.226 30.569 ;
     RECT  30.78 30.343 34.254 30.569 ;
     RECT  0.216 30.475 0.234 30.605 ;
     RECT  2.268 30.299 3.114 30.605 ;
     RECT  7.815 30.569 8.19 30.605 ;
     RECT  35.352 30.331 36.054 30.845 ;
     RECT  32.115 30.569 34.254 30.955 ;
     RECT  35.928 30.845 36.054 31.019 ;
     RECT  2.304 30.605 3.114 31.261 ;
     RECT  3.888 30.479 6.894 31.261 ;
     RECT  7.815 30.605 8.154 31.261 ;
     RECT  2.304 31.261 8.154 31.387 ;
     RECT  9.252 30.955 9.27 31.387 ;
     RECT  30.78 30.569 30.87 31.387 ;
     RECT  30.78 31.387 31.086 31.423 ;
     RECT  32.115 30.955 34.29 31.459 ;
     RECT  2.304 31.387 9.27 31.531 ;
     RECT  32.115 31.459 34.758 31.559 ;
     RECT  35.928 31.019 36.018 31.627 ;
     RECT  2.304 31.531 9.45 31.729 ;
     RECT  2.304 31.729 9.486 31.765 ;
     RECT  35.352 31.627 36.018 31.801 ;
     RECT  30.78 31.423 31.338 31.805 ;
     RECT  30.816 31.805 31.338 31.891 ;
     RECT  2.304 31.765 9.738 31.919 ;
     RECT  32.115 31.559 34.29 31.919 ;
     RECT  10.515 25.547 10.797 31.927 ;
     RECT  2.304 31.919 6.714 31.955 ;
     RECT  30.816 31.891 31.374 32.071 ;
     RECT  32.115 31.919 34.254 32.071 ;
     RECT  35.352 31.801 36.054 32.071 ;
     RECT  9.792 31.927 10.797 32.189 ;
     RECT  35.352 32.071 36.09 32.189 ;
     RECT  2.304 31.955 5.958 32.269 ;
     RECT  35.928 32.189 36.09 32.285 ;
     RECT  2.268 32.269 5.958 32.429 ;
     RECT  35.928 32.285 36.018 32.603 ;
     RECT  30.816 32.071 34.254 32.731 ;
     RECT  6.696 31.955 6.714 32.881 ;
     RECT  7.452 31.919 8.658 32.881 ;
     RECT  6.696 32.881 8.658 32.999 ;
     RECT  0.252 32.875 0.27 33.043 ;
     RECT  2.304 32.429 5.958 33.043 ;
     RECT  0.252 33.043 0.342 33.053 ;
     RECT  0.324 33.053 0.342 33.101 ;
     RECT  7.272 32.999 8.658 33.269 ;
     RECT  30.816 32.731 34.794 33.313 ;
     RECT  35.928 32.603 35.946 33.691 ;
     RECT  30.78 33.313 34.794 33.917 ;
     RECT  2.304 33.043 6.282 33.925 ;
     RECT  30.78 33.917 34.254 33.989 ;
     RECT  35.928 33.691 36.018 34.027 ;
     RECT  7.272 33.269 8.154 34.051 ;
     RECT  9.18 33.511 9.198 34.051 ;
     RECT  30.78 33.989 34.038 34.079 ;
     RECT  7.272 34.051 9.198 34.157 ;
     RECT  35.352 34.027 36.018 34.315 ;
     RECT  7.272 34.157 8.154 34.501 ;
     RECT  9.108 34.157 9.198 34.591 ;
     RECT  2.304 33.925 6.318 34.603 ;
     RECT  7.056 34.501 8.154 34.603 ;
     RECT  9.108 34.591 9.45 34.691 ;
     RECT  9.432 34.691 9.45 34.771 ;
     RECT  2.304 34.603 8.154 34.781 ;
     RECT  35.352 34.315 36.09 34.781 ;
     RECT  32.004 34.079 34.038 34.861 ;
     RECT  9.432 34.771 9.522 34.889 ;
     RECT  10.515 32.189 10.797 34.897 ;
     RECT  30.78 34.079 30.798 34.897 ;
     RECT  31.572 34.861 34.038 34.897 ;
     RECT  30.78 34.897 34.254 34.933 ;
     RECT  35.352 34.781 36.054 34.933 ;
     RECT  30.78 34.933 36.054 34.997 ;
     RECT  30.78 34.997 35.982 35.021 ;
     RECT  10.515 34.897 10.818 35.033 ;
     RECT  30.78 35.021 34.29 35.159 ;
     RECT  0.252 35.131 0.27 35.261 ;
     RECT  35.352 35.021 35.982 35.339 ;
     RECT  31.932 35.159 34.29 35.501 ;
     RECT  30.78 35.159 31.158 35.699 ;
     RECT  2.304 34.781 8.097 35.851 ;
     RECT  32.076 35.501 34.29 35.947 ;
     RECT  35.928 35.339 35.982 36.091 ;
     RECT  2.304 35.851 8.586 36.121 ;
     RECT  2.304 36.121 8.622 36.275 ;
     RECT  32.076 35.947 34.794 36.283 ;
     RECT  30.78 35.699 30.87 36.347 ;
     RECT  3.888 36.275 8.622 36.689 ;
     RECT  30.78 36.347 30.798 36.689 ;
     RECT  2.304 36.275 2.754 36.715 ;
     RECT  31.932 36.283 34.794 36.751 ;
     RECT  3.888 36.689 7.002 36.779 ;
     RECT  3.888 36.779 5.886 36.815 ;
     RECT  2.268 36.715 2.754 36.887 ;
     RECT  31.86 36.751 34.794 36.895 ;
     RECT  7.776 36.689 8.622 36.959 ;
     RECT  2.304 36.887 2.754 37.021 ;
     RECT  3.888 36.815 5.814 37.021 ;
     RECT  31.68 36.895 34.794 37.049 ;
     RECT  31.752 37.049 34.794 37.051 ;
     RECT  35.928 36.091 36.018 37.051 ;
     RECT  31.752 37.051 36.018 37.121 ;
     RECT  2.304 37.021 5.814 37.229 ;
     RECT  32.115 37.121 36.018 37.319 ;
     RECT  6.624 36.779 7.002 37.597 ;
     RECT  32.115 37.319 34.794 37.709 ;
     RECT  6.552 37.597 7.002 37.741 ;
     RECT  7.776 36.959 8.154 37.741 ;
     RECT  35.856 37.319 36.018 37.769 ;
     RECT  10.515 35.033 10.797 37.831 ;
     RECT  6.552 37.741 8.154 37.859 ;
     RECT  6.912 37.859 8.154 37.867 ;
     RECT  32.115 37.709 34.722 37.867 ;
     RECT  6.912 37.867 8.874 37.967 ;
     RECT  30.78 37.903 30.798 37.975 ;
     RECT  32.004 37.867 34.722 38.003 ;
     RECT  35.856 37.769 35.982 38.003 ;
     RECT  30.78 37.975 30.834 38.137 ;
     RECT  2.304 37.229 5.598 38.165 ;
     RECT  30.78 38.137 31.266 38.173 ;
     RECT  32.004 38.003 34.254 38.173 ;
     RECT  4.536 38.165 5.598 38.245 ;
     RECT  6.948 37.967 8.874 38.309 ;
     RECT  4.536 38.245 6.138 38.399 ;
     RECT  30.78 38.173 34.254 38.399 ;
     RECT  4.536 38.399 5.994 38.573 ;
     RECT  31.788 38.399 34.254 38.827 ;
     RECT  2.304 38.165 3.69 38.923 ;
     RECT  4.536 38.573 5.922 38.923 ;
     RECT  6.948 38.309 8.838 38.939 ;
     RECT  10.515 37.831 10.818 38.947 ;
     RECT  35.856 38.003 35.946 38.971 ;
     RECT  6.948 38.939 8.298 39.091 ;
     RECT  10.515 38.947 10.854 39.119 ;
     RECT  35.856 38.971 35.982 39.209 ;
     RECT  31.788 38.827 34.758 39.217 ;
     RECT  31.68 39.217 34.758 39.245 ;
     RECT  2.304 38.923 5.922 39.451 ;
     RECT  34.74 39.245 34.758 39.451 ;
     RECT  2.268 39.451 5.922 39.559 ;
     RECT  6.84 39.091 8.298 39.559 ;
     RECT  2.268 39.559 8.298 39.623 ;
     RECT  9.288 39.361 9.306 39.631 ;
     RECT  30.78 38.399 30.798 39.659 ;
     RECT  9.288 39.631 9.63 39.721 ;
     RECT  35.928 39.209 35.982 39.721 ;
     RECT  2.304 39.623 8.298 39.857 ;
     RECT  35.928 39.721 36.018 39.965 ;
     RECT  31.68 39.245 33.93 40.027 ;
     RECT  34.74 39.451 34.794 40.027 ;
     RECT  31.68 40.027 34.794 40.075 ;
     RECT  35.928 39.965 35.982 40.075 ;
     RECT  31.68 40.075 35.982 40.127 ;
     RECT  9.288 39.721 9.702 40.199 ;
     RECT  31.68 40.127 35.946 40.199 ;
     RECT  7.632 39.857 8.298 40.261 ;
     RECT  9.288 40.199 9.306 40.397 ;
     RECT  35.352 40.199 35.946 40.469 ;
     RECT  2.304 39.857 6.822 40.559 ;
     RECT  31.68 40.199 34.362 40.559 ;
     RECT  4.464 40.559 6.822 40.675 ;
     RECT  30.924 40.297 30.942 40.675 ;
     RECT  31.68 40.559 34.326 40.675 ;
     RECT  30.924 40.675 34.326 40.873 ;
     RECT  4.464 40.675 6.894 40.981 ;
     RECT  7.632 40.261 8.478 40.981 ;
     RECT  35.352 40.469 35.37 41.009 ;
     RECT  2.304 40.559 3.69 41.035 ;
     RECT  30.852 40.873 34.326 41.099 ;
     RECT  10.515 39.119 10.797 41.143 ;
     RECT  2.268 41.035 3.69 41.207 ;
     RECT  10.515 41.143 10.854 41.243 ;
     RECT  4.464 40.981 8.478 41.251 ;
     RECT  2.304 41.207 3.69 41.341 ;
     RECT  4.464 41.251 8.802 41.341 ;
     RECT  2.304 41.341 8.802 41.369 ;
     RECT  30.852 41.099 34.254 41.369 ;
     RECT  35.928 41.227 35.946 41.371 ;
     RECT  30.852 41.369 34.218 41.477 ;
     RECT  0.252 41.419 0.27 41.549 ;
     RECT  13.215 19.229 13.497 41.611 ;
     RECT  21.315 2.413 21.597 41.611 ;
     RECT  26.715 2.413 26.997 41.611 ;
     RECT  30.852 41.477 30.87 41.611 ;
     RECT  32.004 41.477 34.218 41.639 ;
     RECT  13.104 41.611 13.497 41.648 ;
     RECT  21.204 41.611 21.597 41.648 ;
     RECT  35.928 41.371 35.982 41.707 ;
     RECT  14.832 41.611 14.85 41.741 ;
     RECT  26.676 41.611 26.997 41.741 ;
     RECT  9.396 41.683 9.414 41.981 ;
     RECT  35.928 41.707 36.018 41.995 ;
     RECT  30.78 41.611 30.87 42.089 ;
     RECT  32.04 41.639 34.218 42.151 ;
     RECT  2.304 41.369 8.586 42.251 ;
     RECT  35.928 41.995 36.054 42.287 ;
     RECT  3.78 42.251 8.586 42.629 ;
     RECT  3.78 42.629 8.55 42.755 ;
     RECT  32.04 42.151 34.434 42.763 ;
     RECT  30.78 42.089 30.798 42.871 ;
     RECT  32.04 42.763 34.758 42.871 ;
     RECT  31.86 42.871 34.758 42.955 ;
     RECT  35.928 42.287 36.018 42.955 ;
     RECT  31.86 42.955 36.018 42.997 ;
     RECT  30.78 42.871 30.87 43.033 ;
     RECT  31.68 42.997 36.018 43.061 ;
     RECT  30.78 43.033 30.906 43.097 ;
     RECT  2.304 42.251 2.697 43.141 ;
     RECT  3.78 42.755 8.334 43.259 ;
     RECT  31.68 43.061 35.982 43.259 ;
     RECT  6.876 43.259 8.334 43.295 ;
     RECT  30.816 43.097 30.906 43.331 ;
     RECT  2.304 43.141 3.042 43.411 ;
     RECT  3.78 43.259 6.138 43.411 ;
     RECT  31.68 43.259 34.794 43.469 ;
     RECT  7.056 43.295 8.334 43.609 ;
     RECT  31.68 43.469 34.326 43.681 ;
     RECT  31.176 43.681 34.326 43.799 ;
     RECT  0.252 43.771 0.27 43.901 ;
     RECT  2.304 43.411 6.138 44.041 ;
     RECT  7.056 43.609 8.658 44.041 ;
     RECT  2.304 44.041 8.658 44.069 ;
     RECT  30.852 44.113 30.87 44.213 ;
     RECT  2.304 44.069 8.19 44.251 ;
     RECT  2.268 44.251 8.19 44.477 ;
     RECT  35.928 43.259 35.982 44.587 ;
     RECT  6.768 44.477 8.19 44.609 ;
     RECT  31.968 43.799 34.218 44.689 ;
     RECT  9.144 44.077 9.162 44.789 ;
     RECT  31.932 44.689 34.218 44.923 ;
     RECT  31.932 44.923 34.29 45.121 ;
     RECT  29.415 2.413 29.697 45.157 ;
     RECT  30.78 44.347 30.798 45.157 ;
     RECT  29.415 45.157 30.798 45.193 ;
     RECT  29.415 45.193 30.87 45.229 ;
     RECT  31.68 45.121 34.29 45.229 ;
     RECT  6.768 44.609 7.038 45.293 ;
     RECT  35.352 44.587 35.982 45.293 ;
     RECT  2.268 44.477 5.814 45.391 ;
     RECT  6.768 45.293 6.786 45.391 ;
     RECT  7.815 44.609 8.19 45.463 ;
     RECT  2.268 45.391 6.786 45.527 ;
     RECT  2.304 45.527 6.786 45.731 ;
     RECT  29.415 45.229 34.29 45.761 ;
     RECT  30.78 45.761 34.29 45.769 ;
     RECT  35.352 45.293 35.946 45.769 ;
     RECT  7.815 45.463 8.478 45.841 ;
     RECT  30.78 45.769 35.946 45.869 ;
     RECT  7.815 45.841 9.09 45.959 ;
     RECT  35.352 45.869 35.946 45.959 ;
     RECT  10.515 41.243 10.797 45.967 ;
     RECT  35.928 45.959 35.946 46.027 ;
     RECT  2.304 45.731 6.57 46.109 ;
     RECT  30.78 45.869 34.29 46.229 ;
     RECT  2.304 46.109 6.246 46.409 ;
     RECT  32.115 46.229 34.29 46.499 ;
     RECT  35.928 46.027 35.982 46.507 ;
     RECT  35.928 46.507 36.054 46.555 ;
     RECT  7.815 45.959 8.097 46.651 ;
     RECT  35.928 46.555 36.126 46.685 ;
     RECT  35.928 46.685 36.054 46.733 ;
     RECT  7.488 46.651 8.097 46.741 ;
     RECT  35.928 46.733 35.982 46.795 ;
     RECT  30.78 46.229 30.87 46.877 ;
     RECT  35.352 46.795 35.982 46.877 ;
     RECT  7.488 46.741 8.622 46.885 ;
     RECT  10.515 45.967 10.854 46.913 ;
     RECT  7.056 46.885 8.622 46.921 ;
     RECT  6.444 46.921 8.694 47.039 ;
     RECT  32.115 46.499 34.254 47.083 ;
     RECT  0.252 46.987 0.27 47.117 ;
     RECT  2.304 46.409 5.598 47.131 ;
     RECT  30.78 46.877 30.834 47.219 ;
     RECT  35.352 46.877 35.946 47.315 ;
     RECT  2.304 47.131 5.706 47.317 ;
     RECT  6.444 47.039 8.298 47.317 ;
     RECT  32.04 47.083 34.254 47.353 ;
     RECT  31.932 47.353 34.254 47.389 ;
     RECT  2.304 47.317 8.298 47.489 ;
     RECT  31.932 47.389 34.29 47.551 ;
     RECT  35.928 47.315 35.946 47.611 ;
     RECT  35.928 47.611 35.982 47.659 ;
     RECT  31.788 47.551 34.29 47.731 ;
     RECT  2.304 47.489 7.074 47.741 ;
     RECT  30.78 47.219 30.798 47.759 ;
     RECT  0.216 47.755 0.234 47.885 ;
     RECT  35.928 47.659 36.018 47.981 ;
     RECT  7.815 47.489 8.298 48.001 ;
     RECT  31.788 47.731 34.758 48.085 ;
     RECT  35.928 47.981 35.982 48.085 ;
     RECT  2.304 47.741 6.894 48.091 ;
     RECT  31.788 48.085 35.982 48.091 ;
     RECT  7.815 48.001 8.73 48.119 ;
     RECT  31.392 48.091 35.982 48.191 ;
     RECT  7.815 48.119 8.694 48.299 ;
     RECT  31.932 48.191 35.982 48.299 ;
     RECT  2.268 48.091 6.894 48.541 ;
     RECT  7.815 48.299 8.097 48.541 ;
     RECT  35.352 48.299 35.982 48.605 ;
     RECT  10.515 46.913 10.797 48.667 ;
     RECT  10.515 48.667 10.818 48.803 ;
     RECT  30.924 48.811 30.942 48.965 ;
     RECT  0.252 48.907 0.27 49.037 ;
     RECT  31.932 48.299 34.254 49.195 ;
     RECT  35.352 48.605 35.946 49.195 ;
     RECT  31.932 49.195 35.946 49.199 ;
     RECT  29.415 45.761 29.697 49.477 ;
     RECT  35.928 49.199 35.946 49.513 ;
     RECT  2.268 48.541 8.097 49.541 ;
     RECT  29.124 49.477 29.697 49.577 ;
     RECT  35.928 49.513 36.018 49.709 ;
     RECT  31.932 49.199 34.794 49.747 ;
     RECT  2.268 49.541 6.966 49.847 ;
     RECT  7.815 49.541 8.097 49.981 ;
     RECT  2.304 49.847 6.966 50.009 ;
     RECT  6.948 50.009 6.966 50.093 ;
     RECT  7.815 49.981 8.19 50.161 ;
     RECT  7.815 50.161 8.298 50.279 ;
     RECT  10.515 48.803 10.797 50.287 ;
     RECT  31.356 49.747 34.794 50.287 ;
     RECT  7.815 50.279 8.262 50.323 ;
     RECT  10.515 50.287 10.818 50.387 ;
     RECT  7.56 50.323 8.262 50.459 ;
     RECT  30.816 50.287 34.794 50.521 ;
     RECT  30.744 50.521 34.794 50.635 ;
     RECT  35.928 49.709 35.982 50.635 ;
     RECT  2.304 50.009 5.778 50.657 ;
     RECT  2.304 50.657 5.742 50.855 ;
     RECT  7.815 50.459 8.262 50.861 ;
     RECT  29.415 49.577 29.697 50.863 ;
     RECT  30.744 50.635 35.982 50.927 ;
     RECT  31.356 50.927 35.982 50.963 ;
     RECT  9.036 50.863 9.054 50.971 ;
     RECT  9.036 50.971 9.198 50.999 ;
     RECT  9.144 50.999 9.198 51.089 ;
     RECT  0.396 50.971 0.414 51.115 ;
     RECT  3.996 50.855 5.742 51.125 ;
     RECT  0.216 51.115 0.414 51.149 ;
     RECT  7.02 50.899 7.038 51.241 ;
     RECT  0.216 51.149 0.234 51.245 ;
     RECT  2.304 50.855 3.258 51.307 ;
     RECT  31.356 50.963 34.866 51.389 ;
     RECT  9.144 51.089 9.162 51.467 ;
     RECT  6.732 51.241 7.038 51.488 ;
     RECT  7.815 50.861 8.097 51.488 ;
     RECT  6.732 51.488 8.097 51.511 ;
     RECT  31.356 51.389 31.374 51.629 ;
     RECT  4.248 51.125 5.742 51.637 ;
     RECT  6.48 51.511 8.097 51.637 ;
     RECT  2.268 51.307 3.258 51.665 ;
     RECT  29.088 50.863 29.697 51.701 ;
     RECT  32.112 51.389 34.866 51.737 ;
     RECT  13.215 41.648 13.497 51.871 ;
     RECT  21.315 41.648 21.597 51.871 ;
     RECT  10.515 50.387 10.797 51.883 ;
     RECT  13.104 51.871 13.497 51.917 ;
     RECT  21.204 51.871 21.597 51.917 ;
     RECT  10.515 51.883 10.818 52.013 ;
     RECT  14.832 51.883 14.85 52.013 ;
     RECT  22.824 51.883 22.842 52.013 ;
     RECT  2.304 51.665 3.258 52.051 ;
     RECT  4.248 51.637 8.097 52.051 ;
     RECT  9.468 52.051 9.558 52.169 ;
     RECT  2.304 52.051 8.154 52.205 ;
     RECT  9.468 52.169 9.486 52.277 ;
     RECT  32.112 51.737 34.758 52.285 ;
     RECT  35.928 50.963 35.982 52.285 ;
     RECT  31.752 52.285 34.758 52.313 ;
     RECT  3.78 52.205 8.097 52.439 ;
     RECT  31.752 52.313 34.29 52.555 ;
     RECT  35.928 52.285 36.054 52.589 ;
     RECT  8.892 52.519 8.91 52.709 ;
     RECT  31.284 52.555 34.29 52.717 ;
     RECT  30.96 52.717 34.29 52.979 ;
     RECT  35.928 52.589 35.946 53.035 ;
     RECT  31.896 52.979 34.29 53.051 ;
     RECT  0.216 52.987 0.234 53.069 ;
     RECT  2.304 52.205 2.862 53.131 ;
     RECT  3.78 52.439 5.778 53.131 ;
     RECT  32.004 53.051 34.29 53.227 ;
     RECT  35.352 53.035 35.946 53.227 ;
     RECT  2.304 53.131 5.778 53.401 ;
     RECT  6.588 52.439 8.097 53.401 ;
     RECT  29.415 51.701 29.697 53.401 ;
     RECT  2.304 53.401 5.814 53.515 ;
     RECT  6.588 53.401 8.262 53.519 ;
     RECT  29.088 53.401 29.697 53.519 ;
     RECT  2.304 53.515 5.85 53.671 ;
     RECT  6.588 53.519 7.038 53.671 ;
     RECT  32.004 53.227 35.946 53.833 ;
     RECT  2.304 53.671 7.038 53.861 ;
     RECT  9.684 53.761 9.702 53.869 ;
     RECT  7.815 53.519 8.262 53.941 ;
     RECT  9.648 53.869 9.702 53.969 ;
     RECT  7.815 53.941 8.334 54.059 ;
     RECT  31.968 53.833 35.946 54.059 ;
     RECT  31.968 54.059 34.398 54.131 ;
     RECT  31.14 54.067 31.158 54.329 ;
     RECT  32.115 54.131 34.398 54.329 ;
     RECT  35.28 54.059 35.946 54.667 ;
     RECT  2.304 53.861 6.966 54.715 ;
     RECT  7.815 54.059 8.097 54.715 ;
     RECT  9.684 53.969 9.702 54.779 ;
     RECT  35.28 54.667 35.982 54.845 ;
     RECT  9.108 54.913 9.126 55.049 ;
     RECT  32.115 54.329 34.362 55.111 ;
     RECT  35.316 54.845 35.982 55.139 ;
     RECT  32.076 55.111 34.362 55.255 ;
     RECT  31.32 55.147 31.338 55.291 ;
     RECT  32.076 55.255 34.434 55.291 ;
     RECT  31.32 55.291 34.434 55.417 ;
     RECT  29.415 53.519 29.697 55.453 ;
     RECT  31.068 55.417 34.434 55.679 ;
     RECT  2.304 54.715 8.097 55.949 ;
     RECT  35.352 55.139 35.982 55.949 ;
     RECT  31.572 55.679 34.434 55.993 ;
     RECT  2.304 55.949 6.93 56.057 ;
     RECT  29.088 55.453 29.697 56.093 ;
     RECT  31.572 55.993 34.758 56.093 ;
     RECT  9.144 55.831 9.162 56.101 ;
     RECT  2.304 56.057 6.822 56.107 ;
     RECT  31.572 56.093 34.218 56.129 ;
     RECT  31.572 56.129 34.182 56.219 ;
     RECT  35.928 55.949 35.982 56.251 ;
     RECT  7.704 55.949 8.097 56.255 ;
     RECT  7.815 56.255 8.097 56.371 ;
     RECT  9.072 56.101 9.162 56.371 ;
     RECT  2.268 56.107 6.822 56.381 ;
     RECT  0.252 55.627 0.27 56.429 ;
     RECT  7.815 56.371 9.162 56.489 ;
     RECT  31.572 56.219 34.074 56.533 ;
     RECT  35.928 56.251 36.054 56.587 ;
     RECT  8.856 56.489 9.162 56.633 ;
     RECT  8.856 56.633 8.874 56.867 ;
     RECT  2.268 56.381 5.49 56.903 ;
     RECT  31.248 56.533 34.074 57.001 ;
     RECT  30.816 57.001 34.074 57.067 ;
     RECT  2.304 56.903 5.49 57.145 ;
     RECT  6.228 56.381 6.822 57.145 ;
     RECT  2.304 57.145 6.822 57.181 ;
     RECT  35.928 56.587 36.09 57.209 ;
     RECT  30.816 57.067 34.686 57.299 ;
     RECT  2.304 57.181 6.894 57.307 ;
     RECT  30.816 57.299 30.87 57.307 ;
     RECT  31.608 57.299 34.686 57.355 ;
     RECT  7.815 56.489 8.097 57.379 ;
     RECT  30.78 57.307 30.87 57.407 ;
     RECT  31.608 57.355 34.758 57.407 ;
     RECT  30.816 57.407 30.87 57.443 ;
     RECT  35.928 57.209 36.018 57.547 ;
     RECT  7.815 57.379 8.37 57.569 ;
     RECT  35.352 57.547 36.018 57.569 ;
     RECT  2.304 57.307 6.93 57.605 ;
     RECT  9.144 57.721 9.234 57.811 ;
     RECT  4.572 57.605 6.93 57.839 ;
     RECT  10.515 52.013 10.797 57.847 ;
     RECT  21.315 51.917 21.597 57.847 ;
     RECT  6.696 57.839 6.93 57.991 ;
     RECT  7.815 57.569 8.154 57.991 ;
     RECT  10.515 57.847 10.926 58.019 ;
     RECT  0.216 57.931 0.234 58.061 ;
     RECT  35.352 57.569 35.982 58.205 ;
     RECT  30.852 57.443 30.87 58.225 ;
     RECT  31.608 57.407 34.326 58.225 ;
     RECT  21.096 57.847 21.597 58.253 ;
     RECT  2.304 57.605 3.726 58.315 ;
     RECT  30.852 58.225 34.326 58.379 ;
     RECT  2.268 58.315 3.726 58.459 ;
     RECT  4.572 57.839 5.742 58.459 ;
     RECT  2.268 58.459 5.742 58.487 ;
     RECT  31.716 58.379 34.326 58.523 ;
     RECT  9.144 57.811 9.27 58.531 ;
     RECT  30.852 58.379 30.978 58.531 ;
     RECT  6.696 57.991 8.154 58.621 ;
     RECT  8.892 58.531 9.27 58.621 ;
     RECT  6.48 58.621 9.27 58.649 ;
     RECT  2.304 58.487 5.742 58.801 ;
     RECT  6.48 58.649 8.226 58.801 ;
     RECT  8.964 58.649 9.27 58.801 ;
     RECT  8.964 58.801 9.414 58.919 ;
     RECT  2.304 58.801 8.226 58.955 ;
     RECT  8.964 58.919 8.982 59.099 ;
     RECT  35.352 58.205 35.946 59.131 ;
     RECT  3.528 58.955 8.226 59.189 ;
     RECT  30.78 58.531 30.978 59.225 ;
     RECT  3.528 59.189 8.097 59.261 ;
     RECT  10.515 58.019 10.797 59.341 ;
     RECT  2.304 58.955 2.754 59.369 ;
     RECT  35.352 59.131 35.982 59.369 ;
     RECT  10.515 59.341 10.818 59.459 ;
     RECT  31.716 58.523 34.254 59.467 ;
     RECT  35.352 59.369 35.946 59.467 ;
     RECT  3.744 59.261 8.097 59.495 ;
     RECT  31.716 59.467 35.946 59.567 ;
     RECT  8.928 59.611 8.946 59.729 ;
     RECT  30.852 59.225 30.978 59.837 ;
     RECT  31.716 59.567 34.794 59.845 ;
     RECT  2.304 59.369 2.697 59.947 ;
     RECT  4.14 59.495 8.097 59.971 ;
     RECT  4.14 59.971 8.298 60.035 ;
     RECT  35.928 59.567 35.946 60.107 ;
     RECT  4.356 60.035 8.298 60.173 ;
     RECT  2.268 59.947 2.697 60.241 ;
     RECT  31.068 59.845 34.794 60.269 ;
     RECT  32.004 60.269 34.794 60.427 ;
     RECT  4.392 60.173 8.298 60.575 ;
     RECT  4.644 60.575 8.298 60.647 ;
     RECT  32.004 60.427 35.37 60.809 ;
     RECT  32.115 60.809 35.37 60.907 ;
     RECT  4.716 60.647 8.298 60.917 ;
     RECT  2.268 60.241 3.186 60.955 ;
     RECT  6.804 60.917 8.298 60.961 ;
     RECT  31.068 60.269 31.086 60.989 ;
     RECT  2.268 60.955 3.906 61.187 ;
     RECT  30.78 61.087 30.87 61.187 ;
     RECT  9.468 61.231 9.486 61.349 ;
     RECT  32.115 60.907 35.946 61.387 ;
     RECT  6.804 60.961 8.586 61.393 ;
     RECT  2.304 61.187 3.906 61.465 ;
     RECT  4.716 60.917 5.994 61.465 ;
     RECT  32.115 61.387 35.982 61.529 ;
     RECT  35.928 61.529 35.982 61.531 ;
     RECT  32.115 61.529 34.866 61.591 ;
     RECT  32.076 61.591 34.866 61.621 ;
     RECT  32.004 61.621 34.866 61.661 ;
     RECT  35.928 61.531 36.018 61.675 ;
     RECT  6.804 61.393 8.622 61.691 ;
     RECT  2.304 61.465 5.994 61.699 ;
     RECT  6.804 61.691 8.097 61.699 ;
     RECT  0.252 61.867 0.27 61.997 ;
     RECT  35.928 61.675 36.054 61.997 ;
     RECT  30.852 61.187 30.87 62.167 ;
     RECT  32.04 61.661 34.866 62.275 ;
     RECT  35.928 61.997 35.982 62.275 ;
     RECT  32.04 62.275 35.982 62.381 ;
     RECT  32.04 62.381 34.83 62.437 ;
     RECT  35.928 62.381 35.982 62.537 ;
     RECT  32.004 62.437 34.83 62.609 ;
     RECT  2.304 61.699 8.097 62.635 ;
     RECT  2.268 62.635 8.097 62.815 ;
     RECT  10.515 59.459 10.797 62.815 ;
     RECT  30.852 62.167 30.906 62.815 ;
     RECT  32.004 62.609 34.794 62.815 ;
     RECT  31.824 62.815 34.794 62.861 ;
     RECT  2.268 62.815 8.298 62.969 ;
     RECT  35.964 62.537 35.982 63.077 ;
     RECT  2.268 62.969 8.154 63.311 ;
     RECT  0.216 63.247 0.234 63.341 ;
     RECT  31.824 62.861 34.758 63.355 ;
     RECT  4.788 63.311 8.154 63.419 ;
     RECT  30.78 62.815 30.906 63.508 ;
     RECT  31.788 63.355 34.758 63.509 ;
     RECT  10.515 62.815 10.854 63.517 ;
     RECT  2.268 63.311 3.906 63.545 ;
     RECT  6.444 63.419 8.154 63.581 ;
     RECT  10.515 63.517 10.926 63.617 ;
     RECT  6.552 63.581 8.154 63.629 ;
     RECT  31.932 63.509 34.758 63.629 ;
     RECT  30.78 63.508 30.942 63.653 ;
     RECT  30.924 63.653 30.942 63.689 ;
     RECT  6.768 63.629 8.154 63.751 ;
     RECT  35.928 63.307 35.946 63.787 ;
     RECT  31.932 63.629 34.434 64.049 ;
     RECT  2.304 63.545 3.906 64.201 ;
     RECT  4.788 63.419 5.634 64.201 ;
     RECT  6.768 63.751 8.586 64.229 ;
     RECT  2.304 64.201 5.634 64.327 ;
     RECT  2.304 64.327 5.886 64.349 ;
     RECT  0.252 64.267 0.27 64.397 ;
     RECT  32.076 64.049 34.434 64.463 ;
     RECT  5.076 64.349 5.886 64.637 ;
     RECT  6.768 64.229 8.334 64.741 ;
     RECT  30.78 64.471 30.798 64.867 ;
     RECT  32.076 64.463 34.254 64.867 ;
     RECT  9.144 64.939 9.162 65.039 ;
     RECT  10.515 63.617 10.797 65.137 ;
     RECT  2.304 64.349 4.194 65.173 ;
     RECT  5.076 64.637 5.397 65.173 ;
     RECT  6.66 64.741 8.334 65.281 ;
     RECT  10.515 65.137 10.854 65.281 ;
     RECT  2.304 65.173 5.397 65.371 ;
     RECT  10.515 65.281 10.926 65.399 ;
     RECT  30.78 64.867 34.254 65.399 ;
     RECT  2.268 65.371 5.397 65.435 ;
     RECT  31.896 65.399 34.218 65.471 ;
     RECT  2.268 65.435 3.834 65.507 ;
     RECT  6.552 65.281 8.334 65.551 ;
     RECT  35.352 63.787 35.946 65.707 ;
     RECT  6.552 65.551 8.586 65.813 ;
     RECT  4.608 65.435 5.397 65.821 ;
     RECT  31.896 65.471 34.074 65.939 ;
     RECT  35.352 65.707 35.982 65.995 ;
     RECT  10.515 65.399 10.818 66.011 ;
     RECT  35.352 65.995 36.054 66.119 ;
     RECT  7.164 65.813 8.586 66.125 ;
     RECT  2.304 65.507 3.834 66.361 ;
     RECT  4.608 65.821 6.174 66.361 ;
     RECT  35.856 66.119 36.054 66.389 ;
     RECT  7.815 66.125 8.586 66.551 ;
     RECT  35.856 66.389 36.018 66.551 ;
     RECT  2.304 66.361 6.174 66.595 ;
     RECT  30.78 65.399 30.798 66.659 ;
     RECT  0.216 66.571 0.234 66.701 ;
     RECT  32.115 65.939 34.074 66.721 ;
     RECT  2.304 66.595 6.858 66.749 ;
     RECT  2.304 66.749 3.942 66.785 ;
     RECT  32.076 66.721 34.074 66.793 ;
     RECT  32.04 66.793 34.074 66.829 ;
     RECT  34.848 66.475 34.866 66.829 ;
     RECT  35.856 66.551 35.982 66.893 ;
     RECT  32.04 66.829 34.866 66.901 ;
     RECT  31.248 66.901 34.866 67.019 ;
     RECT  4.716 66.749 6.858 67.027 ;
     RECT  2.304 66.785 3.87 67.163 ;
     RECT  4.716 67.027 7.074 67.261 ;
     RECT  7.815 66.551 8.097 67.261 ;
     RECT  33.156 67.019 34.866 67.291 ;
     RECT  35.856 66.893 35.946 67.291 ;
     RECT  33.156 67.291 35.946 67.469 ;
     RECT  3.42 67.163 3.87 67.531 ;
     RECT  31.248 67.019 32.397 67.531 ;
     RECT  3.42 67.531 3.942 67.711 ;
     RECT  4.716 67.261 8.097 67.711 ;
     RECT  31.068 67.531 32.397 67.801 ;
     RECT  33.156 67.469 34.254 67.801 ;
     RECT  31.068 67.801 34.254 67.829 ;
     RECT  2.304 67.163 2.697 67.865 ;
     RECT  3.42 67.711 8.097 67.901 ;
     RECT  31.356 67.829 34.254 67.901 ;
     RECT  0.54 67.675 0.558 67.949 ;
     RECT  2.34 67.865 2.697 67.981 ;
     RECT  3.42 67.901 6.21 67.981 ;
     RECT  7.056 67.901 8.097 67.981 ;
     RECT  7.056 67.981 8.262 68.279 ;
     RECT  9.288 68.179 9.306 68.369 ;
     RECT  35.352 67.469 35.946 68.369 ;
     RECT  2.34 67.981 6.21 68.587 ;
     RECT  35.928 68.369 35.946 68.731 ;
     RECT  2.304 68.587 6.21 68.917 ;
     RECT  7.056 68.279 8.19 68.917 ;
     RECT  2.304 68.917 8.19 69.061 ;
     RECT  31.932 67.901 34.254 69.061 ;
     RECT  31.932 69.061 34.758 69.101 ;
     RECT  30.852 69.187 30.87 69.223 ;
     RECT  2.304 69.061 8.262 69.251 ;
     RECT  35.928 68.731 35.982 69.259 ;
     RECT  35.928 69.259 36.018 69.295 ;
     RECT  30.78 69.223 30.87 69.359 ;
     RECT  31.932 69.101 34.146 69.421 ;
     RECT  2.304 69.251 8.154 69.449 ;
     RECT  0.216 69.355 0.234 69.484 ;
     RECT  0.216 69.484 0.27 69.485 ;
     RECT  0.252 69.485 0.27 69.581 ;
     RECT  35.352 69.295 36.018 69.581 ;
     RECT  35.352 69.581 35.982 69.725 ;
     RECT  31.896 69.421 34.146 69.835 ;
     RECT  9.072 69.871 9.09 69.989 ;
     RECT  31.896 69.835 34.29 69.997 ;
     RECT  2.304 69.449 4.23 70.259 ;
     RECT  5.004 69.449 6.93 70.303 ;
     RECT  30.852 69.359 30.87 70.303 ;
     RECT  31.68 69.997 34.29 70.315 ;
     RECT  7.815 69.449 8.154 70.411 ;
     RECT  35.928 69.725 35.982 70.507 ;
     RECT  30.78 70.303 30.87 70.637 ;
     RECT  35.856 70.507 35.982 70.673 ;
     RECT  4.896 70.303 6.93 70.771 ;
     RECT  7.815 70.411 8.262 70.771 ;
     RECT  4.896 70.771 8.262 70.807 ;
     RECT  9.036 70.411 9.054 70.807 ;
     RECT  30.852 70.637 30.87 70.915 ;
     RECT  31.68 70.315 34.758 70.915 ;
     RECT  30.852 70.915 34.758 70.987 ;
     RECT  4.896 70.807 9.054 71.149 ;
     RECT  4.824 71.149 9.054 71.177 ;
     RECT  2.304 70.259 3.906 71.221 ;
     RECT  30.852 70.987 34.794 71.249 ;
     RECT  4.824 71.177 8.406 71.411 ;
     RECT  30.852 71.249 34.218 71.447 ;
     RECT  35.856 70.673 35.946 71.467 ;
     RECT  9.252 71.221 9.27 71.609 ;
     RECT  35.856 71.467 35.982 71.611 ;
     RECT  10.515 66.011 10.797 71.617 ;
     RECT  4.824 71.411 8.154 71.645 ;
     RECT  30.852 71.447 31.338 71.681 ;
     RECT  30.852 71.681 30.87 71.923 ;
     RECT  35.352 71.611 35.982 71.951 ;
     RECT  2.304 71.221 3.978 72.031 ;
     RECT  4.824 71.645 5.778 72.031 ;
     RECT  6.84 71.645 8.154 72.229 ;
     RECT  32.076 71.447 34.218 72.229 ;
     RECT  35.352 71.951 35.946 72.229 ;
     RECT  32.076 72.229 35.946 72.269 ;
     RECT  10.515 71.617 10.818 72.329 ;
     RECT  2.304 72.031 5.778 72.379 ;
     RECT  9.036 72.031 9.054 72.419 ;
     RECT  2.304 72.379 5.886 72.571 ;
     RECT  6.84 72.229 8.298 72.571 ;
     RECT  32.076 72.269 34.434 72.805 ;
     RECT  2.304 72.571 8.298 72.841 ;
     RECT  30.78 71.923 30.87 72.869 ;
     RECT  31.608 72.805 34.434 73.051 ;
     RECT  35.352 72.269 35.946 73.051 ;
     RECT  30.852 72.869 30.87 73.067 ;
     RECT  2.304 72.841 8.406 73.535 ;
     RECT  0.216 73.507 0.234 73.565 ;
     RECT  31.608 73.051 35.946 73.651 ;
     RECT  3.636 73.535 8.406 73.769 ;
     RECT  31.248 73.651 35.946 73.769 ;
     RECT  30.852 73.813 30.906 73.921 ;
     RECT  9.288 73.921 9.306 74.039 ;
     RECT  30.78 73.921 30.906 74.111 ;
     RECT  3.78 73.769 8.406 74.119 ;
     RECT  31.716 73.769 35.946 74.147 ;
     RECT  2.304 73.535 2.862 74.389 ;
     RECT  30.78 74.111 30.798 74.417 ;
     RECT  31.932 74.147 35.946 74.453 ;
     RECT  2.304 74.389 2.898 74.587 ;
     RECT  3.78 74.119 8.766 74.587 ;
     RECT  0.252 74.491 0.27 74.621 ;
     RECT  31.968 74.453 35.946 74.651 ;
     RECT  31.968 74.651 34.254 74.849 ;
     RECT  2.304 74.587 8.766 75.001 ;
     RECT  2.304 75.001 8.838 75.119 ;
     RECT  2.304 75.119 8.154 75.155 ;
     RECT  30.852 75.127 30.87 75.227 ;
     RECT  9.036 75.163 9.054 75.533 ;
     RECT  2.304 75.155 4.266 75.595 ;
     RECT  32.004 74.849 34.218 75.595 ;
     RECT  35.352 74.651 35.946 75.787 ;
     RECT  32.004 75.595 34.29 75.803 ;
     RECT  35.352 75.787 35.982 75.839 ;
     RECT  10.515 72.329 10.797 75.937 ;
     RECT  21.315 58.253 21.597 75.937 ;
     RECT  32.004 75.803 34.218 75.965 ;
     RECT  2.268 75.595 4.266 76.037 ;
     RECT  10.515 75.937 10.926 76.073 ;
     RECT  2.304 76.037 4.266 76.081 ;
     RECT  5.004 75.155 8.154 76.081 ;
     RECT  31.248 75.397 31.266 76.081 ;
     RECT  2.304 76.081 8.226 76.199 ;
     RECT  30.78 76.081 31.266 76.379 ;
     RECT  21.096 75.937 21.597 76.577 ;
     RECT  30.852 76.379 31.266 76.855 ;
     RECT  30.852 76.855 31.374 76.919 ;
     RECT  2.304 76.199 7.074 77.089 ;
     RECT  7.815 76.199 8.154 77.089 ;
     RECT  2.304 77.089 8.154 77.125 ;
     RECT  9.216 77.089 9.234 77.125 ;
     RECT  32.115 75.965 34.218 77.125 ;
     RECT  2.304 77.125 9.27 77.279 ;
     RECT  32.115 77.125 34.434 77.515 ;
     RECT  35.352 75.839 35.946 77.515 ;
     RECT  31.068 76.919 31.374 77.549 ;
     RECT  2.304 77.279 5.397 77.707 ;
     RECT  10.515 76.073 10.797 77.791 ;
     RECT  6.12 77.279 9.27 77.819 ;
     RECT  2.268 77.707 5.397 77.927 ;
     RECT  10.515 77.791 10.854 77.963 ;
     RECT  0.252 77.227 0.27 78.029 ;
     RECT  6.12 77.819 8.586 78.125 ;
     RECT  7.815 78.125 8.586 78.233 ;
     RECT  6.12 78.125 7.002 78.359 ;
     RECT  9.324 78.061 9.342 78.359 ;
     RECT  2.304 77.927 5.397 78.395 ;
     RECT  3.996 78.395 5.397 78.403 ;
     RECT  6.12 78.359 6.894 78.403 ;
     RECT  3.996 78.403 6.894 78.629 ;
     RECT  31.248 78.367 31.266 78.629 ;
     RECT  32.115 77.515 35.946 78.667 ;
     RECT  32.115 78.667 35.982 78.709 ;
     RECT  10.515 77.963 10.797 78.781 ;
     RECT  10.515 78.781 10.818 78.899 ;
     RECT  30.78 78.709 30.87 79.043 ;
     RECT  31.68 78.709 35.982 79.079 ;
     RECT  3.996 78.629 6.858 79.141 ;
     RECT  3.924 79.141 6.858 79.195 ;
     RECT  2.304 78.395 2.862 79.249 ;
     RECT  3.744 79.195 6.858 79.249 ;
     RECT  35.928 79.079 35.982 79.321 ;
     RECT  2.304 79.249 6.858 79.483 ;
     RECT  7.815 78.233 8.097 79.483 ;
     RECT  2.304 79.483 8.097 79.591 ;
     RECT  9.144 78.601 9.162 79.591 ;
     RECT  2.304 79.591 9.162 79.619 ;
     RECT  35.928 79.321 36.018 79.661 ;
     RECT  29.415 56.093 29.697 79.717 ;
     RECT  30.78 79.043 30.798 79.717 ;
     RECT  29.415 79.717 30.798 79.825 ;
     RECT  31.752 79.079 34.794 79.825 ;
     RECT  2.304 79.619 8.586 79.915 ;
     RECT  29.415 79.825 34.794 80.059 ;
     RECT  35.928 79.661 35.946 80.059 ;
     RECT  2.268 79.915 8.586 80.123 ;
     RECT  29.415 80.059 35.946 80.141 ;
     RECT  29.415 80.141 34.794 80.249 ;
     RECT  35.928 80.141 35.946 80.395 ;
     RECT  2.304 80.123 8.586 80.401 ;
     RECT  2.304 80.401 9.162 80.519 ;
     RECT  7.815 80.519 9.162 80.699 ;
     RECT  31.896 80.249 34.758 80.699 ;
     RECT  35.928 80.395 35.982 80.875 ;
     RECT  7.815 80.699 8.334 81.059 ;
     RECT  31.932 80.699 34.758 81.067 ;
     RECT  2.304 80.519 7.002 81.101 ;
     RECT  9.144 80.699 9.162 81.211 ;
     RECT  7.815 81.059 8.262 81.389 ;
     RECT  3.42 81.101 7.002 81.437 ;
     RECT  4.212 81.437 7.002 81.445 ;
     RECT  7.815 81.389 8.154 81.445 ;
     RECT  35.928 80.875 36.018 81.547 ;
     RECT  3.42 81.437 3.438 81.599 ;
     RECT  4.212 81.445 8.154 81.599 ;
     RECT  10.515 78.899 10.797 81.607 ;
     RECT  30.78 80.249 30.798 81.607 ;
     RECT  10.515 81.607 10.926 81.779 ;
     RECT  35.928 81.547 36.054 81.835 ;
     RECT  2.304 81.101 2.697 81.841 ;
     RECT  30.78 81.607 30.87 81.869 ;
     RECT  9.144 81.211 9.234 82.111 ;
     RECT  10.515 81.779 10.797 82.111 ;
     RECT  2.304 81.841 2.97 82.139 ;
     RECT  4.212 81.599 8.097 82.211 ;
     RECT  9.144 82.111 10.797 82.211 ;
     RECT  9.144 82.211 9.774 82.247 ;
     RECT  9.684 82.247 9.774 82.319 ;
     RECT  31.932 81.067 34.83 82.349 ;
     RECT  9.684 82.319 9.702 82.409 ;
     RECT  4.212 82.211 7.038 82.589 ;
     RECT  35.82 81.835 36.054 82.637 ;
     RECT  30.852 81.869 30.87 82.651 ;
     RECT  35.82 82.637 35.982 82.651 ;
     RECT  10.515 82.211 10.797 82.687 ;
     RECT  30.78 82.651 30.87 82.687 ;
     RECT  35.352 82.651 35.982 82.751 ;
     RECT  30.78 82.687 31.05 82.787 ;
     RECT  31.932 82.349 34.398 82.795 ;
     RECT  10.515 82.687 10.926 82.823 ;
     RECT  4.212 82.589 6.93 82.831 ;
     RECT  7.815 82.211 8.097 82.831 ;
     RECT  7.815 82.831 8.694 82.949 ;
     RECT  30.852 82.787 31.05 82.957 ;
     RECT  31.86 82.795 34.398 82.957 ;
     RECT  2.304 82.139 2.826 82.987 ;
     RECT  2.304 82.987 3.078 83.035 ;
     RECT  3.996 82.831 6.93 83.035 ;
     RECT  10.515 82.823 10.854 83.129 ;
     RECT  0.252 83.035 0.27 83.165 ;
     RECT  30.852 82.957 34.398 83.219 ;
     RECT  31.896 83.219 34.398 83.275 ;
     RECT  35.352 82.751 35.946 83.275 ;
     RECT  2.304 83.035 6.93 83.335 ;
     RECT  9.18 83.227 9.27 83.489 ;
     RECT  31.896 83.275 35.946 83.489 ;
     RECT  31.896 83.489 35.046 83.525 ;
     RECT  9.18 83.489 9.198 83.561 ;
     RECT  30.78 83.533 30.798 83.633 ;
     RECT  7.815 82.949 8.406 83.731 ;
     RECT  32.076 83.525 35.046 83.759 ;
     RECT  7.815 83.731 8.442 83.767 ;
     RECT  2.304 83.335 7.074 83.995 ;
     RECT  7.815 83.767 9.162 83.995 ;
     RECT  2.304 83.995 9.162 84.029 ;
     RECT  2.304 84.029 8.097 84.181 ;
     RECT  35.928 83.489 35.946 84.235 ;
     RECT  2.268 84.181 8.097 84.269 ;
     RECT  35.028 83.759 35.046 84.571 ;
     RECT  32.076 83.759 34.29 84.577 ;
     RECT  9.144 84.029 9.162 84.641 ;
     RECT  31.932 84.577 34.29 84.715 ;
     RECT  35.028 84.571 35.082 84.715 ;
     RECT  10.515 83.129 10.797 84.721 ;
     RECT  10.515 84.721 10.818 84.839 ;
     RECT  0.252 84.715 0.27 84.893 ;
     RECT  35.928 84.235 35.982 84.983 ;
     RECT  31.932 84.715 35.082 85.051 ;
     RECT  35.928 84.983 35.946 85.051 ;
     RECT  2.304 84.269 8.097 85.261 ;
     RECT  31.932 85.051 35.946 85.261 ;
     RECT  31.86 85.261 35.946 85.289 ;
     RECT  31.86 85.289 35.91 85.387 ;
     RECT  2.304 85.261 8.406 85.991 ;
     RECT  0.252 85.867 0.27 85.997 ;
     RECT  30.78 85.927 30.798 86.027 ;
     RECT  31.788 85.387 35.91 86.189 ;
     RECT  2.304 85.991 6.642 86.333 ;
     RECT  7.416 85.991 8.406 86.369 ;
     RECT  3.6 86.333 6.642 86.459 ;
     RECT  2.304 86.333 2.79 86.495 ;
     RECT  3.6 86.459 3.978 86.495 ;
     RECT  4.716 86.459 6.462 86.495 ;
     RECT  7.56 86.369 8.406 86.611 ;
     RECT  32.04 86.189 35.91 86.729 ;
     RECT  2.415 86.495 2.79 86.765 ;
     RECT  3.6 86.495 3.798 86.765 ;
     RECT  4.716 86.495 5.922 86.765 ;
     RECT  7.56 86.611 8.55 86.801 ;
     RECT  33.156 86.729 35.91 86.837 ;
     RECT  3.708 86.765 3.798 86.999 ;
     RECT  4.716 86.765 5.397 86.999 ;
     RECT  7.56 86.801 8.097 86.999 ;
     RECT  32.04 86.729 32.397 86.999 ;
     RECT  33.264 86.837 35.91 86.999 ;
     RECT  3.708 86.999 3.726 87.035 ;
     RECT  30.78 86.971 30.798 87.071 ;
     RECT  33.336 86.999 35.334 87.269 ;
     RECT  33.336 87.269 35.154 87.341 ;
     RECT  33.588 87.341 35.154 87.809 ;
     RECT  33.588 87.809 35.082 88.079 ;
     RECT  33.588 88.079 34.506 88.115 ;
     RECT  34.38 88.115 34.506 88.151 ;
     RECT  34.488 88.151 34.506 88.259 ;
     RECT  2.415 86.765 2.697 88.307 ;
     RECT  5.115 86.999 5.397 88.307 ;
     RECT  7.815 86.999 8.097 88.307 ;
     RECT  10.515 84.839 10.797 88.307 ;
     RECT  13.215 51.917 13.497 88.307 ;
     RECT  15.915 2.413 16.197 88.307 ;
     RECT  18.615 2.413 18.897 88.307 ;
     RECT  21.315 76.577 21.597 88.307 ;
     RECT  24.015 2.413 24.297 88.307 ;
     RECT  26.715 41.741 26.997 88.307 ;
     RECT  29.415 80.249 29.697 88.307 ;
     RECT  32.115 86.999 32.397 88.307 ;
     RECT  2.415 88.307 2.505 88.577 ;
     RECT  5.115 88.307 5.205 88.577 ;
     RECT  7.815 88.307 7.905 88.577 ;
     RECT  10.515 88.307 10.605 88.577 ;
     RECT  13.215 88.307 13.305 88.577 ;
     RECT  15.915 88.307 16.005 88.577 ;
     RECT  18.615 88.307 18.705 88.577 ;
     RECT  21.315 88.307 21.405 88.577 ;
     RECT  24.015 88.307 24.105 88.577 ;
     RECT  26.715 88.307 26.805 88.577 ;
     RECT  29.415 88.307 29.505 88.577 ;
     RECT  32.115 88.307 32.205 88.577 ;
     RECT  18.18 90.588 18.198 90.605 ;
    LAYER M4 ;
     RECT  0.156 4.416 2.408 86.376 ;
     RECT  2.408 2.148 2.512 88.572 ;
     RECT  2.512 2.418 2.704 88.302 ;
     RECT  2.704 4.416 2.765 7.944 ;
     RECT  2.704 33.024 2.765 36.264 ;
     RECT  2.704 43.296 2.765 45.72 ;
     RECT  2.704 46.8 2.765 51.144 ;
     RECT  2.704 52.272 2.765 54.216 ;
     RECT  2.704 55.44 2.765 58.536 ;
     RECT  2.704 68.112 2.765 68.376 ;
     RECT  2.704 70.656 2.765 71.64 ;
     RECT  2.765 6.816 2.801 7.944 ;
     RECT  2.704 8.976 2.801 11.208 ;
     RECT  2.704 13.872 2.801 14.136 ;
     RECT  2.704 27.6 2.801 28.296 ;
     RECT  2.704 38.016 2.801 41.448 ;
     RECT  2.765 43.872 2.801 44.424 ;
     RECT  2.765 45.696 2.801 45.72 ;
     RECT  2.765 53.52 2.801 54.216 ;
     RECT  2.704 73.056 2.801 73.08 ;
     RECT  2.704 74.592 2.801 77.928 ;
     RECT  2.704 82.992 2.801 83.64 ;
     RECT  2.765 4.416 2.837 5.544 ;
     RECT  2.765 70.656 2.837 71.496 ;
     RECT  2.704 81.072 2.837 81.096 ;
     RECT  2.801 10.128 2.873 11.208 ;
     RECT  2.801 14.112 2.873 14.136 ;
     RECT  2.704 22.608 2.873 26.52 ;
     RECT  2.704 30.192 2.873 31.464 ;
     RECT  2.765 47.088 2.873 47.928 ;
     RECT  2.765 52.272 2.873 52.296 ;
     RECT  2.704 63.792 2.873 66.6 ;
     RECT  2.801 38.016 2.909 39.816 ;
     RECT  2.765 55.728 2.909 58.536 ;
     RECT  2.704 60.912 2.909 62.52 ;
     RECT  2.704 84.864 2.909 86.664 ;
     RECT  2.801 41.088 2.981 41.448 ;
     RECT  2.909 62.496 2.981 62.52 ;
     RECT  2.837 4.512 3.017 5.544 ;
     RECT  2.873 10.128 3.017 10.152 ;
     RECT  2.873 63.792 3.017 66.168 ;
     RECT  2.801 74.592 3.017 74.664 ;
     RECT  2.801 82.992 3.089 83.064 ;
     RECT  2.909 85.392 3.089 86.664 ;
     RECT  2.873 22.608 3.125 25.512 ;
     RECT  2.704 20.88 3.197 21.48 ;
     RECT  2.765 49.008 3.197 49.56 ;
     RECT  2.909 60.912 3.197 61.128 ;
     RECT  3.017 64.368 3.197 66.168 ;
     RECT  2.704 79.296 3.197 79.8 ;
     RECT  2.909 55.728 3.233 58.152 ;
     RECT  2.801 76.272 3.233 77.928 ;
     RECT  2.704 18.768 3.269 19.848 ;
     RECT  2.765 33.024 3.269 35.88 ;
     RECT  2.765 50.64 3.269 51.144 ;
     RECT  2.704 69.456 3.269 69.48 ;
     RECT  3.017 4.512 3.305 5.496 ;
     RECT  2.801 8.976 3.305 9 ;
     RECT  2.873 11.184 3.305 11.208 ;
     RECT  2.704 15.744 3.305 15.816 ;
     RECT  2.801 43.872 3.305 44.28 ;
     RECT  3.197 49.536 3.305 49.56 ;
     RECT  3.233 76.368 3.305 77.928 ;
     RECT  3.089 83.04 3.305 83.064 ;
     RECT  3.197 20.88 3.341 20.904 ;
     RECT  3.269 50.64 3.341 50.664 ;
     RECT  3.305 4.512 3.395 5.16 ;
     RECT  2.801 53.52 3.413 53.544 ;
     RECT  3.233 55.728 3.413 57 ;
     RECT  3.089 85.488 3.457 86.664 ;
     RECT  3.125 22.608 3.635 24.888 ;
     RECT  2.909 38.016 3.635 39.768 ;
     RECT  2.981 41.088 3.635 41.112 ;
     RECT  2.873 26.496 3.697 26.52 ;
     RECT  2.801 27.6 3.697 27.864 ;
     RECT  3.635 38.688 3.731 39.096 ;
     RECT  3.457 86.64 3.737 86.664 ;
     RECT  2.704 17.04 3.769 17.64 ;
     RECT  3.269 18.768 3.769 19.224 ;
     RECT  3.395 4.512 3.773 4.536 ;
     RECT  2.801 6.816 3.841 6.84 ;
     RECT  2.837 70.656 3.875 71.352 ;
     RECT  3.769 17.04 3.877 19.224 ;
     RECT  3.697 26.496 3.877 27.864 ;
     RECT  3.697 42.144 3.877 42.168 ;
     RECT  3.836 13.776 3.923 13.8 ;
     RECT  2.873 30.192 3.949 31.416 ;
     RECT  3.877 16.224 3.964 19.224 ;
     RECT  3.884 72.912 3.971 72.936 ;
     RECT  3.197 60.96 3.98 61.128 ;
     RECT  3.733 79.2 3.98 79.224 ;
     RECT  3.98 60.96 3.985 62.088 ;
     RECT  3.305 77.52 3.985 77.928 ;
     RECT  3.985 83.232 4.021 83.256 ;
     RECT  3.805 69.504 4.025 69.528 ;
     RECT  3.964 18.24 4.097 19.224 ;
     RECT  2.801 7.92 4.124 7.944 ;
     RECT  3.269 33.792 4.124 35.88 ;
     RECT  3.913 37.632 4.124 37.656 ;
     RECT  3.017 74.592 4.129 74.616 ;
     RECT  3.305 43.92 4.165 44.28 ;
     RECT  3.733 45.648 4.165 45.672 ;
     RECT  2.873 47.712 4.165 47.928 ;
     RECT  3.457 85.488 4.201 85.512 ;
     RECT  4.129 74.064 4.213 74.616 ;
     RECT  3.949 29.52 4.268 31.416 ;
     RECT  3.305 76.368 4.268 76.392 ;
     RECT  3.985 77.52 4.268 78.168 ;
     RECT  4.268 29.52 4.309 31.656 ;
     RECT  4.309 54.096 4.345 54.12 ;
     RECT  3.985 60.96 4.345 62.184 ;
     RECT  4.165 47.712 4.381 48.504 ;
     RECT  3.197 64.56 4.417 66.168 ;
     RECT  3.949 71.376 4.417 71.4 ;
     RECT  4.268 76.368 4.417 78.168 ;
     RECT  3.98 79.152 4.417 79.224 ;
     RECT  4.381 14.544 4.453 14.568 ;
     RECT  4.309 80.544 4.453 80.568 ;
     RECT  4.345 54.096 4.489 54.6 ;
     RECT  3.413 55.728 4.489 55.752 ;
     RECT  4.381 47.328 4.501 48.504 ;
     RECT  4.501 47.136 4.525 48.504 ;
     RECT  3.877 26.496 4.556 27.912 ;
     RECT  4.124 7.872 4.561 7.944 ;
     RECT  2.765 68.352 4.561 68.376 ;
     RECT  4.556 26.496 4.597 28.488 ;
     RECT  4.309 29.52 4.597 32.52 ;
     RECT  4.453 50.688 4.652 50.712 ;
     RECT  4.525 51.888 4.652 51.912 ;
     RECT  4.381 20.784 4.669 20.808 ;
     RECT  3.635 24 4.705 24.024 ;
     RECT  4.489 54.096 4.777 55.752 ;
     RECT  2.704 12.72 4.789 12.744 ;
     RECT  4.453 14.544 4.837 14.808 ;
     RECT  3.964 16.224 4.837 17.112 ;
     RECT  4.165 43.92 4.844 45.672 ;
     RECT  3.233 58.128 4.844 58.152 ;
     RECT  4.345 59.28 4.844 62.184 ;
     RECT  3.877 42.144 4.885 42.744 ;
     RECT  4.844 43.776 4.885 45.672 ;
     RECT  4.417 76.368 4.921 79.224 ;
     RECT  4.453 80.544 4.921 81.48 ;
     RECT  4.097 18.816 4.933 19.224 ;
     RECT  4.669 20.304 4.933 20.808 ;
     RECT  4.777 53.52 5.065 55.752 ;
     RECT  3.413 56.976 5.065 57 ;
     RECT  5.065 5.088 5.108 5.112 ;
     RECT  3.841 6.768 5.108 6.84 ;
     RECT  4.561 7.872 5.108 7.992 ;
     RECT  4.093 9.984 5.108 10.248 ;
     RECT  4.789 12.384 5.108 13.08 ;
     RECT  4.837 14.544 5.108 17.112 ;
     RECT  4.933 18.816 5.108 20.808 ;
     RECT  3.733 22.224 5.108 22.248 ;
     RECT  4.705 23.904 5.108 24.024 ;
     RECT  4.789 25.392 5.108 25.416 ;
     RECT  4.597 26.496 5.108 32.52 ;
     RECT  4.124 33.792 5.108 37.656 ;
     RECT  3.731 38.784 5.108 39.096 ;
     RECT  3.949 40.416 5.108 40.44 ;
     RECT  4.885 42.144 5.108 45.672 ;
     RECT  4.525 46.704 5.108 48.504 ;
     RECT  4.652 50.688 5.108 51.912 ;
     RECT  5.065 53.52 5.108 57 ;
     RECT  4.844 58.128 5.108 62.184 ;
     RECT  4.057 63.264 5.108 63.288 ;
     RECT  4.417 64.32 5.108 66.168 ;
     RECT  4.885 67.152 5.108 67.176 ;
     RECT  4.561 68.256 5.108 68.376 ;
     RECT  4.949 69.552 5.108 69.576 ;
     RECT  4.417 71.376 5.108 72.456 ;
     RECT  4.213 74.064 5.108 75.384 ;
     RECT  4.921 76.368 5.108 81.48 ;
     RECT  4.021 83.232 5.108 84.024 ;
     RECT  4.201 85.392 5.108 85.512 ;
     RECT  5.108 2.148 5.212 88.572 ;
     RECT  5.212 2.418 5.404 88.302 ;
     RECT  5.404 74.064 5.465 75 ;
     RECT  5.404 68.784 5.555 72.936 ;
     RECT  5.404 19.632 5.573 19.8 ;
     RECT  5.404 50.16 5.596 50.376 ;
     RECT  5.404 8.976 5.609 9.288 ;
     RECT  5.404 10.848 5.645 11.352 ;
     RECT  5.404 29.52 5.651 36.312 ;
     RECT  5.404 28.464 5.681 28.488 ;
     RECT  5.651 29.52 5.681 32.568 ;
     RECT  5.555 71.088 5.681 72.936 ;
     RECT  5.465 74.304 5.681 75 ;
     RECT  5.404 45.696 5.699 47.352 ;
     RECT  5.596 50.16 5.699 50.28 ;
     RECT  5.699 47.136 5.717 47.352 ;
     RECT  5.681 29.616 5.725 32.568 ;
     RECT  5.699 45.696 5.725 46.152 ;
     RECT  5.404 58.08 5.795 66.168 ;
     RECT  5.795 58.08 5.897 64.968 ;
     RECT  5.795 66.048 5.939 66.168 ;
     RECT  5.609 8.976 5.941 9.096 ;
     RECT  5.404 6.72 5.987 6.744 ;
     RECT  5.941 8.976 5.987 9 ;
     RECT  5.897 58.08 5.997 63.624 ;
     RECT  5.404 22.224 6.005 22.248 ;
     RECT  5.404 37.584 6.035 39.096 ;
     RECT  5.681 72.384 6.035 72.936 ;
     RECT  5.725 29.616 6.041 31.944 ;
     RECT  5.404 53.52 6.083 56.376 ;
     RECT  5.997 58.08 6.083 62.184 ;
     RECT  5.555 68.784 6.113 69.48 ;
     RECT  6.083 54.72 6.124 56.376 ;
     RECT  5.681 74.304 6.131 74.328 ;
     RECT  6.035 72.912 6.157 72.936 ;
     RECT  6.083 58.56 6.185 62.184 ;
     RECT  5.651 34.128 6.257 36.312 ;
     RECT  5.997 63.216 6.257 63.624 ;
     RECT  6.257 34.128 6.329 35.352 ;
     RECT  5.717 47.28 6.38 47.352 ;
     RECT  5.404 48.912 6.38 49.032 ;
     RECT  5.404 40.32 6.401 42.792 ;
     RECT  5.573 19.632 6.433 19.656 ;
     RECT  6.38 47.28 6.467 49.032 ;
     RECT  5.404 17.088 6.473 17.112 ;
     RECT  5.404 86.064 6.473 86.088 ;
     RECT  5.404 51.648 6.517 52.392 ;
     RECT  6.517 51.648 6.563 53.064 ;
     RECT  5.404 26.352 6.572 26.76 ;
     RECT  6.035 38.736 6.572 39.096 ;
     RECT  6.401 40.32 6.572 41.736 ;
     RECT  5.725 45.696 6.581 46.104 ;
     RECT  6.185 58.56 6.581 61.032 ;
     RECT  6.185 62.16 6.581 62.184 ;
     RECT  6.517 20.736 6.604 20.76 ;
     RECT  6.572 25.68 6.613 26.76 ;
     RECT  6.035 37.584 6.613 37.608 ;
     RECT  6.373 57.024 6.617 57.048 ;
     RECT  6.563 53.04 6.653 53.064 ;
     RECT  6.613 25.056 6.659 26.76 ;
     RECT  6.572 38.736 6.659 41.736 ;
     RECT  5.645 11.328 6.689 11.352 ;
     RECT  6.659 26.352 6.689 26.76 ;
     RECT  5.404 79.2 6.689 80.376 ;
     RECT  5.404 15.984 6.721 16.008 ;
     RECT  5.404 23.904 6.785 23.976 ;
     RECT  6.659 25.056 6.785 25.224 ;
     RECT  6.721 15.984 6.793 16.584 ;
     RECT  5.404 44.448 6.797 44.472 ;
     RECT  6.581 45.696 6.797 45.72 ;
     RECT  6.793 81.504 6.865 81.528 ;
     RECT  5.404 13.056 6.973 13.56 ;
     RECT  6.467 48.912 7.017 49.032 ;
     RECT  6.517 50.064 7.017 50.088 ;
     RECT  6.433 18.768 7.045 19.656 ;
     RECT  6.041 30.144 7.045 31.944 ;
     RECT  5.681 71.088 7.045 71.4 ;
     RECT  6.581 58.56 7.117 58.728 ;
     RECT  5.404 67.296 7.225 67.32 ;
     RECT  6.113 68.928 7.225 69.48 ;
     RECT  6.721 83.76 7.225 83.784 ;
     RECT  7.045 18.24 7.237 19.656 ;
     RECT  6.563 51.648 7.333 52.008 ;
     RECT  6.829 8.064 7.369 8.088 ;
     RECT  7.017 48.912 7.429 50.088 ;
     RECT  7.333 51.504 7.429 52.008 ;
     RECT  6.659 40.32 7.436 41.736 ;
     RECT  6.401 42.768 7.436 42.792 ;
     RECT  5.939 66.048 7.436 66.072 ;
     RECT  5.404 85.056 7.441 85.08 ;
     RECT  7.333 62.304 7.477 62.328 ;
     RECT  6.257 63.6 7.477 63.624 ;
     RECT  6.785 23.904 7.573 25.224 ;
     RECT  6.689 79.632 7.573 80.376 ;
     RECT  7.429 48.912 7.585 52.008 ;
     RECT  7.225 83.76 7.585 84.024 ;
     RECT  7.441 85.056 7.585 85.608 ;
     RECT  6.124 54.72 7.649 55.704 ;
     RECT  6.397 7.008 7.657 7.032 ;
     RECT  7.261 5.04 7.669 5.064 ;
     RECT  7.009 21.648 7.669 21.672 ;
     RECT  7.573 23.136 7.669 25.224 ;
     RECT  7.117 58.08 7.669 58.728 ;
     RECT  5.404 76.944 7.669 76.968 ;
     RECT  7.573 78.096 7.669 78.12 ;
     RECT  7.573 79.632 7.669 80.472 ;
     RECT  6.865 81.504 7.669 82.488 ;
     RECT  7.669 21.648 7.693 25.224 ;
     RECT  6.329 34.128 7.801 34.632 ;
     RECT  7.669 5.04 7.808 5.88 ;
     RECT  7.657 6.864 7.808 7.032 ;
     RECT  7.369 8.016 7.808 8.088 ;
     RECT  6.397 10.32 7.808 10.344 ;
     RECT  6.973 13.056 7.808 14.088 ;
     RECT  6.793 15.648 7.808 16.584 ;
     RECT  7.237 18.24 7.808 19.944 ;
     RECT  7.693 21.12 7.808 25.224 ;
     RECT  6.997 26.784 7.808 27.336 ;
     RECT  6.965 28.512 7.808 28.536 ;
     RECT  7.045 29.616 7.808 31.944 ;
     RECT  7.801 33.6 7.808 34.632 ;
     RECT  6.613 36.816 7.808 37.608 ;
     RECT  6.659 38.736 7.808 39.336 ;
     RECT  7.436 40.32 7.808 42.792 ;
     RECT  7.261 43.92 7.808 43.944 ;
     RECT  6.467 47.28 7.808 47.736 ;
     RECT  7.585 48.912 7.808 52.872 ;
     RECT  7.649 54.72 7.808 56.232 ;
     RECT  7.669 57.408 7.808 58.728 ;
     RECT  6.581 60 7.808 61.032 ;
     RECT  7.477 62.304 7.808 63.864 ;
     RECT  5.897 64.944 7.808 64.968 ;
     RECT  7.436 66.048 7.808 66.12 ;
     RECT  7.225 67.296 7.808 69.48 ;
     RECT  7.045 70.8 7.808 71.88 ;
     RECT  7.669 74.688 7.808 74.712 ;
     RECT  7.669 76.944 7.808 78.12 ;
     RECT  7.669 79.632 7.808 82.488 ;
     RECT  7.585 83.76 7.808 85.608 ;
     RECT  7.808 2.148 7.912 88.572 ;
     RECT  7.912 2.418 8.104 88.302 ;
     RECT  8.104 33.6 8.165 34.776 ;
     RECT  8.104 63.072 8.165 63.096 ;
     RECT  8.104 78.096 8.165 78.12 ;
     RECT  8.104 26.784 8.201 26.808 ;
     RECT  8.104 57.408 8.237 57.432 ;
     RECT  8.104 8.016 8.243 8.04 ;
     RECT  8.104 9.072 8.243 11.112 ;
     RECT  8.104 18.192 8.243 18.216 ;
     RECT  8.104 20.544 8.243 21.144 ;
     RECT  8.165 34.128 8.243 34.776 ;
     RECT  8.104 36.816 8.243 36.84 ;
     RECT  8.104 68.208 8.243 68.232 ;
     RECT  8.104 69.456 8.243 69.72 ;
     RECT  8.104 71.088 8.243 71.256 ;
     RECT  8.104 74.688 8.243 74.712 ;
     RECT  8.104 50.832 8.273 52.008 ;
     RECT  8.243 71.088 8.273 71.112 ;
     RECT  8.104 81.36 8.273 81.384 ;
     RECT  8.243 11.088 8.281 11.112 ;
     RECT  8.104 22.224 8.309 22.248 ;
     RECT  8.104 39.312 8.309 39.336 ;
     RECT  8.104 40.32 8.309 41.736 ;
     RECT  8.243 9.072 8.417 9.096 ;
     RECT  8.243 34.128 8.489 34.152 ;
     RECT  8.309 40.32 8.489 40.344 ;
     RECT  8.309 41.712 10.508 41.736 ;
     RECT  8.273 51.648 10.508 52.008 ;
     RECT  8.243 69.456 10.508 69.48 ;
     RECT  10.508 2.148 10.612 88.572 ;
     RECT  10.612 2.418 10.804 88.302 ;
     RECT  10.804 51.648 10.829 52.008 ;
     RECT  10.804 41.616 13.208 41.64 ;
     RECT  10.829 51.648 13.208 51.912 ;
     RECT  10.804 69.456 13.208 69.48 ;
     RECT  13.208 2.148 13.312 88.572 ;
     RECT  13.312 2.418 13.504 88.302 ;
     RECT  13.504 41.616 14.821 41.64 ;
     RECT  13.504 51.648 14.821 51.912 ;
     RECT  14.821 41.616 14.861 41.736 ;
     RECT  14.861 41.712 15.908 41.736 ;
     RECT  14.821 51.648 15.908 52.008 ;
     RECT  13.504 69.456 15.908 69.48 ;
     RECT  15.908 2.148 16.012 88.572 ;
     RECT  16.012 2.418 16.204 88.302 ;
     RECT  5.653 90.576 18.209 90.6 ;
     RECT  16.204 41.712 18.608 41.736 ;
     RECT  16.204 51.648 18.608 52.008 ;
     RECT  16.204 69.456 18.608 69.48 ;
     RECT  18.608 2.148 18.712 88.572 ;
     RECT  18.712 2.418 18.904 88.302 ;
     RECT  18.904 41.616 21.308 41.64 ;
     RECT  18.904 51.648 21.308 51.912 ;
     RECT  18.904 69.456 21.308 69.48 ;
     RECT  21.308 2.148 21.412 88.572 ;
     RECT  21.412 2.418 21.604 88.302 ;
     RECT  21.604 51.648 22.813 51.912 ;
     RECT  21.604 41.616 23.893 41.64 ;
     RECT  23.893 41.616 24.008 41.736 ;
     RECT  22.813 51.648 24.008 52.008 ;
     RECT  21.604 69.456 24.008 69.48 ;
     RECT  24.008 2.148 24.112 88.572 ;
     RECT  24.112 2.418 24.304 88.302 ;
     RECT  24.304 41.712 26.708 41.736 ;
     RECT  24.304 51.648 26.708 52.008 ;
     RECT  24.304 69.456 26.708 69.48 ;
     RECT  26.708 2.148 26.812 88.572 ;
     RECT  26.812 2.418 27.004 88.302 ;
     RECT  27.004 41.712 29.408 41.736 ;
     RECT  27.004 51.648 29.408 52.008 ;
     RECT  27.004 69.456 29.408 69.48 ;
     RECT  29.408 2.148 29.512 88.572 ;
     RECT  29.512 2.418 29.704 88.302 ;
     RECT  29.704 41.616 30.769 41.64 ;
     RECT  30.769 41.616 30.809 41.736 ;
     RECT  30.769 31.776 30.917 31.8 ;
     RECT  29.704 69.456 31.921 69.48 ;
     RECT  29.704 51.648 32.065 52.008 ;
     RECT  31.921 69.456 32.065 70.008 ;
     RECT  32.065 16.8 32.108 16.824 ;
     RECT  31.957 32.496 32.108 32.52 ;
     RECT  30.809 41.712 32.108 41.736 ;
     RECT  32.065 51.36 32.108 52.008 ;
     RECT  31.993 53.568 32.108 53.592 ;
     RECT  31.993 61.632 32.108 61.656 ;
     RECT  32.065 69.216 32.108 70.008 ;
     RECT  31.993 79.728 32.108 79.752 ;
     RECT  32.108 2.148 32.212 88.572 ;
     RECT  32.212 2.418 32.404 88.302 ;
     RECT  32.404 64.08 32.465 64.872 ;
     RECT  32.404 51.36 32.537 52.248 ;
     RECT  32.404 28.416 32.573 29.208 ;
     RECT  32.404 68.4 32.789 70.008 ;
     RECT  32.404 53.568 32.969 53.592 ;
     RECT  32.465 64.704 32.969 64.872 ;
     RECT  32.969 64.848 33.005 64.872 ;
     RECT  32.404 84.048 33.041 84.072 ;
     RECT  32.404 11.376 33.113 11.976 ;
     RECT  32.404 82.416 33.113 82.44 ;
     RECT  32.404 79.728 33.185 79.752 ;
     RECT  32.404 35.136 33.221 35.16 ;
     RECT  32.404 43.248 33.293 44.184 ;
     RECT  32.404 66.192 33.293 66.504 ;
     RECT  32.404 81.024 33.293 81.048 ;
     RECT  32.789 68.4 33.433 69.48 ;
     RECT  32.404 30.912 33.437 32.52 ;
     RECT  33.433 67.776 33.469 69.48 ;
     RECT  32.404 26.064 33.577 26.328 ;
     RECT  33.113 11.376 33.653 11.4 ;
     RECT  32.404 18.432 33.653 18.456 ;
     RECT  32.404 48.144 33.653 48.168 ;
     RECT  32.404 58.032 33.757 58.68 ;
     RECT  32.404 60.528 33.757 60.552 ;
     RECT  32.404 36.912 33.761 37.656 ;
     RECT  32.404 41.712 33.761 41.784 ;
     RECT  33.437 30.912 33.869 31.56 ;
     RECT  33.293 66.192 34.085 66.216 ;
     RECT  33.869 31.44 34.157 31.56 ;
     RECT  32.404 13.008 34.189 13.032 ;
     RECT  32.404 14.88 34.189 14.904 ;
     RECT  32.404 16.8 34.189 17.112 ;
     RECT  32.404 21.552 34.189 21.576 ;
     RECT  33.577 26.064 34.189 26.808 ;
     RECT  32.573 28.416 34.189 28.44 ;
     RECT  33.761 36.912 34.189 36.936 ;
     RECT  33.293 43.248 34.189 43.944 ;
     RECT  32.537 51.6 34.189 52.248 ;
     RECT  33.757 53.52 34.189 53.544 ;
     RECT  33.757 58.032 34.189 60.552 ;
     RECT  32.404 62.496 34.189 62.52 ;
     RECT  33.469 67.68 34.189 69.48 ;
     RECT  32.404 73.872 34.189 74.136 ;
     RECT  32.404 75.12 34.189 75.144 ;
     RECT  32.404 76.992 34.189 77.592 ;
     RECT  33.649 78.816 34.189 78.84 ;
     RECT  34.189 18.48 34.225 22.344 ;
     RECT  34.189 23.472 34.225 27 ;
     RECT  34.189 38.352 34.225 38.376 ;
     RECT  34.189 40.416 34.225 40.44 ;
     RECT  34.189 50.16 34.225 55.32 ;
     RECT  34.189 67.632 34.225 71.784 ;
     RECT  34.189 72.912 34.225 77.736 ;
     RECT  34.189 83.952 34.225 83.976 ;
     RECT  34.225 67.632 34.261 77.736 ;
     RECT  34.189 78.816 34.261 80.76 ;
     RECT  34.009 5.376 34.333 5.4 ;
     RECT  34.333 5.376 34.405 5.544 ;
     RECT  34.225 83.952 34.477 84.12 ;
     RECT  34.477 83.952 34.549 84.744 ;
     RECT  34.549 83.952 34.621 85.416 ;
     RECT  34.189 28.416 34.657 29.4 ;
     RECT  34.189 57.84 34.657 60.744 ;
     RECT  34.261 67.632 34.657 80.76 ;
     RECT  34.189 10.656 34.693 11.016 ;
     RECT  34.189 12.24 34.693 13.416 ;
     RECT  34.225 38.352 34.693 38.52 ;
     RECT  34.405 4.416 34.729 5.544 ;
     RECT  34.189 7.296 34.729 9.24 ;
     RECT  34.189 14.832 34.729 14.904 ;
     RECT  34.189 16.08 34.729 17.256 ;
     RECT  34.225 18.48 34.729 27 ;
     RECT  34.657 28.08 34.729 29.4 ;
     RECT  34.189 32.592 34.729 32.616 ;
     RECT  34.189 35.616 34.729 36.936 ;
     RECT  34.189 45.36 34.729 47.16 ;
     RECT  34.189 49.056 34.729 49.08 ;
     RECT  34.225 50.16 34.729 55.8 ;
     RECT  34.657 67.44 34.729 80.76 ;
     RECT  34.189 82.8 34.729 82.824 ;
     RECT  34.621 83.952 34.729 86.184 ;
     RECT  34.729 4.416 34.765 9.24 ;
     RECT  34.693 10.656 34.765 13.416 ;
     RECT  34.729 34.992 34.765 36.936 ;
     RECT  34.693 38.352 34.765 39.144 ;
     RECT  34.225 40.416 34.765 41.064 ;
     RECT  34.189 62.496 34.765 65.256 ;
     RECT  34.765 4.416 34.801 13.416 ;
     RECT  34.729 14.832 34.801 29.4 ;
     RECT  34.729 66.48 34.801 80.76 ;
     RECT  34.657 57.072 34.837 60.744 ;
     RECT  34.765 61.872 34.837 65.256 ;
     RECT  34.729 82.32 35.125 86.184 ;
     RECT  34.157 31.44 35.341 31.464 ;
     RECT  34.729 32.592 35.341 33.864 ;
     RECT  34.765 34.992 35.341 41.064 ;
     RECT  34.189 42.192 35.341 43.944 ;
     RECT  34.729 45.36 35.341 55.8 ;
     RECT  34.837 57.072 35.341 65.256 ;
     RECT  34.801 66.48 35.341 81.096 ;
     RECT  34.801 4.416 35.377 29.4 ;
     RECT  35.341 30.816 35.377 41.064 ;
     RECT  35.341 57.072 35.809 81.096 ;
     RECT  35.125 82.32 35.809 86.376 ;
     RECT  35.377 4.416 35.917 41.064 ;
     RECT  35.341 42.192 35.917 55.8 ;
     RECT  35.809 57.072 35.917 86.376 ;
     RECT  35.917 4.416 36.54 86.376 ;
    LAYER M5 ;
     RECT  2.4 2.137 2.52 2.151 ;
     RECT  5.1 2.137 5.22 2.151 ;
     RECT  7.8 2.137 7.92 2.151 ;
     RECT  10.5 2.137 10.62 2.151 ;
     RECT  13.2 2.137 13.32 2.151 ;
     RECT  15.9 2.137 16.02 2.151 ;
     RECT  18.6 2.137 18.72 2.151 ;
     RECT  21.3 2.137 21.42 2.151 ;
     RECT  24 2.137 24.12 2.151 ;
     RECT  26.7 2.137 26.82 2.151 ;
     RECT  29.4 2.137 29.52 2.151 ;
     RECT  32.1 2.137 32.22 2.151 ;
     RECT  2.4 2.151 2.712 4.501 ;
     RECT  7.8 2.151 8.112 5.029 ;
     RECT  2.4 4.501 3.384 5.171 ;
     RECT  5.1 2.151 5.412 6.709 ;
     RECT  5.1 6.709 5.976 6.805 ;
     RECT  7.68 5.029 8.112 6.899 ;
     RECT  7.8 6.899 8.112 8.005 ;
     RECT  4.176 6.805 5.976 9.011 ;
     RECT  4.176 9.011 5.928 10.213 ;
     RECT  7.8 8.005 8.232 11.123 ;
     RECT  4.128 10.213 5.928 12.709 ;
     RECT  3.888 12.709 5.928 13.525 ;
     RECT  3.888 13.525 6.216 15.637 ;
     RECT  7.8 11.123 8.112 15.637 ;
     RECT  3.888 15.637 8.112 16.019 ;
     RECT  3.888 16.019 5.412 17.891 ;
     RECT  7.056 16.019 8.112 18.181 ;
     RECT  7.056 18.181 8.232 18.275 ;
     RECT  6.624 18.757 6.648 19.621 ;
     RECT  6.528 19.621 6.648 19.909 ;
     RECT  7.8 18.275 8.232 19.909 ;
     RECT  6.528 19.909 8.232 21.683 ;
     RECT  7.68 21.683 8.232 22.259 ;
     RECT  2.4 5.171 2.712 22.597 ;
     RECT  7.68 22.259 8.112 23.125 ;
     RECT  6.528 21.683 6.552 23.893 ;
     RECT  7.584 23.125 8.112 23.893 ;
     RECT  6.528 23.893 8.112 23.939 ;
     RECT  6.816 23.939 8.112 25.045 ;
     RECT  4.8 17.891 5.412 25.427 ;
     RECT  6.624 25.045 8.112 25.715 ;
     RECT  2.4 22.597 3.624 26.485 ;
     RECT  2.4 26.485 3.96 26.531 ;
     RECT  3.936 26.531 3.96 27.301 ;
     RECT  4.992 25.427 5.412 27.301 ;
     RECT  7.392 25.715 8.112 27.301 ;
     RECT  3.936 27.301 5.412 27.877 ;
     RECT  7.008 27.301 8.112 28.547 ;
     RECT  3.888 27.877 5.412 29.605 ;
     RECT  7.8 28.547 8.112 29.605 ;
     RECT  3.888 29.605 5.928 30.133 ;
     RECT  7.056 29.605 8.112 30.133 ;
     RECT  2.4 26.531 2.712 30.181 ;
     RECT  3.888 30.133 8.112 30.181 ;
     RECT  2.4 30.181 8.112 30.947 ;
     RECT  2.4 30.947 6.696 31.379 ;
     RECT  2.4 31.379 3 31.427 ;
     RECT  4.32 31.379 6.696 31.955 ;
     RECT  4.32 31.955 6.168 32.531 ;
     RECT  2.4 31.427 2.712 33.973 ;
     RECT  7.8 30.947 8.112 34.741 ;
     RECT  2.4 33.973 3.432 34.835 ;
     RECT  4.512 32.531 6.168 36.661 ;
     RECT  7.8 34.741 8.232 36.851 ;
     RECT  4.176 36.661 6.168 36.997 ;
     RECT  2.4 34.835 2.712 38.005 ;
     RECT  4.176 36.997 6.648 38.005 ;
     RECT  2.4 38.005 6.648 41.123 ;
     RECT  4.176 41.123 6.648 41.221 ;
     RECT  7.8 36.851 8.112 41.221 ;
     RECT  24 2.151 24.312 41.605 ;
     RECT  4.176 41.221 8.112 41.651 ;
     RECT  23.904 41.605 24.312 41.747 ;
     RECT  7.488 41.651 8.112 43.955 ;
     RECT  4.176 41.651 6.168 44.245 ;
     RECT  3.744 44.245 6.168 45.059 ;
     RECT  3.744 45.059 3.768 45.683 ;
     RECT  5.1 45.059 6.168 46.069 ;
     RECT  5.1 46.069 6.456 47.125 ;
     RECT  4.512 47.125 6.456 47.701 ;
     RECT  7.8 43.955 8.112 47.701 ;
     RECT  4.512 47.701 8.112 48.515 ;
     RECT  4.704 48.515 8.112 51.539 ;
     RECT  4.704 51.539 6.552 51.635 ;
     RECT  7.8 51.539 8.112 52.837 ;
     RECT  5.1 51.635 6.552 53.075 ;
     RECT  5.1 53.075 6.072 55.141 ;
     RECT  4.896 55.141 6.072 55.237 ;
     RECT  4.896 55.237 6.408 57.059 ;
     RECT  7.68 52.837 8.112 58.069 ;
     RECT  4.896 57.059 6.072 58.117 ;
     RECT  4.368 58.117 6.072 58.549 ;
     RECT  7.248 58.069 8.112 58.549 ;
     RECT  4.368 58.549 8.112 59.315 ;
     RECT  4.512 59.315 8.112 60.949 ;
     RECT  4.032 60.949 8.112 61.043 ;
     RECT  4.032 61.043 6.072 61.859 ;
     RECT  4.032 61.859 5.928 62.195 ;
     RECT  7.344 61.043 8.112 62.339 ;
     RECT  7.488 62.339 8.112 63.107 ;
     RECT  7.68 63.107 8.112 63.875 ;
     RECT  5.1 62.195 5.928 64.979 ;
     RECT  4.032 62.195 4.056 65.509 ;
     RECT  3.936 65.509 4.056 65.699 ;
     RECT  7.8 63.875 8.112 66.085 ;
     RECT  5.1 64.979 5.832 66.133 ;
     RECT  5.1 66.133 5.928 67.141 ;
     RECT  4.992 67.141 5.928 67.331 ;
     RECT  7.488 66.085 8.112 68.197 ;
     RECT  4.992 67.331 5.688 68.773 ;
     RECT  7.488 68.197 8.232 68.917 ;
     RECT  4.992 68.773 6.024 69.587 ;
     RECT  7.056 68.917 8.232 69.731 ;
     RECT  3.936 65.699 3.96 70.645 ;
     RECT  7.056 69.731 8.112 71.221 ;
     RECT  3.84 70.645 3.96 71.363 ;
     RECT  7.056 71.221 8.232 71.891 ;
     RECT  3.936 71.363 3.96 72.325 ;
     RECT  5.1 69.587 6.024 72.325 ;
     RECT  3.936 72.325 6.024 72.901 ;
     RECT  3.936 72.901 6.12 74.339 ;
     RECT  7.8 71.891 8.232 74.677 ;
     RECT  7.68 74.677 8.232 74.723 ;
     RECT  7.68 74.723 8.112 78.085 ;
     RECT  3.936 74.339 5.688 78.131 ;
     RECT  3.936 78.131 3.96 79.141 ;
     RECT  3.936 79.141 4.056 79.235 ;
     RECT  7.584 78.085 8.112 80.341 ;
     RECT  6.912 80.341 8.112 81.539 ;
     RECT  7.68 81.539 8.112 83.749 ;
     RECT  4.032 79.235 4.056 84.035 ;
     RECT  6.864 83.749 8.112 85.091 ;
     RECT  7.68 85.091 8.112 85.619 ;
     RECT  2.4 41.123 2.712 86.005 ;
     RECT  2.4 86.005 3.432 86.675 ;
     RECT  2.4 86.675 2.712 88.569 ;
     RECT  7.8 85.619 8.112 88.569 ;
     RECT  10.5 2.151 10.812 88.569 ;
     RECT  13.2 2.151 13.512 88.569 ;
     RECT  15.9 2.151 16.212 88.569 ;
     RECT  18.6 2.151 18.912 88.569 ;
     RECT  21.3 2.151 21.612 88.569 ;
     RECT  24 41.747 24.312 88.569 ;
     RECT  26.7 2.151 27.012 88.569 ;
     RECT  29.4 2.151 29.712 88.569 ;
     RECT  32.1 2.151 32.412 88.569 ;
     RECT  2.4 88.569 2.52 88.583 ;
     RECT  5.1 78.131 5.688 88.583 ;
     RECT  7.8 88.569 7.92 88.583 ;
     RECT  10.5 88.569 10.62 88.583 ;
     RECT  13.2 88.569 13.32 88.583 ;
     RECT  15.9 88.569 16.02 88.583 ;
     RECT  18.6 88.569 18.72 88.583 ;
     RECT  21.3 88.569 21.42 88.583 ;
     RECT  24 88.569 24.12 88.583 ;
     RECT  26.7 88.569 26.82 88.583 ;
     RECT  29.4 88.569 29.52 88.583 ;
     RECT  32.1 88.569 32.22 88.583 ;
     RECT  5.664 88.583 5.688 90.611 ;
     RECT  2.712 6.805 4.176 10.213 ;
     RECT  2.712 10.213 4.128 12.709 ;
     RECT  2.712 12.709 3.888 17.891 ;
     RECT  7.056 18.275 7.8 18.757 ;
     RECT  5.412 18.757 6.624 19.621 ;
     RECT  6.648 18.757 7.8 19.909 ;
     RECT  5.412 19.621 6.528 23.939 ;
     RECT  6.552 21.683 7.68 23.125 ;
     RECT  3.624 22.597 4.8 25.427 ;
     RECT  6.552 23.125 7.584 23.893 ;
     RECT  5.412 23.939 6.816 25.045 ;
     RECT  5.412 25.045 6.624 25.715 ;
     RECT  3.624 25.427 4.992 26.485 ;
     RECT  3.96 26.485 4.992 27.301 ;
     RECT  2.712 26.531 3.936 27.877 ;
     RECT  2.712 27.877 3.888 30.181 ;
     RECT  7.008 28.547 7.8 29.605 ;
     RECT  5.928 29.605 7.056 30.133 ;
     RECT  6.696 30.947 7.8 31.955 ;
     RECT  3 31.379 4.32 31.427 ;
     RECT  4.32 32.531 4.512 33.973 ;
     RECT  3.432 33.973 4.512 34.835 ;
     RECT  2.712 36.661 4.176 38.005 ;
     RECT  6.648 36.997 7.8 41.221 ;
     RECT  2.712 41.123 4.176 44.245 ;
     RECT  6.168 41.651 7.488 43.955 ;
     RECT  2.712 44.245 3.744 45.683 ;
     RECT  3.768 45.059 5.1 45.683 ;
     RECT  4.512 45.683 5.1 47.125 ;
     RECT  6.456 46.069 7.8 47.701 ;
     RECT  6.552 51.539 7.8 52.837 ;
     RECT  6.552 52.837 7.68 53.075 ;
     RECT  6.408 55.237 7.68 57.059 ;
     RECT  6.072 57.059 7.68 58.069 ;
     RECT  6.072 58.069 7.248 58.549 ;
     RECT  2.712 60.949 4.032 65.509 ;
     RECT  6.072 61.043 7.344 61.859 ;
     RECT  5.928 61.859 7.344 62.339 ;
     RECT  4.056 62.195 5.1 65.699 ;
     RECT  5.832 64.979 5.928 66.133 ;
     RECT  2.712 65.509 3.936 70.645 ;
     RECT  3.96 65.699 5.1 67.141 ;
     RECT  3.96 67.141 4.992 69.587 ;
     RECT  5.688 67.331 5.928 68.773 ;
     RECT  6.024 68.773 7.488 68.917 ;
     RECT  6.024 68.917 7.056 71.891 ;
     RECT  3.96 69.587 5.1 72.325 ;
     RECT  8.112 69.731 8.232 71.221 ;
     RECT  2.712 70.645 3.84 71.363 ;
     RECT  2.712 71.363 3.936 79.235 ;
     RECT  6.024 71.891 6.12 72.901 ;
     RECT  3.96 78.131 5.1 79.141 ;
     RECT  4.056 79.141 5.1 84.035 ;
     RECT  2.712 79.235 4.032 84.035 ;
     RECT  5.688 80.341 6.912 81.539 ;
     RECT  5.688 83.749 6.864 85.091 ;
  END
END dsfd_hstnh_513
END LIBRARY
